VERSION 5.5 ;
NAMESCASESENSITIVE ON ;
BUSBITCHARS "[]" ;
DIVIDERCHAR "/" ;

PROPERTYDEFINITIONS
  LAYER routingPitch REAL ;
END PROPERTYDEFINITIONS

UNITS
  DATABASE MICRONS 1000 ;
END UNITS
MANUFACTURINGGRID 0.01 ;
LAYER POLY1
  TYPE MASTERSLICE ;
END POLY1

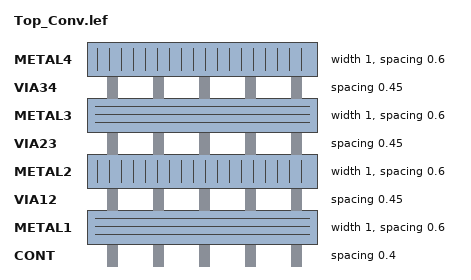
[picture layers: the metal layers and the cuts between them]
LAYER CONT
  TYPE CUT ;
  SPACING 0.4 ;
END CONT

LAYER METAL1
  TYPE ROUTING ;
  DIRECTION HORIZONTAL ;
  PITCH 0 ;
  WIDTH 1 ;
  SPACING 0.6 ;
  PROPERTY routingPitch 1.25 ;
END METAL1

LAYER VIA12
  TYPE CUT ;
  SPACING 0.45 ;
END VIA12

LAYER METAL2
  TYPE ROUTING ;
  DIRECTION VERTICAL ;
  PITCH 0 ;
  WIDTH 1 ;
  SPACING 0.6 ;
  PROPERTY routingPitch 1.4 ;
END METAL2

LAYER VIA23
  TYPE CUT ;
  SPACING 0.45 ;
END VIA23

LAYER METAL3
  TYPE ROUTING ;
  DIRECTION HORIZONTAL ;
  PITCH 0 ;
  WIDTH 1 ;
  SPACING 0.6 ;
  PROPERTY routingPitch 1.25 ;
END METAL3

LAYER VIA34
  TYPE CUT ;
  SPACING 0.45 ;
END VIA34

LAYER METAL4
  TYPE ROUTING ;
  DIRECTION VERTICAL ;
  PITCH 0 ;
  WIDTH 1 ;
  SPACING 0.6 ;
  PROPERTY routingPitch 1.4 ;
END METAL4

LAYER OVERLAP
  TYPE OVERLAP ;
END OVERLAP

VIARULE M4_M3 GENERATE
  LAYER METAL3 ;
    ENCLOSURE 0.2 0.2 ;
  LAYER METAL4 ;
    ENCLOSURE 0.15 0.15 ;
  LAYER VIA34 ;
    RECT -0.25 -0.25 0.25 0.25 ;
    SPACING 1 BY 1 ;
END M4_M3

VIARULE M3_M2 GENERATE
  LAYER METAL2 ;
    ENCLOSURE 0.2 0.2 ;
  LAYER METAL3 ;
    ENCLOSURE 0.15 0.15 ;
  LAYER VIA23 ;
    RECT -0.25 -0.25 0.25 0.25 ;
    SPACING 1 BY 1 ;
END M3_M2

VIARULE M2_M1 GENERATE
  LAYER METAL1 ;
    ENCLOSURE 0.2 0.2 ;
  LAYER METAL2 ;
    ENCLOSURE 0.15 0.15 ;
  LAYER VIA12 ;
    RECT -0.25 -0.25 0.25 0.25 ;
    SPACING 1 BY 1 ;
END M2_M1

VIARULE M1_POLY1 GENERATE
  LAYER POLY1 ;
    ENCLOSURE 0.2 0.2 ;
  LAYER METAL1 ;
    ENCLOSURE 0.15 0.15 ;
  LAYER CONT ;
    RECT -0.2 -0.2 0.2 0.2 ;
    SPACING 1 BY 1 ;
END M1_POLY1

VIA M1_POLY1
  LAYER CONT ;
    RECT -0.2 -0.2 0.2 0.2 ;
  LAYER POLY1 ;
    RECT -0.4 -0.4 0.4 0.4 ;
  LAYER METAL1 ;
    RECT -0.35 -0.35 0.35 0.35 ;
END M1_POLY1

VIA M2_M1
  LAYER VIA12 ;
    RECT -0.25 -0.25 0.25 0.25 ;
  LAYER METAL2 ;
    RECT -0.4 -0.4 0.4 0.4 ;
  LAYER METAL1 ;
    RECT -0.45 -0.45 0.45 0.45 ;
END M2_M1

VIA M3_M2
  LAYER VIA23 ;
    RECT -0.25 -0.25 0.25 0.25 ;
  LAYER METAL3 ;
    RECT -0.4 -0.4 0.4 0.4 ;
  LAYER METAL2 ;
    RECT -0.45 -0.45 0.45 0.45 ;
END M3_M2

VIA M4_M3
  LAYER VIA34 ;
    RECT -0.25 -0.25 0.25 0.25 ;
  LAYER METAL4 ;
    RECT -0.4 -0.4 0.4 0.4 ;
  LAYER METAL3 ;
    RECT -0.45 -0.45 0.45 0.45 ;
END M4_M3


MACRO ConvNN_AvgPool
  PIN n_Kvmm_AP_Dr_bit<9>
    DIRECTION INOUT ;
    USE SIGNAL ;
    PORT
      LAYER METAL3 ;
        RECT 671.3 1946.49 672.7 1948.73 ;
    END
  END n_Kvmm_AP_Dr_bit<9>
  PIN n_Kvmm_AP_Dr_bit<8>
    DIRECTION INOUT ;
    USE SIGNAL ;
    PORT
      LAYER METAL3 ;
        RECT 657.3 1946.49 658.7 1948.73 ;
    END
  END n_Kvmm_AP_Dr_bit<8>
  PIN n_SR_k_col_CLKB
    DIRECTION INOUT ;
    USE SIGNAL ;
    PORT
      LAYER METAL3 ;
        RECT 643.3 1946.49 644.7 1948.73 ;
    END
  END n_SR_k_col_CLKB
  PIN e_sub_img_out<37>
    DIRECTION INOUT ;
    USE SIGNAL ;
    PORT
      LAYER METAL3 ;
        RECT 1894.72 1375.24 1897.02 1376.64 ;
    END
  END e_sub_img_out<37>
  PIN e_sub_img_out<36>
    DIRECTION INOUT ;
    USE SIGNAL ;
    PORT
      LAYER METAL3 ;
        RECT 1894.72 1389.24 1897.02 1390.64 ;
    END
  END e_sub_img_out<36>
  PIN e_sub_img_out<35>
    DIRECTION INOUT ;
    USE SIGNAL ;
    PORT
      LAYER METAL3 ;
        RECT 1894.72 1403.24 1897.02 1404.64 ;
    END
  END e_sub_img_out<35>
  PIN e_sub_img_out<34>
    DIRECTION INOUT ;
    USE SIGNAL ;
    PORT
      LAYER METAL3 ;
        RECT 1894.72 1417.24 1897.02 1418.64 ;
    END
  END e_sub_img_out<34>
  PIN e_sub_img_out<33>
    DIRECTION INOUT ;
    USE SIGNAL ;
    PORT
      LAYER METAL3 ;
        RECT 1894.72 1431.24 1897.02 1432.64 ;
    END
  END e_sub_img_out<33>
  PIN e_sub_img_out<32>
    DIRECTION INOUT ;
    USE SIGNAL ;
    PORT
      LAYER METAL3 ;
        RECT 1894.72 1445.24 1897.02 1446.64 ;
    END
  END e_sub_img_out<32>
  PIN e_sub_img_out<31>
    DIRECTION INOUT ;
    USE SIGNAL ;
    PORT
      LAYER METAL3 ;
        RECT 1894.72 1459.24 1897.02 1460.64 ;
    END
  END e_sub_img_out<31>
  PIN e_sub_img_out<30>
    DIRECTION INOUT ;
    USE SIGNAL ;
    PORT
      LAYER METAL3 ;
        RECT 1894.72 1473.24 1897.02 1474.64 ;
    END
  END e_sub_img_out<30>
  PIN e_sub_img_out<29>
    DIRECTION INOUT ;
    USE SIGNAL ;
    PORT
      LAYER METAL3 ;
        RECT 1894.72 1487.24 1897.02 1488.64 ;
    END
  END e_sub_img_out<29>
  PIN e_sub_img_out<28>
    DIRECTION INOUT ;
    USE SIGNAL ;
    PORT
      LAYER METAL3 ;
        RECT 1894.72 1501.24 1897.02 1502.64 ;
    END
  END e_sub_img_out<28>
  PIN e_sub_img_out<27>
    DIRECTION INOUT ;
    USE SIGNAL ;
    PORT
      LAYER METAL3 ;
        RECT 1894.72 1515.24 1897.02 1516.64 ;
    END
  END e_sub_img_out<27>
  PIN e_sub_img_out<26>
    DIRECTION INOUT ;
    USE SIGNAL ;
    PORT
      LAYER METAL3 ;
        RECT 1894.72 1529.24 1897.02 1530.64 ;
    END
  END e_sub_img_out<26>
  PIN e_sub_img_out<25>
    DIRECTION INOUT ;
    USE SIGNAL ;
    PORT
      LAYER METAL3 ;
        RECT 1894.72 1543.24 1897.02 1544.64 ;
    END
  END e_sub_img_out<25>
  PIN e_sub_img_out<24>
    DIRECTION INOUT ;
    USE SIGNAL ;
    PORT
      LAYER METAL3 ;
        RECT 1894.72 1557.24 1897.02 1558.64 ;
    END
  END e_sub_img_out<24>
  PIN e_sub_img_out<23>
    DIRECTION INOUT ;
    USE SIGNAL ;
    PORT
      LAYER METAL3 ;
        RECT 1894.72 1571.24 1897.02 1572.64 ;
    END
  END e_sub_img_out<23>
  PIN e_sub_img_out<22>
    DIRECTION INOUT ;
    USE SIGNAL ;
    PORT
      LAYER METAL3 ;
        RECT 1894.72 1585.24 1897.02 1586.64 ;
    END
  END e_sub_img_out<22>
  PIN e_sub_img_out<21>
    DIRECTION INOUT ;
    USE SIGNAL ;
    PORT
      LAYER METAL3 ;
        RECT 1894.72 1599.24 1897.02 1600.64 ;
    END
  END e_sub_img_out<21>
  PIN e_sub_img_out<20>
    DIRECTION INOUT ;
    USE SIGNAL ;
    PORT
      LAYER METAL3 ;
        RECT 1894.72 1613.24 1897.02 1614.64 ;
    END
  END e_sub_img_out<20>
  PIN e_sub_img_out<19>
    DIRECTION INOUT ;
    USE SIGNAL ;
    PORT
      LAYER METAL3 ;
        RECT 1894.72 1627.24 1897.02 1628.64 ;
    END
  END e_sub_img_out<19>
  PIN e_sub_img_out<18>
    DIRECTION INOUT ;
    USE SIGNAL ;
    PORT
      LAYER METAL3 ;
        RECT 1894.72 1641.24 1897.02 1642.64 ;
    END
  END e_sub_img_out<18>
  PIN e_sub_img_out<17>
    DIRECTION INOUT ;
    USE SIGNAL ;
    PORT
      LAYER METAL3 ;
        RECT 1894.72 1655.24 1897.02 1656.64 ;
    END
  END e_sub_img_out<17>
  PIN e_sub_img_out<16>
    DIRECTION INOUT ;
    USE SIGNAL ;
    PORT
      LAYER METAL3 ;
        RECT 1894.72 1669.24 1897.02 1670.64 ;
    END
  END e_sub_img_out<16>
  PIN e_sub_img_out<15>
    DIRECTION INOUT ;
    USE SIGNAL ;
    PORT
      LAYER METAL3 ;
        RECT 1894.72 1683.24 1897.02 1684.64 ;
    END
  END e_sub_img_out<15>
  PIN e_sub_img_out<14>
    DIRECTION INOUT ;
    USE SIGNAL ;
    PORT
      LAYER METAL3 ;
        RECT 1894.72 1697.24 1897.02 1698.64 ;
    END
  END e_sub_img_out<14>
  PIN e_sub_img_out<13>
    DIRECTION INOUT ;
    USE SIGNAL ;
    PORT
      LAYER METAL3 ;
        RECT 1894.72 1711.24 1897.02 1712.64 ;
    END
  END e_sub_img_out<13>
  PIN e_sub_img_out<12>
    DIRECTION INOUT ;
    USE SIGNAL ;
    PORT
      LAYER METAL3 ;
        RECT 1894.72 1725.24 1897.02 1726.64 ;
    END
  END e_sub_img_out<12>
  PIN e_sub_img_out<11>
    DIRECTION INOUT ;
    USE SIGNAL ;
    PORT
      LAYER METAL3 ;
        RECT 1894.72 1739.24 1897.02 1740.64 ;
    END
  END e_sub_img_out<11>
  PIN e_sub_img_out<10>
    DIRECTION INOUT ;
    USE SIGNAL ;
    PORT
      LAYER METAL3 ;
        RECT 1894.72 1753.24 1897.02 1754.64 ;
    END
  END e_sub_img_out<10>
  PIN e_sub_img_out<9>
    DIRECTION INOUT ;
    USE SIGNAL ;
    PORT
      LAYER METAL3 ;
        RECT 1894.72 1767.24 1897.02 1768.64 ;
    END
  END e_sub_img_out<9>
  PIN e_sub_img_out<8>
    DIRECTION INOUT ;
    USE SIGNAL ;
    PORT
      LAYER METAL3 ;
        RECT 1894.72 1781.24 1897.02 1782.64 ;
    END
  END e_sub_img_out<8>
  PIN e_sub_img_out<7>
    DIRECTION INOUT ;
    USE SIGNAL ;
    PORT
      LAYER METAL3 ;
        RECT 1894.72 1795.24 1897.02 1796.64 ;
    END
  END e_sub_img_out<7>
  PIN e_sub_img_out<6>
    DIRECTION INOUT ;
    USE SIGNAL ;
    PORT
      LAYER METAL3 ;
        RECT 1894.72 1809.24 1897.02 1810.64 ;
    END
  END e_sub_img_out<6>
  PIN e_sub_img_out<5>
    DIRECTION INOUT ;
    USE SIGNAL ;
    PORT
      LAYER METAL3 ;
        RECT 1894.72 1823.24 1897.02 1824.64 ;
    END
  END e_sub_img_out<5>
  PIN e_sub_img_out<4>
    DIRECTION INOUT ;
    USE SIGNAL ;
    PORT
      LAYER METAL3 ;
        RECT 1894.72 1837.24 1897.02 1838.64 ;
    END
  END e_sub_img_out<4>
  PIN e_sub_img_out<3>
    DIRECTION INOUT ;
    USE SIGNAL ;
    PORT
      LAYER METAL3 ;
        RECT 1894.72 1851.24 1897.02 1852.64 ;
    END
  END e_sub_img_out<3>
  PIN e_sub_img_out<2>
    DIRECTION INOUT ;
    USE SIGNAL ;
    PORT
      LAYER METAL3 ;
        RECT 1894.72 1865.24 1897.02 1866.64 ;
    END
  END e_sub_img_out<2>
  PIN e_sub_img_out<1>
    DIRECTION INOUT ;
    USE SIGNAL ;
    PORT
      LAYER METAL3 ;
        RECT 1894.72 1879.24 1897.02 1880.64 ;
    END
  END e_sub_img_out<1>
  PIN e_sub_img_out<0>
    DIRECTION INOUT ;
    USE SIGNAL ;
    PORT
      LAYER METAL3 ;
        RECT 1894.72 1893.24 1897.02 1894.64 ;
    END
  END e_sub_img_out<0>
  PIN n_Global_rst_b
    DIRECTION INOUT ;
    USE SIGNAL ;
    PORT
      LAYER METAL3 ;
        RECT 629.3 1946.49 630.7 1948.73 ;
    END
  END n_Global_rst_b
  PIN n_AVDD_by_2
    DIRECTION INOUT ;
    USE SIGNAL ;
    PORT
      LAYER METAL3 ;
        RECT 615.3 1946.49 616.7 1948.73 ;
    END
  END n_AVDD_by_2
  PIN n_run_hv
    DIRECTION INOUT ;
    USE SIGNAL ;
    PORT
      LAYER METAL3 ;
        RECT 601.3 1946.49 602.7 1948.73 ;
    END
  END n_run_hv
  PIN n_prog_hv
    DIRECTION INOUT ;
    USE SIGNAL ;
    PORT
      LAYER METAL3 ;
        RECT 587.3 1946.49 588.7 1948.73 ;
    END
  END n_prog_hv
  PIN n_VGPROG
    DIRECTION INOUT ;
    USE SIGNAL ;
    PORT
      LAYER METAL3 ;
        RECT 573.3 1946.49 574.7 1948.73 ;
    END
  END n_VGPROG
  PIN n_VINJ
    DIRECTION INOUT ;
    USE SIGNAL ;
    PORT
      LAYER METAL3 ;
        RECT 559.3 1946.49 560.7 1948.73 ;
    END
  END n_VINJ
  PIN n_GND
    DIRECTION INOUT ;
    USE SIGNAL ;
    PORT
      LAYER METAL3 ;
        RECT 545.3 1946.49 546.7 1948.73 ;
    END
  END n_GND
  PIN n_AVDD
    DIRECTION INOUT ;
    USE SIGNAL ;
    PORT
      LAYER METAL3 ;
        RECT 531.3 1946.49 532.7 1948.73 ;
    END
  END n_AVDD
  PIN n_DVDD
    DIRECTION INOUT ;
    USE SIGNAL ;
    PORT
      LAYER METAL3 ;
        RECT 517.3 1946.49 518.7 1948.73 ;
    END
  END n_DVDD
  PIN n_VTUN
    DIRECTION INOUT ;
    USE SIGNAL ;
    PORT
      LAYER METAL3 ;
        RECT 503.3 1946.49 504.7 1948.73 ;
    END
  END n_VTUN
  PIN n_AP_Relu_Vb
    DIRECTION INOUT ;
    USE SIGNAL ;
    PORT
      LAYER METAL3 ;
        RECT 489.3 1946.49 490.7 1948.73 ;
    END
  END n_AP_Relu_Vb
  PIN n_SR_k_rw_CLK
    DIRECTION INOUT ;
    USE SIGNAL ;
    PORT
      LAYER METAL3 ;
        RECT 475.3 1946.49 476.7 1948.73 ;
    END
  END n_SR_k_rw_CLK
  PIN n_SR_k_rw_RST_B
    DIRECTION INOUT ;
    USE SIGNAL ;
    PORT
      LAYER METAL3 ;
        RECT 461.3 1946.49 462.7 1948.73 ;
    END
  END n_SR_k_rw_RST_B
  PIN n_SR_k_rw_CLKB
    DIRECTION INOUT ;
    USE SIGNAL ;
    PORT
      LAYER METAL3 ;
        RECT 447.3 1946.49 448.7 1948.73 ;
    END
  END n_SR_k_rw_CLKB
  PIN n_SR_k_rw_Din
    DIRECTION INOUT ;
    USE SIGNAL ;
    PORT
      LAYER METAL3 ;
        RECT 433.3 1946.49 434.7 1948.73 ;
    END
  END n_SR_k_rw_Din
  PIN n_SR_Intg_CLKB
    DIRECTION INOUT ;
    USE SIGNAL ;
    PORT
      LAYER METAL3 ;
        RECT 419.3 1946.49 420.7 1948.73 ;
    END
  END n_SR_Intg_CLKB
  PIN n_SR_Intg_CLK
    DIRECTION INOUT ;
    USE SIGNAL ;
    PORT
      LAYER METAL3 ;
        RECT 405.3 1946.49 406.7 1948.73 ;
    END
  END n_SR_Intg_CLK
  PIN n_SR_Intg_Din
    DIRECTION INOUT ;
    USE SIGNAL ;
    PORT
      LAYER METAL3 ;
        RECT 391.3 1946.49 392.7 1948.73 ;
    END
  END n_SR_Intg_Din
  PIN n_SR_Intg_RST_B
    DIRECTION INOUT ;
    USE SIGNAL ;
    PORT
      LAYER METAL3 ;
        RECT 377.3 1946.49 378.7 1948.73 ;
    END
  END n_SR_Intg_RST_B
  PIN n_Vin_inp_Ch<2>
    DIRECTION INOUT ;
    USE SIGNAL ;
    PORT
      LAYER METAL3 ;
        RECT 363.3 1946.49 364.7 1948.73 ;
    END
  END n_Vin_inp_Ch<2>
  PIN n_Vin_inp_Ch<1>
    DIRECTION INOUT ;
    USE SIGNAL ;
    PORT
      LAYER METAL3 ;
        RECT 349.3 1946.49 350.7 1948.73 ;
    END
  END n_Vin_inp_Ch<1>
  PIN n_Vin_inp_Ch<0>
    DIRECTION INOUT ;
    USE SIGNAL ;
    PORT
      LAYER METAL3 ;
        RECT 335.3 1946.49 336.7 1948.73 ;
    END
  END n_Vin_inp_Ch<0>
  PIN n_SR_k_col_CLK
    DIRECTION INOUT ;
    USE SIGNAL ;
    PORT
      LAYER METAL3 ;
        RECT 321.3 1946.49 322.7 1948.73 ;
    END
  END n_SR_k_col_CLK
  PIN n_SR_k_col_RST_B
    DIRECTION INOUT ;
    USE SIGNAL ;
    PORT
      LAYER METAL3 ;
        RECT 307.3 1946.49 308.7 1948.73 ;
    END
  END n_SR_k_col_RST_B
  PIN n_SR_k_col_Din
    DIRECTION INOUT ;
    USE SIGNAL ;
    PORT
      LAYER METAL3 ;
        RECT 293.3 1946.49 294.7 1948.73 ;
    END
  END n_SR_k_col_Din
  PIN n_Kvmm_AP_Run_Drln
    DIRECTION INOUT ;
    USE SIGNAL ;
    PORT
      LAYER METAL3 ;
        RECT 279.3 1946.49 280.7 1948.73 ;
    END
  END n_Kvmm_AP_Run_Drln
  PIN n_Kvmm_AP_Prog_Drln
    DIRECTION INOUT ;
    USE SIGNAL ;
    PORT
      LAYER METAL3 ;
        RECT 265.3 1946.49 266.7 1948.73 ;
    END
  END n_Kvmm_AP_Prog_Drln
  PIN n_Kvmm_AP_Dr_bit<7>
    DIRECTION INOUT ;
    USE SIGNAL ;
    PORT
      LAYER METAL3 ;
        RECT 251.3 1946.49 252.7 1948.73 ;
    END
  END n_Kvmm_AP_Dr_bit<7>
  PIN n_Kvmm_AP_Dr_bit<6>
    DIRECTION INOUT ;
    USE SIGNAL ;
    PORT
      LAYER METAL3 ;
        RECT 237.3 1946.49 238.7 1948.73 ;
    END
  END n_Kvmm_AP_Dr_bit<6>
  PIN n_Kvmm_AP_Dr_bit<5>
    DIRECTION INOUT ;
    USE SIGNAL ;
    PORT
      LAYER METAL3 ;
        RECT 223.3 1946.49 224.7 1948.73 ;
    END
  END n_Kvmm_AP_Dr_bit<5>
  PIN n_Kvmm_AP_Dr_bit<4>
    DIRECTION INOUT ;
    USE SIGNAL ;
    PORT
      LAYER METAL3 ;
        RECT 209.3 1946.49 210.7 1948.73 ;
    END
  END n_Kvmm_AP_Dr_bit<4>
  PIN n_Kvmm_AP_Dr_bit<3>
    DIRECTION INOUT ;
    USE SIGNAL ;
    PORT
      LAYER METAL3 ;
        RECT 195.3 1946.49 196.7 1948.73 ;
    END
  END n_Kvmm_AP_Dr_bit<3>
  PIN n_Kvmm_AP_Dr_bit<2>
    DIRECTION INOUT ;
    USE SIGNAL ;
    PORT
      LAYER METAL3 ;
        RECT 181.3 1946.49 182.7 1948.73 ;
    END
  END n_Kvmm_AP_Dr_bit<2>
  PIN n_Kvmm_AP_Dr_bit<1>
    DIRECTION INOUT ;
    USE SIGNAL ;
    PORT
      LAYER METAL3 ;
        RECT 167.3 1946.49 168.7 1948.73 ;
    END
  END n_Kvmm_AP_Dr_bit<1>
  PIN n_Kvmm_AP_Dr_bit<0>
    DIRECTION INOUT ;
    USE SIGNAL ;
    PORT
      LAYER METAL3 ;
        RECT 153.3 1946.49 154.7 1948.73 ;
    END
  END n_Kvmm_AP_Dr_bit<0>
  PIN n_Kvmm_AP_Dr_En
    DIRECTION INOUT ;
    USE SIGNAL ;
    PORT
      LAYER METAL3 ;
        RECT 139.3 1946.49 140.7 1948.73 ;
    END
  END n_Kvmm_AP_Dr_En
  PIN n_AP_G_bit<2>
    DIRECTION INOUT ;
    USE SIGNAL ;
    PORT
      LAYER METAL3 ;
        RECT 125.3 1946.49 126.7 1948.73 ;
    END
  END n_AP_G_bit<2>
  PIN n_AP_G_bit<1>
    DIRECTION INOUT ;
    USE SIGNAL ;
    PORT
      LAYER METAL3 ;
        RECT 111.3 1946.49 112.7 1948.73 ;
    END
  END n_AP_G_bit<1>
  PIN n_AP_G_bit<0>
    DIRECTION INOUT ;
    USE SIGNAL ;
    PORT
      LAYER METAL3 ;
        RECT 97.3 1946.49 98.7 1948.73 ;
    END
  END n_AP_G_bit<0>
  PIN n_AP_G_En
    DIRECTION INOUT ;
    USE SIGNAL ;
    PORT
      LAYER METAL3 ;
        RECT 83.3 1946.49 84.7 1948.73 ;
    END
  END n_AP_G_En
  PIN n_Kvmm_G_bit<3>
    DIRECTION INOUT ;
    USE SIGNAL ;
    PORT
      LAYER METAL3 ;
        RECT 69.3 1946.49 70.7 1948.73 ;
    END
  END n_Kvmm_G_bit<3>
  PIN n_Kvmm_G_bit<2>
    DIRECTION INOUT ;
    USE SIGNAL ;
    PORT
      LAYER METAL3 ;
        RECT 55.3 1946.49 56.7 1948.73 ;
    END
  END n_Kvmm_G_bit<2>
  PIN n_Kvmm_G_bit<1>
    DIRECTION INOUT ;
    USE SIGNAL ;
    PORT
      LAYER METAL3 ;
        RECT 41.3 1946.49 42.7 1948.73 ;
    END
  END n_Kvmm_G_bit<1>
  PIN n_Kvmm_G_bit<0>
    DIRECTION INOUT ;
    USE SIGNAL ;
    PORT
      LAYER METAL3 ;
        RECT 27.3 1946.49 28.7 1948.73 ;
    END
  END n_Kvmm_G_bit<0>
  PIN n_Kvmm_G_En
    DIRECTION INOUT ;
    USE SIGNAL ;
    PORT
      LAYER METAL3 ;
        RECT 13.3 1946.49 14.7 1948.73 ;
    END
  END n_Kvmm_G_En
  PIN n_Final_rw_dbg
    DIRECTION INOUT ;
    USE SIGNAL ;
    PORT
      LAYER METAL3 ;
        RECT 769.3 1946.49 770.7 1948.73 ;
    END
  END n_Final_rw_dbg
  PIN n_AP_col_ctrl_dbg<0>
    DIRECTION INOUT ;
    USE SIGNAL ;
    PORT
      LAYER METAL3 ;
        RECT 685.3 1946.49 686.7 1948.73 ;
    END
  END n_AP_col_ctrl_dbg<0>
  PIN n_AP_col_ctrl_dbg<1>
    DIRECTION INOUT ;
    USE SIGNAL ;
    PORT
      LAYER METAL3 ;
        RECT 699.3 1946.49 700.7 1948.73 ;
    END
  END n_AP_col_ctrl_dbg<1>
  PIN n_Relu_en_b_dbg<0>
    DIRECTION INOUT ;
    USE SIGNAL ;
    PORT
      LAYER METAL3 ;
        RECT 713.3 1946.49 714.7 1948.73 ;
    END
  END n_Relu_en_b_dbg<0>
  PIN n_Relu_en_b_dbg<1>
    DIRECTION INOUT ;
    USE SIGNAL ;
    PORT
      LAYER METAL3 ;
        RECT 727.3 1946.49 728.7 1948.73 ;
    END
  END n_Relu_en_b_dbg<1>
  PIN n_intg_nxt_rw_dbg
    DIRECTION INOUT ;
    USE SIGNAL ;
    PORT
      LAYER METAL3 ;
        RECT 783.3 1946.49 784.7 1948.73 ;
    END
  END n_intg_nxt_rw_dbg
  PIN n_int_rst_dbg<0>
    DIRECTION INOUT ;
    USE SIGNAL ;
    PORT
      LAYER METAL3 ;
        RECT 741.3 1946.49 742.7 1948.73 ;
    END
  END n_int_rst_dbg<0>
  PIN n_int_rst_dbg<1>
    DIRECTION INOUT ;
    USE SIGNAL ;
    PORT
      LAYER METAL3 ;
        RECT 755.3 1946.49 756.7 1948.73 ;
    END
  END n_int_rst_dbg<1>
  PIN n_SR_int_dbg_Q<2>
    DIRECTION INOUT ;
    USE SIGNAL ;
    PORT
      LAYER METAL3 ;
        RECT 825.3 1946.49 826.7 1948.73 ;
    END
  END n_SR_int_dbg_Q<2>
  PIN n_SR_int_dbg_Q<3>
    DIRECTION INOUT ;
    USE SIGNAL ;
    PORT
      LAYER METAL3 ;
        RECT 839.3 1946.49 840.7 1948.73 ;
    END
  END n_SR_int_dbg_Q<3>
  PIN n_SR_int_dbg_Q<1>
    DIRECTION INOUT ;
    USE SIGNAL ;
    PORT
      LAYER METAL3 ;
        RECT 811.3 1946.49 812.7 1948.73 ;
    END
  END n_SR_int_dbg_Q<1>
  PIN n_SR_int_dbg_Q<0>
    DIRECTION INOUT ;
    USE SIGNAL ;
    PORT
      LAYER METAL3 ;
        RECT 797.3 1946.49 798.7 1948.73 ;
    END
  END n_SR_int_dbg_Q<0>
  PIN n_Vint_dbg<0>
    DIRECTION INOUT ;
    USE SIGNAL ;
    PORT
      LAYER METAL3 ;
        RECT 853.3 1946.49 854.7 1948.73 ;
    END
  END n_Vint_dbg<0>
  PIN n_Vint_dbg<1>
    DIRECTION INOUT ;
    USE SIGNAL ;
    PORT
      LAYER METAL3 ;
        RECT 867.3 1946.49 868.7 1948.73 ;
    END
  END n_Vint_dbg<1>
END ConvNN_AvgPool

MACRO ConvNN
  PIN n_SR_k_col_CLKB
    DIRECTION INOUT ;
    USE SIGNAL ;
    PORT
      LAYER METAL3 ;
        RECT 601.3 1527.93 602.7 1530.17 ;
    END
  END n_SR_k_col_CLKB
  PIN n_Global_rst_b
    DIRECTION INOUT ;
    USE SIGNAL ;
    PORT
      LAYER METAL3 ;
        RECT 559.3 1527.93 560.7 1530.17 ;
    END
  END n_Global_rst_b
  PIN n_AVDD_by_2
    DIRECTION INOUT ;
    USE SIGNAL ;
    PORT
      LAYER METAL3 ;
        RECT 545.3 1527.93 546.7 1530.17 ;
    END
  END n_AVDD_by_2
  PIN n_int_rst_dbg<1>
    DIRECTION INOUT ;
    USE SIGNAL ;
    PORT
      LAYER METAL3 ;
        RECT 657.3 1527.93 658.7 1530.17 ;
    END
  END n_int_rst_dbg<1>
  PIN n_SR_int_0_Q2_dbg
    DIRECTION INOUT ;
    USE SIGNAL ;
    PORT
      LAYER METAL3 ;
        RECT 629.3 1527.93 630.7 1530.17 ;
    END
  END n_SR_int_0_Q2_dbg
  PIN n_SR_Intg_dbg_Q<0>
    DIRECTION INOUT ;
    USE SIGNAL ;
    PORT
      LAYER METAL3 ;
        RECT 713.3 1527.93 714.7 1530.17 ;
    END
  END n_SR_Intg_dbg_Q<0>
  PIN n_sample_nxt_rw_dbg
    DIRECTION INOUT ;
    USE SIGNAL ;
    PORT
      LAYER METAL3 ;
        RECT 671.3 1527.93 672.7 1530.17 ;
    END
  END n_sample_nxt_rw_dbg
  PIN n_Out_En_dbg<0>
    DIRECTION INOUT ;
    USE SIGNAL ;
    PORT
      LAYER METAL3 ;
        RECT 685.3 1527.93 686.7 1530.17 ;
    END
  END n_Out_En_dbg<0>
  PIN n_Vint_dbg<1>
    DIRECTION INOUT ;
    USE SIGNAL ;
    PORT
      LAYER METAL3 ;
        RECT 755.3 1527.93 756.7 1530.17 ;
    END
  END n_Vint_dbg<1>
  PIN n_SR_Intg_dbg_Q<1>
    DIRECTION INOUT ;
    USE SIGNAL ;
    PORT
      LAYER METAL3 ;
        RECT 727.3 1527.93 728.7 1530.17 ;
    END
  END n_SR_Intg_dbg_Q<1>
  PIN n_Vint_dbg<0>
    DIRECTION INOUT ;
    USE SIGNAL ;
    PORT
      LAYER METAL3 ;
        RECT 741.3 1527.93 742.7 1530.17 ;
    END
  END n_Vint_dbg<0>
  PIN n_Rdout_flag_dbg
    DIRECTION INOUT ;
    USE SIGNAL ;
    PORT
      LAYER METAL3 ;
        RECT 615.3 1527.93 616.7 1530.17 ;
    END
  END n_Rdout_flag_dbg
  PIN n_Out_En_dbg<1>
    DIRECTION INOUT ;
    USE SIGNAL ;
    PORT
      LAYER METAL3 ;
        RECT 699.3 1527.93 700.7 1530.17 ;
    END
  END n_Out_En_dbg<1>
  PIN n_int_rst_dbg<0>
    DIRECTION INOUT ;
    USE SIGNAL ;
    PORT
      LAYER METAL3 ;
        RECT 643.3 1527.93 644.7 1530.17 ;
    END
  END n_int_rst_dbg<0>
  PIN n_sample_buf_Vb
    DIRECTION INOUT ;
    USE SIGNAL ;
    PORT
      LAYER METAL3 ;
        RECT 573.3 1527.93 574.7 1530.17 ;
    END
  END n_sample_buf_Vb
  PIN n_Relu_Vb
    DIRECTION INOUT ;
    USE SIGNAL ;
    PORT
      LAYER METAL3 ;
        RECT 587.3 1527.93 588.7 1530.17 ;
    END
  END n_Relu_Vb
  PIN w_Vin_inp_Ch<8>
    DIRECTION INOUT ;
    USE SIGNAL ;
    PORT
      LAYER METAL3 ;
        RECT 0.0 1369.52 2.8 1370.92 ;
    END
  END w_Vin_inp_Ch<8>
  PIN w_Vin_inp_Ch<7>
    DIRECTION INOUT ;
    USE SIGNAL ;
    PORT
      LAYER METAL3 ;
        RECT 0.0 1383.52 2.8 1384.92 ;
    END
  END w_Vin_inp_Ch<7>
  PIN w_Vin_inp_Ch<6>
    DIRECTION INOUT ;
    USE SIGNAL ;
    PORT
      LAYER METAL3 ;
        RECT 0.0 1397.52 2.8 1398.92 ;
    END
  END w_Vin_inp_Ch<6>
  PIN w_Vin_inp_Ch<5>
    DIRECTION INOUT ;
    USE SIGNAL ;
    PORT
      LAYER METAL3 ;
        RECT 0.0 1411.52 2.8 1412.92 ;
    END
  END w_Vin_inp_Ch<5>
  PIN w_Vin_inp_Ch<4>
    DIRECTION INOUT ;
    USE SIGNAL ;
    PORT
      LAYER METAL3 ;
        RECT 0.0 1425.52 2.8 1426.92 ;
    END
  END w_Vin_inp_Ch<4>
  PIN w_Vin_inp_Ch<3>
    DIRECTION INOUT ;
    USE SIGNAL ;
    PORT
      LAYER METAL3 ;
        RECT 0.0 1439.52 2.8 1440.92 ;
    END
  END w_Vin_inp_Ch<3>
  PIN w_Vin_inp_Ch<2>
    DIRECTION INOUT ;
    USE SIGNAL ;
    PORT
      LAYER METAL3 ;
        RECT 0.0 1453.52 2.8 1454.92 ;
    END
  END w_Vin_inp_Ch<2>
  PIN w_Vin_inp_Ch<1>
    DIRECTION INOUT ;
    USE SIGNAL ;
    PORT
      LAYER METAL3 ;
        RECT 0.0 1467.52 2.8 1468.92 ;
    END
  END w_Vin_inp_Ch<1>
  PIN w_Vin_inp_Ch<0>
    DIRECTION INOUT ;
    USE SIGNAL ;
    PORT
      LAYER METAL3 ;
        RECT 0.0 1481.52 2.8 1482.92 ;
    END
  END w_Vin_inp_Ch<0>
  PIN w_Vin_inp_Ch<23>
    DIRECTION INOUT ;
    USE SIGNAL ;
    PORT
      LAYER METAL3 ;
        RECT 0.0 1159.52 2.8 1160.92 ;
    END
  END w_Vin_inp_Ch<23>
  PIN w_Vin_inp_Ch<22>
    DIRECTION INOUT ;
    USE SIGNAL ;
    PORT
      LAYER METAL3 ;
        RECT 0.0 1173.52 2.8 1174.92 ;
    END
  END w_Vin_inp_Ch<22>
  PIN n_run_hv
    DIRECTION INOUT ;
    USE SIGNAL ;
    PORT
      LAYER METAL3 ;
        RECT 531.3 1527.93 532.7 1530.17 ;
    END
  END n_run_hv
  PIN n_prog_hv
    DIRECTION INOUT ;
    USE SIGNAL ;
    PORT
      LAYER METAL3 ;
        RECT 517.3 1527.93 518.7 1530.17 ;
    END
  END n_prog_hv
  PIN n_VGPROG
    DIRECTION INOUT ;
    USE SIGNAL ;
    PORT
      LAYER METAL3 ;
        RECT 503.3 1527.93 504.7 1530.17 ;
    END
  END n_VGPROG
  PIN n_VINJ
    DIRECTION INOUT ;
    USE SIGNAL ;
    PORT
      LAYER METAL3 ;
        RECT 489.3 1527.93 490.7 1530.17 ;
    END
  END n_VINJ
  PIN n_GND
    DIRECTION INOUT ;
    USE SIGNAL ;
    PORT
      LAYER METAL3 ;
        RECT 475.3 1527.93 476.7 1530.17 ;
    END
  END n_GND
  PIN n_AVDD
    DIRECTION INOUT ;
    USE SIGNAL ;
    PORT
      LAYER METAL3 ;
        RECT 461.3 1527.93 462.7 1530.17 ;
    END
  END n_AVDD
  PIN n_DVDD
    DIRECTION INOUT ;
    USE SIGNAL ;
    PORT
      LAYER METAL3 ;
        RECT 447.3 1527.93 448.7 1530.17 ;
    END
  END n_DVDD
  PIN n_VTUN
    DIRECTION INOUT ;
    USE SIGNAL ;
    PORT
      LAYER METAL3 ;
        RECT 433.3 1527.93 434.7 1530.17 ;
    END
  END n_VTUN
  PIN n_SR_k_rw_CLK
    DIRECTION INOUT ;
    USE SIGNAL ;
    PORT
      LAYER METAL3 ;
        RECT 419.3 1527.93 420.7 1530.17 ;
    END
  END n_SR_k_rw_CLK
  PIN n_SR_k_rw_RST_B
    DIRECTION INOUT ;
    USE SIGNAL ;
    PORT
      LAYER METAL3 ;
        RECT 405.3 1527.93 406.7 1530.17 ;
    END
  END n_SR_k_rw_RST_B
  PIN n_SR_k_rw_CLKB
    DIRECTION INOUT ;
    USE SIGNAL ;
    PORT
      LAYER METAL3 ;
        RECT 391.3 1527.93 392.7 1530.17 ;
    END
  END n_SR_k_rw_CLKB
  PIN n_SR_k_rw_Din
    DIRECTION INOUT ;
    USE SIGNAL ;
    PORT
      LAYER METAL3 ;
        RECT 377.3 1527.93 378.7 1530.17 ;
    END
  END n_SR_k_rw_Din
  PIN n_SR_Intg_CLKB
    DIRECTION INOUT ;
    USE SIGNAL ;
    PORT
      LAYER METAL3 ;
        RECT 363.3 1527.93 364.7 1530.17 ;
    END
  END n_SR_Intg_CLKB
  PIN n_SR_Intg_CLK
    DIRECTION INOUT ;
    USE SIGNAL ;
    PORT
      LAYER METAL3 ;
        RECT 349.3 1527.93 350.7 1530.17 ;
    END
  END n_SR_Intg_CLK
  PIN n_SR_Intg_Din
    DIRECTION INOUT ;
    USE SIGNAL ;
    PORT
      LAYER METAL3 ;
        RECT 335.3 1527.93 336.7 1530.17 ;
    END
  END n_SR_Intg_Din
  PIN n_SR_Intg_RST_B
    DIRECTION INOUT ;
    USE SIGNAL ;
    PORT
      LAYER METAL3 ;
        RECT 321.3 1527.93 322.7 1530.17 ;
    END
  END n_SR_Intg_RST_B
  PIN n_SR_k_col_CLK
    DIRECTION INOUT ;
    USE SIGNAL ;
    PORT
      LAYER METAL3 ;
        RECT 307.3 1527.93 308.7 1530.17 ;
    END
  END n_SR_k_col_CLK
  PIN n_SR_k_col_RST_B
    DIRECTION INOUT ;
    USE SIGNAL ;
    PORT
      LAYER METAL3 ;
        RECT 293.3 1527.93 294.7 1530.17 ;
    END
  END n_SR_k_col_RST_B
  PIN n_SR_k_col_Din
    DIRECTION INOUT ;
    USE SIGNAL ;
    PORT
      LAYER METAL3 ;
        RECT 279.3 1527.93 280.7 1530.17 ;
    END
  END n_SR_k_col_Din
  PIN n_Kvmm_Run_Drln
    DIRECTION INOUT ;
    USE SIGNAL ;
    PORT
      LAYER METAL3 ;
        RECT 265.3 1527.93 266.7 1530.17 ;
    END
  END n_Kvmm_Run_Drln
  PIN n_Kvmm_Prog_Drln
    DIRECTION INOUT ;
    USE SIGNAL ;
    PORT
      LAYER METAL3 ;
        RECT 251.3 1527.93 252.7 1530.17 ;
    END
  END n_Kvmm_Prog_Drln
  PIN n_Kvmm_Dr_bit<7>
    DIRECTION INOUT ;
    USE SIGNAL ;
    PORT
      LAYER METAL3 ;
        RECT 237.3 1527.93 238.7 1530.17 ;
    END
  END n_Kvmm_Dr_bit<7>
  PIN n_Kvmm_Dr_bit<6>
    DIRECTION INOUT ;
    USE SIGNAL ;
    PORT
      LAYER METAL3 ;
        RECT 223.3 1527.93 224.7 1530.17 ;
    END
  END n_Kvmm_Dr_bit<6>
  PIN n_Kvmm_Dr_bit<5>
    DIRECTION INOUT ;
    USE SIGNAL ;
    PORT
      LAYER METAL3 ;
        RECT 209.3 1527.93 210.7 1530.17 ;
    END
  END n_Kvmm_Dr_bit<5>
  PIN n_Kvmm_Dr_bit<4>
    DIRECTION INOUT ;
    USE SIGNAL ;
    PORT
      LAYER METAL3 ;
        RECT 195.3 1527.93 196.7 1530.17 ;
    END
  END n_Kvmm_Dr_bit<4>
  PIN n_Kvmm_Dr_bit<3>
    DIRECTION INOUT ;
    USE SIGNAL ;
    PORT
      LAYER METAL3 ;
        RECT 181.3 1527.93 182.7 1530.17 ;
    END
  END n_Kvmm_Dr_bit<3>
  PIN n_Kvmm_Dr_bit<2>
    DIRECTION INOUT ;
    USE SIGNAL ;
    PORT
      LAYER METAL3 ;
        RECT 167.3 1527.93 168.7 1530.17 ;
    END
  END n_Kvmm_Dr_bit<2>
  PIN n_Kvmm_Dr_bit<1>
    DIRECTION INOUT ;
    USE SIGNAL ;
    PORT
      LAYER METAL3 ;
        RECT 153.3 1527.93 154.7 1530.17 ;
    END
  END n_Kvmm_Dr_bit<1>
  PIN n_Kvmm_Dr_bit<0>
    DIRECTION INOUT ;
    USE SIGNAL ;
    PORT
      LAYER METAL3 ;
        RECT 139.3 1527.93 140.7 1530.17 ;
    END
  END n_Kvmm_Dr_bit<0>
  PIN n_Kvmm_Dr_En
    DIRECTION INOUT ;
    USE SIGNAL ;
    PORT
      LAYER METAL3 ;
        RECT 125.3 1527.93 126.7 1530.17 ;
    END
  END n_Kvmm_Dr_En
  PIN n_Kvmm_G_bit<6>
    DIRECTION INOUT ;
    USE SIGNAL ;
    PORT
      LAYER METAL3 ;
        RECT 111.3 1527.93 112.7 1530.17 ;
    END
  END n_Kvmm_G_bit<6>
  PIN n_Kvmm_G_bit<5>
    DIRECTION INOUT ;
    USE SIGNAL ;
    PORT
      LAYER METAL3 ;
        RECT 97.3 1527.93 98.7 1530.17 ;
    END
  END n_Kvmm_G_bit<5>
  PIN n_Kvmm_G_bit<4>
    DIRECTION INOUT ;
    USE SIGNAL ;
    PORT
      LAYER METAL3 ;
        RECT 83.3 1527.93 84.7 1530.17 ;
    END
  END n_Kvmm_G_bit<4>
  PIN n_Kvmm_G_bit<3>
    DIRECTION INOUT ;
    USE SIGNAL ;
    PORT
      LAYER METAL3 ;
        RECT 69.3 1527.93 70.7 1530.17 ;
    END
  END n_Kvmm_G_bit<3>
  PIN n_Kvmm_G_bit<2>
    DIRECTION INOUT ;
    USE SIGNAL ;
    PORT
      LAYER METAL3 ;
        RECT 55.3 1527.93 56.7 1530.17 ;
    END
  END n_Kvmm_G_bit<2>
  PIN n_Kvmm_G_bit<1>
    DIRECTION INOUT ;
    USE SIGNAL ;
    PORT
      LAYER METAL3 ;
        RECT 41.3 1527.93 42.7 1530.17 ;
    END
  END n_Kvmm_G_bit<1>
  PIN n_Kvmm_G_bit<0>
    DIRECTION INOUT ;
    USE SIGNAL ;
    PORT
      LAYER METAL3 ;
        RECT 27.3 1527.93 28.7 1530.17 ;
    END
  END n_Kvmm_G_bit<0>
  PIN n_Kvmm_G_En
    DIRECTION INOUT ;
    USE SIGNAL ;
    PORT
      LAYER METAL3 ;
        RECT 13.3 1527.93 14.7 1530.17 ;
    END
  END n_Kvmm_G_En
  PIN w_Vin_inp_Ch<21>
    DIRECTION INOUT ;
    USE SIGNAL ;
    PORT
      LAYER METAL3 ;
        RECT 0.0 1187.52 2.8 1188.92 ;
    END
  END w_Vin_inp_Ch<21>
  PIN w_Vin_inp_Ch<20>
    DIRECTION INOUT ;
    USE SIGNAL ;
    PORT
      LAYER METAL3 ;
        RECT 0.0 1201.52 2.8 1202.92 ;
    END
  END w_Vin_inp_Ch<20>
  PIN w_Vin_inp_Ch<19>
    DIRECTION INOUT ;
    USE SIGNAL ;
    PORT
      LAYER METAL3 ;
        RECT 0.0 1215.52 2.8 1216.92 ;
    END
  END w_Vin_inp_Ch<19>
  PIN w_Vin_inp_Ch<18>
    DIRECTION INOUT ;
    USE SIGNAL ;
    PORT
      LAYER METAL3 ;
        RECT 0.0 1229.52 2.8 1230.92 ;
    END
  END w_Vin_inp_Ch<18>
  PIN w_Vin_inp_Ch<17>
    DIRECTION INOUT ;
    USE SIGNAL ;
    PORT
      LAYER METAL3 ;
        RECT 0.0 1243.52 2.8 1244.92 ;
    END
  END w_Vin_inp_Ch<17>
  PIN w_Vin_inp_Ch<16>
    DIRECTION INOUT ;
    USE SIGNAL ;
    PORT
      LAYER METAL3 ;
        RECT 0.0 1257.52 2.8 1258.92 ;
    END
  END w_Vin_inp_Ch<16>
  PIN w_Vin_inp_Ch<15>
    DIRECTION INOUT ;
    USE SIGNAL ;
    PORT
      LAYER METAL3 ;
        RECT 0.0 1271.52 2.8 1272.92 ;
    END
  END w_Vin_inp_Ch<15>
  PIN w_Vin_inp_Ch<14>
    DIRECTION INOUT ;
    USE SIGNAL ;
    PORT
      LAYER METAL3 ;
        RECT 0.0 1285.52 2.8 1286.92 ;
    END
  END w_Vin_inp_Ch<14>
  PIN w_Vin_inp_Ch<13>
    DIRECTION INOUT ;
    USE SIGNAL ;
    PORT
      LAYER METAL3 ;
        RECT 0.0 1299.52 2.8 1300.92 ;
    END
  END w_Vin_inp_Ch<13>
  PIN w_Vin_inp_Ch<12>
    DIRECTION INOUT ;
    USE SIGNAL ;
    PORT
      LAYER METAL3 ;
        RECT 0.0 1313.52 2.8 1314.92 ;
    END
  END w_Vin_inp_Ch<12>
  PIN w_Vin_inp_Ch<11>
    DIRECTION INOUT ;
    USE SIGNAL ;
    PORT
      LAYER METAL3 ;
        RECT 0.0 1327.52 2.8 1328.92 ;
    END
  END w_Vin_inp_Ch<11>
  PIN w_Vin_inp_Ch<10>
    DIRECTION INOUT ;
    USE SIGNAL ;
    PORT
      LAYER METAL3 ;
        RECT 0.0 1341.52 2.8 1342.92 ;
    END
  END w_Vin_inp_Ch<10>
  PIN w_Vin_inp_Ch<9>
    DIRECTION INOUT ;
    USE SIGNAL ;
    PORT
      LAYER METAL3 ;
        RECT 0.0 1355.52 2.8 1356.92 ;
    END
  END w_Vin_inp_Ch<9>
  PIN w_Vin_inp_Ch<30>
    DIRECTION INOUT ;
    USE SIGNAL ;
    PORT
      LAYER METAL3 ;
        RECT 0.0 1061.52 2.8 1062.92 ;
    END
  END w_Vin_inp_Ch<30>
  PIN w_Vin_inp_Ch<29>
    DIRECTION INOUT ;
    USE SIGNAL ;
    PORT
      LAYER METAL3 ;
        RECT 0.0 1075.52 2.8 1076.92 ;
    END
  END w_Vin_inp_Ch<29>
  PIN w_Vin_inp_Ch<28>
    DIRECTION INOUT ;
    USE SIGNAL ;
    PORT
      LAYER METAL3 ;
        RECT 0.0 1089.52 2.8 1090.92 ;
    END
  END w_Vin_inp_Ch<28>
  PIN w_Vin_inp_Ch<27>
    DIRECTION INOUT ;
    USE SIGNAL ;
    PORT
      LAYER METAL3 ;
        RECT 0.0 1103.52 2.8 1104.92 ;
    END
  END w_Vin_inp_Ch<27>
  PIN w_Vin_inp_Ch<26>
    DIRECTION INOUT ;
    USE SIGNAL ;
    PORT
      LAYER METAL3 ;
        RECT 0.0 1117.52 2.8 1118.92 ;
    END
  END w_Vin_inp_Ch<26>
  PIN w_Vin_inp_Ch<25>
    DIRECTION INOUT ;
    USE SIGNAL ;
    PORT
      LAYER METAL3 ;
        RECT 0.0 1131.52 2.8 1132.92 ;
    END
  END w_Vin_inp_Ch<25>
  PIN w_Vin_inp_Ch<24>
    DIRECTION INOUT ;
    USE SIGNAL ;
    PORT
      LAYER METAL3 ;
        RECT 0.0 1145.52 2.8 1146.92 ;
    END
  END w_Vin_inp_Ch<24>
  PIN w_sub_img_out<15>
    DIRECTION INOUT ;
    USE SIGNAL ;
    PORT
      LAYER METAL3 ;
        RECT 0.0 767.52 2.8 768.92 ;
    END
  END w_sub_img_out<15>
  PIN w_sub_img_out<14>
    DIRECTION INOUT ;
    USE SIGNAL ;
    PORT
      LAYER METAL3 ;
        RECT 0.0 781.52 2.8 782.92 ;
    END
  END w_sub_img_out<14>
  PIN w_sub_img_out<13>
    DIRECTION INOUT ;
    USE SIGNAL ;
    PORT
      LAYER METAL3 ;
        RECT 0.0 795.52 2.8 796.92 ;
    END
  END w_sub_img_out<13>
  PIN w_sub_img_out<12>
    DIRECTION INOUT ;
    USE SIGNAL ;
    PORT
      LAYER METAL3 ;
        RECT 0.0 809.52 2.8 810.92 ;
    END
  END w_sub_img_out<12>
  PIN w_sub_img_out<11>
    DIRECTION INOUT ;
    USE SIGNAL ;
    PORT
      LAYER METAL3 ;
        RECT 0.0 823.52 2.8 824.92 ;
    END
  END w_sub_img_out<11>
  PIN w_sub_img_out<10>
    DIRECTION INOUT ;
    USE SIGNAL ;
    PORT
      LAYER METAL3 ;
        RECT 0.0 837.52 2.8 838.92 ;
    END
  END w_sub_img_out<10>
  PIN w_sub_img_out<9>
    DIRECTION INOUT ;
    USE SIGNAL ;
    PORT
      LAYER METAL3 ;
        RECT 0.0 851.52 2.8 852.92 ;
    END
  END w_sub_img_out<9>
  PIN w_sub_img_out<8>
    DIRECTION INOUT ;
    USE SIGNAL ;
    PORT
      LAYER METAL3 ;
        RECT 0.0 865.52 2.8 866.92 ;
    END
  END w_sub_img_out<8>
  PIN w_sub_img_out<7>
    DIRECTION INOUT ;
    USE SIGNAL ;
    PORT
      LAYER METAL3 ;
        RECT 0.0 879.52 2.8 880.92 ;
    END
  END w_sub_img_out<7>
  PIN w_sub_img_out<6>
    DIRECTION INOUT ;
    USE SIGNAL ;
    PORT
      LAYER METAL3 ;
        RECT 0.0 893.52 2.8 894.92 ;
    END
  END w_sub_img_out<6>
  PIN w_sub_img_out<5>
    DIRECTION INOUT ;
    USE SIGNAL ;
    PORT
      LAYER METAL3 ;
        RECT 0.0 907.52 2.8 908.92 ;
    END
  END w_sub_img_out<5>
  PIN w_sub_img_out<4>
    DIRECTION INOUT ;
    USE SIGNAL ;
    PORT
      LAYER METAL3 ;
        RECT 0.0 921.52 2.8 922.92 ;
    END
  END w_sub_img_out<4>
  PIN w_sub_img_out<3>
    DIRECTION INOUT ;
    USE SIGNAL ;
    PORT
      LAYER METAL3 ;
        RECT 0.0 935.52 2.8 936.92 ;
    END
  END w_sub_img_out<3>
  PIN w_sub_img_out<2>
    DIRECTION INOUT ;
    USE SIGNAL ;
    PORT
      LAYER METAL3 ;
        RECT 0.0 949.52 2.8 950.92 ;
    END
  END w_sub_img_out<2>
  PIN w_sub_img_out<1>
    DIRECTION INOUT ;
    USE SIGNAL ;
    PORT
      LAYER METAL3 ;
        RECT 0.0 963.52 2.8 964.92 ;
    END
  END w_sub_img_out<1>
  PIN w_sub_img_out<0>
    DIRECTION INOUT ;
    USE SIGNAL ;
    PORT
      LAYER METAL3 ;
        RECT 0.0 977.52 2.8 978.92 ;
    END
  END w_sub_img_out<0>
  PIN w_Vin_inp_Ch<35>
    DIRECTION INOUT ;
    USE SIGNAL ;
    PORT
      LAYER METAL3 ;
        RECT 0.0 991.52 2.8 992.92 ;
    END
  END w_Vin_inp_Ch<35>
  PIN w_Vin_inp_Ch<34>
    DIRECTION INOUT ;
    USE SIGNAL ;
    PORT
      LAYER METAL3 ;
        RECT 0.0 1005.52 2.8 1006.92 ;
    END
  END w_Vin_inp_Ch<34>
  PIN w_Vin_inp_Ch<33>
    DIRECTION INOUT ;
    USE SIGNAL ;
    PORT
      LAYER METAL3 ;
        RECT 0.0 1019.52 2.8 1020.92 ;
    END
  END w_Vin_inp_Ch<33>
  PIN w_Vin_inp_Ch<32>
    DIRECTION INOUT ;
    USE SIGNAL ;
    PORT
      LAYER METAL3 ;
        RECT 0.0 1033.52 2.8 1034.92 ;
    END
  END w_Vin_inp_Ch<32>
  PIN w_Vin_inp_Ch<31>
    DIRECTION INOUT ;
    USE SIGNAL ;
    PORT
      LAYER METAL3 ;
        RECT 0.0 1047.52 2.8 1048.92 ;
    END
  END w_Vin_inp_Ch<31>
  PIN s_sub_img_out<37>
    DIRECTION INOUT ;
    USE SIGNAL ;
    PORT
      LAYER METAL3 ;
        RECT 531.3 0.0 532.7 2.82 ;
    END
  END s_sub_img_out<37>
  PIN s_sub_img_out<36>
    DIRECTION INOUT ;
    USE SIGNAL ;
    PORT
      LAYER METAL3 ;
        RECT 517.3 0.0 518.7 2.82 ;
    END
  END s_sub_img_out<36>
  PIN s_sub_img_out<35>
    DIRECTION INOUT ;
    USE SIGNAL ;
    PORT
      LAYER METAL3 ;
        RECT 503.3 0.0 504.7 2.82 ;
    END
  END s_sub_img_out<35>
  PIN s_sub_img_out<34>
    DIRECTION INOUT ;
    USE SIGNAL ;
    PORT
      LAYER METAL3 ;
        RECT 489.3 0.0 490.7 2.82 ;
    END
  END s_sub_img_out<34>
  PIN s_sub_img_out<33>
    DIRECTION INOUT ;
    USE SIGNAL ;
    PORT
      LAYER METAL3 ;
        RECT 475.3 0.0 476.7 2.82 ;
    END
  END s_sub_img_out<33>
  PIN s_sub_img_out<32>
    DIRECTION INOUT ;
    USE SIGNAL ;
    PORT
      LAYER METAL3 ;
        RECT 461.3 0.0 462.7 2.82 ;
    END
  END s_sub_img_out<32>
  PIN s_sub_img_out<31>
    DIRECTION INOUT ;
    USE SIGNAL ;
    PORT
      LAYER METAL3 ;
        RECT 447.3 0.0 448.7 2.82 ;
    END
  END s_sub_img_out<31>
  PIN s_sub_img_out<30>
    DIRECTION INOUT ;
    USE SIGNAL ;
    PORT
      LAYER METAL3 ;
        RECT 433.3 0.0 434.7 2.82 ;
    END
  END s_sub_img_out<30>
  PIN s_sub_img_out<29>
    DIRECTION INOUT ;
    USE SIGNAL ;
    PORT
      LAYER METAL3 ;
        RECT 419.3 0.0 420.7 2.82 ;
    END
  END s_sub_img_out<29>
  PIN s_sub_img_out<28>
    DIRECTION INOUT ;
    USE SIGNAL ;
    PORT
      LAYER METAL3 ;
        RECT 405.3 0.0 406.7 2.82 ;
    END
  END s_sub_img_out<28>
  PIN s_sub_img_out<27>
    DIRECTION INOUT ;
    USE SIGNAL ;
    PORT
      LAYER METAL3 ;
        RECT 391.3 0.0 392.7 2.82 ;
    END
  END s_sub_img_out<27>
  PIN s_sub_img_out<26>
    DIRECTION INOUT ;
    USE SIGNAL ;
    PORT
      LAYER METAL3 ;
        RECT 377.3 0.0 378.7 2.82 ;
    END
  END s_sub_img_out<26>
  PIN s_sub_img_out<25>
    DIRECTION INOUT ;
    USE SIGNAL ;
    PORT
      LAYER METAL3 ;
        RECT 363.3 0.0 364.7 2.82 ;
    END
  END s_sub_img_out<25>
  PIN s_sub_img_out<24>
    DIRECTION INOUT ;
    USE SIGNAL ;
    PORT
      LAYER METAL3 ;
        RECT 349.3 0.0 350.7 2.82 ;
    END
  END s_sub_img_out<24>
  PIN s_sub_img_out<23>
    DIRECTION INOUT ;
    USE SIGNAL ;
    PORT
      LAYER METAL3 ;
        RECT 335.3 0.0 336.7 2.82 ;
    END
  END s_sub_img_out<23>
  PIN s_sub_img_out<22>
    DIRECTION INOUT ;
    USE SIGNAL ;
    PORT
      LAYER METAL3 ;
        RECT 321.3 0.0 322.7 2.82 ;
    END
  END s_sub_img_out<22>
  PIN s_sub_img_out<21>
    DIRECTION INOUT ;
    USE SIGNAL ;
    PORT
      LAYER METAL3 ;
        RECT 307.3 0.0 308.7 2.82 ;
    END
  END s_sub_img_out<21>
  PIN s_sub_img_out<20>
    DIRECTION INOUT ;
    USE SIGNAL ;
    PORT
      LAYER METAL3 ;
        RECT 293.3 0.0 294.7 2.82 ;
    END
  END s_sub_img_out<20>
  PIN s_sub_img_out<19>
    DIRECTION INOUT ;
    USE SIGNAL ;
    PORT
      LAYER METAL3 ;
        RECT 279.3 0.0 280.7 2.82 ;
    END
  END s_sub_img_out<19>
  PIN s_sub_img_out<18>
    DIRECTION INOUT ;
    USE SIGNAL ;
    PORT
      LAYER METAL3 ;
        RECT 265.3 0.0 266.7 2.82 ;
    END
  END s_sub_img_out<18>
  PIN s_sub_img_out<17>
    DIRECTION INOUT ;
    USE SIGNAL ;
    PORT
      LAYER METAL3 ;
        RECT 251.3 0.0 252.7 2.82 ;
    END
  END s_sub_img_out<17>
  PIN s_sub_img_out<16>
    DIRECTION INOUT ;
    USE SIGNAL ;
    PORT
      LAYER METAL3 ;
        RECT 237.3 0.0 238.7 2.82 ;
    END
  END s_sub_img_out<16>
  PIN s_sub_img_out<15>
    DIRECTION INOUT ;
    USE SIGNAL ;
    PORT
      LAYER METAL3 ;
        RECT 223.3 0.0 224.7 2.82 ;
    END
  END s_sub_img_out<15>
  PIN s_sub_img_out<14>
    DIRECTION INOUT ;
    USE SIGNAL ;
    PORT
      LAYER METAL3 ;
        RECT 209.3 0.0 210.7 2.82 ;
    END
  END s_sub_img_out<14>
  PIN s_sub_img_out<13>
    DIRECTION INOUT ;
    USE SIGNAL ;
    PORT
      LAYER METAL3 ;
        RECT 195.3 0.0 196.7 2.82 ;
    END
  END s_sub_img_out<13>
  PIN s_sub_img_out<12>
    DIRECTION INOUT ;
    USE SIGNAL ;
    PORT
      LAYER METAL3 ;
        RECT 181.3 0.0 182.7 2.82 ;
    END
  END s_sub_img_out<12>
  PIN s_sub_img_out<11>
    DIRECTION INOUT ;
    USE SIGNAL ;
    PORT
      LAYER METAL3 ;
        RECT 167.3 0.0 168.7 2.82 ;
    END
  END s_sub_img_out<11>
  PIN s_sub_img_out<10>
    DIRECTION INOUT ;
    USE SIGNAL ;
    PORT
      LAYER METAL3 ;
        RECT 153.3 0.0 154.7 2.82 ;
    END
  END s_sub_img_out<10>
  PIN s_sub_img_out<9>
    DIRECTION INOUT ;
    USE SIGNAL ;
    PORT
      LAYER METAL3 ;
        RECT 139.3 0.0 140.7 2.82 ;
    END
  END s_sub_img_out<9>
  PIN s_sub_img_out<8>
    DIRECTION INOUT ;
    USE SIGNAL ;
    PORT
      LAYER METAL3 ;
        RECT 125.3 0.0 126.7 2.82 ;
    END
  END s_sub_img_out<8>
  PIN s_sub_img_out<7>
    DIRECTION INOUT ;
    USE SIGNAL ;
    PORT
      LAYER METAL3 ;
        RECT 111.3 0.0 112.7 2.82 ;
    END
  END s_sub_img_out<7>
  PIN s_sub_img_out<6>
    DIRECTION INOUT ;
    USE SIGNAL ;
    PORT
      LAYER METAL3 ;
        RECT 97.3 0.0 98.7 2.82 ;
    END
  END s_sub_img_out<6>
  PIN s_sub_img_out<5>
    DIRECTION INOUT ;
    USE SIGNAL ;
    PORT
      LAYER METAL3 ;
        RECT 83.3 0.0 84.7 2.82 ;
    END
  END s_sub_img_out<5>
  PIN s_sub_img_out<4>
    DIRECTION INOUT ;
    USE SIGNAL ;
    PORT
      LAYER METAL3 ;
        RECT 69.3 0.0 70.7 2.82 ;
    END
  END s_sub_img_out<4>
  PIN s_sub_img_out<3>
    DIRECTION INOUT ;
    USE SIGNAL ;
    PORT
      LAYER METAL3 ;
        RECT 55.3 0.0 56.7 2.82 ;
    END
  END s_sub_img_out<3>
  PIN s_sub_img_out<2>
    DIRECTION INOUT ;
    USE SIGNAL ;
    PORT
      LAYER METAL3 ;
        RECT 41.3 0.0 42.7 2.82 ;
    END
  END s_sub_img_out<2>
  PIN s_sub_img_out<1>
    DIRECTION INOUT ;
    USE SIGNAL ;
    PORT
      LAYER METAL3 ;
        RECT 27.3 0.0 28.7 2.82 ;
    END
  END s_sub_img_out<1>
  PIN s_sub_img_out<0>
    DIRECTION INOUT ;
    USE SIGNAL ;
    PORT
      LAYER METAL3 ;
        RECT 13.3 0.0 14.7 2.82 ;
    END
  END s_sub_img_out<0>
  PIN w_sub_img_out<19>
    DIRECTION INOUT ;
    USE SIGNAL ;
    PORT
      LAYER METAL3 ;
        RECT 0.0 711.52 2.8 712.92 ;
    END
  END w_sub_img_out<19>
  PIN w_sub_img_out<18>
    DIRECTION INOUT ;
    USE SIGNAL ;
    PORT
      LAYER METAL3 ;
        RECT 0.0 725.52 2.8 726.92 ;
    END
  END w_sub_img_out<18>
  PIN w_sub_img_out<17>
    DIRECTION INOUT ;
    USE SIGNAL ;
    PORT
      LAYER METAL3 ;
        RECT 0.0 739.52 2.8 740.92 ;
    END
  END w_sub_img_out<17>
  PIN w_sub_img_out<16>
    DIRECTION INOUT ;
    USE SIGNAL ;
    PORT
      LAYER METAL3 ;
        RECT 0.0 753.52 2.8 754.92 ;
    END
  END w_sub_img_out<16>
  PIN w_sub_img_out<29>
    DIRECTION INOUT ;
    USE SIGNAL ;
    PORT
      LAYER METAL3 ;
        RECT 0.0 571.52 2.8 572.92 ;
    END
  END w_sub_img_out<29>
  PIN w_sub_img_out<28>
    DIRECTION INOUT ;
    USE SIGNAL ;
    PORT
      LAYER METAL3 ;
        RECT 0.0 585.52 2.8 586.92 ;
    END
  END w_sub_img_out<28>
  PIN w_sub_img_out<27>
    DIRECTION INOUT ;
    USE SIGNAL ;
    PORT
      LAYER METAL3 ;
        RECT 0.0 599.52 2.8 600.92 ;
    END
  END w_sub_img_out<27>
  PIN w_sub_img_out<26>
    DIRECTION INOUT ;
    USE SIGNAL ;
    PORT
      LAYER METAL3 ;
        RECT 0.0 613.52 2.8 614.92 ;
    END
  END w_sub_img_out<26>
  PIN w_sub_img_out<25>
    DIRECTION INOUT ;
    USE SIGNAL ;
    PORT
      LAYER METAL3 ;
        RECT 0.0 627.52 2.8 628.92 ;
    END
  END w_sub_img_out<25>
  PIN w_sub_img_out<24>
    DIRECTION INOUT ;
    USE SIGNAL ;
    PORT
      LAYER METAL3 ;
        RECT 0.0 641.52 2.8 642.92 ;
    END
  END w_sub_img_out<24>
  PIN w_sub_img_out<23>
    DIRECTION INOUT ;
    USE SIGNAL ;
    PORT
      LAYER METAL3 ;
        RECT 0.0 655.52 2.8 656.92 ;
    END
  END w_sub_img_out<23>
  PIN w_sub_img_out<22>
    DIRECTION INOUT ;
    USE SIGNAL ;
    PORT
      LAYER METAL3 ;
        RECT 0.0 669.52 2.8 670.92 ;
    END
  END w_sub_img_out<22>
  PIN w_sub_img_out<21>
    DIRECTION INOUT ;
    USE SIGNAL ;
    PORT
      LAYER METAL3 ;
        RECT 0.0 683.52 2.8 684.92 ;
    END
  END w_sub_img_out<21>
  PIN w_sub_img_out<20>
    DIRECTION INOUT ;
    USE SIGNAL ;
    PORT
      LAYER METAL3 ;
        RECT 0.0 697.52 2.8 698.92 ;
    END
  END w_sub_img_out<20>
  PIN s_sub_img_out<76>
    DIRECTION INOUT ;
    USE SIGNAL ;
    PORT
      LAYER METAL3 ;
        RECT 1077.3 0.0 1078.7 2.82 ;
    END
  END s_sub_img_out<76>
  PIN s_sub_img_out<75>
    DIRECTION INOUT ;
    USE SIGNAL ;
    PORT
      LAYER METAL3 ;
        RECT 1063.3 0.0 1064.7 2.82 ;
    END
  END s_sub_img_out<75>
  PIN s_sub_img_out<74>
    DIRECTION INOUT ;
    USE SIGNAL ;
    PORT
      LAYER METAL3 ;
        RECT 1049.3 0.0 1050.7 2.82 ;
    END
  END s_sub_img_out<74>
  PIN s_sub_img_out<73>
    DIRECTION INOUT ;
    USE SIGNAL ;
    PORT
      LAYER METAL3 ;
        RECT 1035.3 0.0 1036.7 2.82 ;
    END
  END s_sub_img_out<73>
  PIN s_sub_img_out<72>
    DIRECTION INOUT ;
    USE SIGNAL ;
    PORT
      LAYER METAL3 ;
        RECT 1021.3 0.0 1022.7 2.82 ;
    END
  END s_sub_img_out<72>
  PIN s_sub_img_out<71>
    DIRECTION INOUT ;
    USE SIGNAL ;
    PORT
      LAYER METAL3 ;
        RECT 1007.3 0.0 1008.7 2.82 ;
    END
  END s_sub_img_out<71>
  PIN s_sub_img_out<70>
    DIRECTION INOUT ;
    USE SIGNAL ;
    PORT
      LAYER METAL3 ;
        RECT 993.3 0.0 994.7 2.82 ;
    END
  END s_sub_img_out<70>
  PIN s_sub_img_out<69>
    DIRECTION INOUT ;
    USE SIGNAL ;
    PORT
      LAYER METAL3 ;
        RECT 979.3 0.0 980.7 2.82 ;
    END
  END s_sub_img_out<69>
  PIN s_sub_img_out<68>
    DIRECTION INOUT ;
    USE SIGNAL ;
    PORT
      LAYER METAL3 ;
        RECT 965.3 0.0 966.7 2.82 ;
    END
  END s_sub_img_out<68>
  PIN s_sub_img_out<67>
    DIRECTION INOUT ;
    USE SIGNAL ;
    PORT
      LAYER METAL3 ;
        RECT 951.3 0.0 952.7 2.82 ;
    END
  END s_sub_img_out<67>
  PIN s_sub_img_out<66>
    DIRECTION INOUT ;
    USE SIGNAL ;
    PORT
      LAYER METAL3 ;
        RECT 937.3 0.0 938.7 2.82 ;
    END
  END s_sub_img_out<66>
  PIN s_sub_img_out<65>
    DIRECTION INOUT ;
    USE SIGNAL ;
    PORT
      LAYER METAL3 ;
        RECT 923.3 0.0 924.7 2.82 ;
    END
  END s_sub_img_out<65>
  PIN s_sub_img_out<64>
    DIRECTION INOUT ;
    USE SIGNAL ;
    PORT
      LAYER METAL3 ;
        RECT 909.3 0.0 910.7 2.82 ;
    END
  END s_sub_img_out<64>
  PIN s_sub_img_out<63>
    DIRECTION INOUT ;
    USE SIGNAL ;
    PORT
      LAYER METAL3 ;
        RECT 895.3 0.0 896.7 2.82 ;
    END
  END s_sub_img_out<63>
  PIN s_sub_img_out<62>
    DIRECTION INOUT ;
    USE SIGNAL ;
    PORT
      LAYER METAL3 ;
        RECT 881.3 0.0 882.7 2.82 ;
    END
  END s_sub_img_out<62>
  PIN s_sub_img_out<61>
    DIRECTION INOUT ;
    USE SIGNAL ;
    PORT
      LAYER METAL3 ;
        RECT 867.3 0.0 868.7 2.82 ;
    END
  END s_sub_img_out<61>
  PIN s_sub_img_out<60>
    DIRECTION INOUT ;
    USE SIGNAL ;
    PORT
      LAYER METAL3 ;
        RECT 853.3 0.0 854.7 2.82 ;
    END
  END s_sub_img_out<60>
  PIN s_sub_img_out<59>
    DIRECTION INOUT ;
    USE SIGNAL ;
    PORT
      LAYER METAL3 ;
        RECT 839.3 0.0 840.7 2.82 ;
    END
  END s_sub_img_out<59>
  PIN s_sub_img_out<58>
    DIRECTION INOUT ;
    USE SIGNAL ;
    PORT
      LAYER METAL3 ;
        RECT 825.3 0.0 826.7 2.82 ;
    END
  END s_sub_img_out<58>
  PIN s_sub_img_out<57>
    DIRECTION INOUT ;
    USE SIGNAL ;
    PORT
      LAYER METAL3 ;
        RECT 811.3 0.0 812.7 2.82 ;
    END
  END s_sub_img_out<57>
  PIN s_sub_img_out<56>
    DIRECTION INOUT ;
    USE SIGNAL ;
    PORT
      LAYER METAL3 ;
        RECT 797.3 0.0 798.7 2.82 ;
    END
  END s_sub_img_out<56>
  PIN s_sub_img_out<55>
    DIRECTION INOUT ;
    USE SIGNAL ;
    PORT
      LAYER METAL3 ;
        RECT 783.3 0.0 784.7 2.82 ;
    END
  END s_sub_img_out<55>
  PIN s_sub_img_out<54>
    DIRECTION INOUT ;
    USE SIGNAL ;
    PORT
      LAYER METAL3 ;
        RECT 769.3 0.0 770.7 2.82 ;
    END
  END s_sub_img_out<54>
  PIN s_sub_img_out<53>
    DIRECTION INOUT ;
    USE SIGNAL ;
    PORT
      LAYER METAL3 ;
        RECT 755.3 0.0 756.7 2.82 ;
    END
  END s_sub_img_out<53>
  PIN s_sub_img_out<52>
    DIRECTION INOUT ;
    USE SIGNAL ;
    PORT
      LAYER METAL3 ;
        RECT 741.3 0.0 742.7 2.82 ;
    END
  END s_sub_img_out<52>
  PIN s_sub_img_out<51>
    DIRECTION INOUT ;
    USE SIGNAL ;
    PORT
      LAYER METAL3 ;
        RECT 727.3 0.0 728.7 2.82 ;
    END
  END s_sub_img_out<51>
  PIN s_sub_img_out<50>
    DIRECTION INOUT ;
    USE SIGNAL ;
    PORT
      LAYER METAL3 ;
        RECT 713.3 0.0 714.7 2.82 ;
    END
  END s_sub_img_out<50>
  PIN s_sub_img_out<49>
    DIRECTION INOUT ;
    USE SIGNAL ;
    PORT
      LAYER METAL3 ;
        RECT 699.3 0.0 700.7 2.82 ;
    END
  END s_sub_img_out<49>
  PIN s_sub_img_out<48>
    DIRECTION INOUT ;
    USE SIGNAL ;
    PORT
      LAYER METAL3 ;
        RECT 685.3 0.0 686.7 2.82 ;
    END
  END s_sub_img_out<48>
  PIN s_sub_img_out<47>
    DIRECTION INOUT ;
    USE SIGNAL ;
    PORT
      LAYER METAL3 ;
        RECT 671.3 0.0 672.7 2.82 ;
    END
  END s_sub_img_out<47>
  PIN s_sub_img_out<46>
    DIRECTION INOUT ;
    USE SIGNAL ;
    PORT
      LAYER METAL3 ;
        RECT 657.3 0.0 658.7 2.82 ;
    END
  END s_sub_img_out<46>
  PIN s_sub_img_out<45>
    DIRECTION INOUT ;
    USE SIGNAL ;
    PORT
      LAYER METAL3 ;
        RECT 643.3 0.0 644.7 2.82 ;
    END
  END s_sub_img_out<45>
  PIN s_sub_img_out<44>
    DIRECTION INOUT ;
    USE SIGNAL ;
    PORT
      LAYER METAL3 ;
        RECT 629.3 0.0 630.7 2.82 ;
    END
  END s_sub_img_out<44>
  PIN s_sub_img_out<43>
    DIRECTION INOUT ;
    USE SIGNAL ;
    PORT
      LAYER METAL3 ;
        RECT 615.3 0.0 616.7 2.82 ;
    END
  END s_sub_img_out<43>
  PIN s_sub_img_out<42>
    DIRECTION INOUT ;
    USE SIGNAL ;
    PORT
      LAYER METAL3 ;
        RECT 601.3 0.0 602.7 2.82 ;
    END
  END s_sub_img_out<42>
  PIN s_sub_img_out<41>
    DIRECTION INOUT ;
    USE SIGNAL ;
    PORT
      LAYER METAL3 ;
        RECT 587.3 0.0 588.7 2.82 ;
    END
  END s_sub_img_out<41>
  PIN s_sub_img_out<40>
    DIRECTION INOUT ;
    USE SIGNAL ;
    PORT
      LAYER METAL3 ;
        RECT 573.3 0.0 574.7 2.82 ;
    END
  END s_sub_img_out<40>
  PIN s_sub_img_out<39>
    DIRECTION INOUT ;
    USE SIGNAL ;
    PORT
      LAYER METAL3 ;
        RECT 559.3 0.0 560.7 2.82 ;
    END
  END s_sub_img_out<39>
  PIN s_sub_img_out<38>
    DIRECTION INOUT ;
    USE SIGNAL ;
    PORT
      LAYER METAL3 ;
        RECT 545.3 0.0 546.7 2.82 ;
    END
  END s_sub_img_out<38>
  PIN s_sub_img_out<100>
    DIRECTION INOUT ;
    USE SIGNAL ;
    PORT
      LAYER METAL3 ;
        RECT 1413.3 0.0 1414.7 2.82 ;
    END
  END s_sub_img_out<100>
  PIN s_sub_img_out<99>
    DIRECTION INOUT ;
    USE SIGNAL ;
    PORT
      LAYER METAL3 ;
        RECT 1399.3 0.0 1400.7 2.82 ;
    END
  END s_sub_img_out<99>
  PIN s_sub_img_out<98>
    DIRECTION INOUT ;
    USE SIGNAL ;
    PORT
      LAYER METAL3 ;
        RECT 1385.3 0.0 1386.7 2.82 ;
    END
  END s_sub_img_out<98>
  PIN s_sub_img_out<97>
    DIRECTION INOUT ;
    USE SIGNAL ;
    PORT
      LAYER METAL3 ;
        RECT 1371.3 0.0 1372.7 2.82 ;
    END
  END s_sub_img_out<97>
  PIN s_sub_img_out<96>
    DIRECTION INOUT ;
    USE SIGNAL ;
    PORT
      LAYER METAL3 ;
        RECT 1357.3 0.0 1358.7 2.82 ;
    END
  END s_sub_img_out<96>
  PIN s_sub_img_out<95>
    DIRECTION INOUT ;
    USE SIGNAL ;
    PORT
      LAYER METAL3 ;
        RECT 1343.3 0.0 1344.7 2.82 ;
    END
  END s_sub_img_out<95>
  PIN s_sub_img_out<94>
    DIRECTION INOUT ;
    USE SIGNAL ;
    PORT
      LAYER METAL3 ;
        RECT 1329.3 0.0 1330.7 2.82 ;
    END
  END s_sub_img_out<94>
  PIN s_sub_img_out<93>
    DIRECTION INOUT ;
    USE SIGNAL ;
    PORT
      LAYER METAL3 ;
        RECT 1315.3 0.0 1316.7 2.82 ;
    END
  END s_sub_img_out<93>
  PIN s_sub_img_out<92>
    DIRECTION INOUT ;
    USE SIGNAL ;
    PORT
      LAYER METAL3 ;
        RECT 1301.3 0.0 1302.7 2.82 ;
    END
  END s_sub_img_out<92>
  PIN s_sub_img_out<91>
    DIRECTION INOUT ;
    USE SIGNAL ;
    PORT
      LAYER METAL3 ;
        RECT 1287.3 0.0 1288.7 2.82 ;
    END
  END s_sub_img_out<91>
  PIN s_sub_img_out<90>
    DIRECTION INOUT ;
    USE SIGNAL ;
    PORT
      LAYER METAL3 ;
        RECT 1273.3 0.0 1274.7 2.82 ;
    END
  END s_sub_img_out<90>
  PIN s_sub_img_out<89>
    DIRECTION INOUT ;
    USE SIGNAL ;
    PORT
      LAYER METAL3 ;
        RECT 1259.3 0.0 1260.7 2.82 ;
    END
  END s_sub_img_out<89>
  PIN s_sub_img_out<88>
    DIRECTION INOUT ;
    USE SIGNAL ;
    PORT
      LAYER METAL3 ;
        RECT 1245.3 0.0 1246.7 2.82 ;
    END
  END s_sub_img_out<88>
  PIN s_sub_img_out<87>
    DIRECTION INOUT ;
    USE SIGNAL ;
    PORT
      LAYER METAL3 ;
        RECT 1231.3 0.0 1232.7 2.82 ;
    END
  END s_sub_img_out<87>
  PIN s_sub_img_out<86>
    DIRECTION INOUT ;
    USE SIGNAL ;
    PORT
      LAYER METAL3 ;
        RECT 1217.3 0.0 1218.7 2.82 ;
    END
  END s_sub_img_out<86>
  PIN s_sub_img_out<85>
    DIRECTION INOUT ;
    USE SIGNAL ;
    PORT
      LAYER METAL3 ;
        RECT 1203.3 0.0 1204.7 2.82 ;
    END
  END s_sub_img_out<85>
  PIN s_sub_img_out<84>
    DIRECTION INOUT ;
    USE SIGNAL ;
    PORT
      LAYER METAL3 ;
        RECT 1189.3 0.0 1190.7 2.82 ;
    END
  END s_sub_img_out<84>
  PIN s_sub_img_out<83>
    DIRECTION INOUT ;
    USE SIGNAL ;
    PORT
      LAYER METAL3 ;
        RECT 1175.3 0.0 1176.7 2.82 ;
    END
  END s_sub_img_out<83>
  PIN s_sub_img_out<82>
    DIRECTION INOUT ;
    USE SIGNAL ;
    PORT
      LAYER METAL3 ;
        RECT 1161.3 0.0 1162.7 2.82 ;
    END
  END s_sub_img_out<82>
  PIN s_sub_img_out<81>
    DIRECTION INOUT ;
    USE SIGNAL ;
    PORT
      LAYER METAL3 ;
        RECT 1147.3 0.0 1148.7 2.82 ;
    END
  END s_sub_img_out<81>
  PIN s_sub_img_out<80>
    DIRECTION INOUT ;
    USE SIGNAL ;
    PORT
      LAYER METAL3 ;
        RECT 1133.3 0.0 1134.7 2.82 ;
    END
  END s_sub_img_out<80>
  PIN s_sub_img_out<79>
    DIRECTION INOUT ;
    USE SIGNAL ;
    PORT
      LAYER METAL3 ;
        RECT 1119.3 0.0 1120.7 2.82 ;
    END
  END s_sub_img_out<79>
  PIN s_sub_img_out<78>
    DIRECTION INOUT ;
    USE SIGNAL ;
    PORT
      LAYER METAL3 ;
        RECT 1105.3 0.0 1106.7 2.82 ;
    END
  END s_sub_img_out<78>
  PIN s_sub_img_out<77>
    DIRECTION INOUT ;
    USE SIGNAL ;
    PORT
      LAYER METAL3 ;
        RECT 1091.3 0.0 1092.7 2.82 ;
    END
  END s_sub_img_out<77>
  PIN s_sub_img_out<153>
    DIRECTION INOUT ;
    USE SIGNAL ;
    PORT
      LAYER METAL3 ;
        RECT 2155.3 0.0 2156.7 2.82 ;
    END
  END s_sub_img_out<153>
  PIN s_sub_img_out<152>
    DIRECTION INOUT ;
    USE SIGNAL ;
    PORT
      LAYER METAL3 ;
        RECT 2141.3 0.0 2142.7 2.82 ;
    END
  END s_sub_img_out<152>
  PIN s_sub_img_out<151>
    DIRECTION INOUT ;
    USE SIGNAL ;
    PORT
      LAYER METAL3 ;
        RECT 2127.3 0.0 2128.7 2.82 ;
    END
  END s_sub_img_out<151>
  PIN s_sub_img_out<150>
    DIRECTION INOUT ;
    USE SIGNAL ;
    PORT
      LAYER METAL3 ;
        RECT 2113.3 0.0 2114.7 2.82 ;
    END
  END s_sub_img_out<150>
  PIN s_sub_img_out<149>
    DIRECTION INOUT ;
    USE SIGNAL ;
    PORT
      LAYER METAL3 ;
        RECT 2099.3 0.0 2100.7 2.82 ;
    END
  END s_sub_img_out<149>
  PIN s_sub_img_out<148>
    DIRECTION INOUT ;
    USE SIGNAL ;
    PORT
      LAYER METAL3 ;
        RECT 2085.3 0.0 2086.7 2.82 ;
    END
  END s_sub_img_out<148>
  PIN s_sub_img_out<147>
    DIRECTION INOUT ;
    USE SIGNAL ;
    PORT
      LAYER METAL3 ;
        RECT 2071.3 0.0 2072.7 2.82 ;
    END
  END s_sub_img_out<147>
  PIN s_sub_img_out<146>
    DIRECTION INOUT ;
    USE SIGNAL ;
    PORT
      LAYER METAL3 ;
        RECT 2057.3 0.0 2058.7 2.82 ;
    END
  END s_sub_img_out<146>
  PIN s_sub_img_out<145>
    DIRECTION INOUT ;
    USE SIGNAL ;
    PORT
      LAYER METAL3 ;
        RECT 2043.3 0.0 2044.7 2.82 ;
    END
  END s_sub_img_out<145>
  PIN s_sub_img_out<144>
    DIRECTION INOUT ;
    USE SIGNAL ;
    PORT
      LAYER METAL3 ;
        RECT 2029.3 0.0 2030.7 2.82 ;
    END
  END s_sub_img_out<144>
  PIN s_sub_img_out<143>
    DIRECTION INOUT ;
    USE SIGNAL ;
    PORT
      LAYER METAL3 ;
        RECT 2015.3 0.0 2016.7 2.82 ;
    END
  END s_sub_img_out<143>
  PIN s_sub_img_out<142>
    DIRECTION INOUT ;
    USE SIGNAL ;
    PORT
      LAYER METAL3 ;
        RECT 2001.3 0.0 2002.7 2.82 ;
    END
  END s_sub_img_out<142>
  PIN s_sub_img_out<141>
    DIRECTION INOUT ;
    USE SIGNAL ;
    PORT
      LAYER METAL3 ;
        RECT 1987.3 0.0 1988.7 2.82 ;
    END
  END s_sub_img_out<141>
  PIN s_sub_img_out<140>
    DIRECTION INOUT ;
    USE SIGNAL ;
    PORT
      LAYER METAL3 ;
        RECT 1973.3 0.0 1974.7 2.82 ;
    END
  END s_sub_img_out<140>
  PIN s_sub_img_out<139>
    DIRECTION INOUT ;
    USE SIGNAL ;
    PORT
      LAYER METAL3 ;
        RECT 1959.3 0.0 1960.7 2.82 ;
    END
  END s_sub_img_out<139>
  PIN s_sub_img_out<138>
    DIRECTION INOUT ;
    USE SIGNAL ;
    PORT
      LAYER METAL3 ;
        RECT 1945.3 0.0 1946.7 2.82 ;
    END
  END s_sub_img_out<138>
  PIN s_sub_img_out<137>
    DIRECTION INOUT ;
    USE SIGNAL ;
    PORT
      LAYER METAL3 ;
        RECT 1931.3 0.0 1932.7 2.82 ;
    END
  END s_sub_img_out<137>
  PIN s_sub_img_out<136>
    DIRECTION INOUT ;
    USE SIGNAL ;
    PORT
      LAYER METAL3 ;
        RECT 1917.3 0.0 1918.7 2.82 ;
    END
  END s_sub_img_out<136>
  PIN s_sub_img_out<135>
    DIRECTION INOUT ;
    USE SIGNAL ;
    PORT
      LAYER METAL3 ;
        RECT 1903.3 0.0 1904.7 2.82 ;
    END
  END s_sub_img_out<135>
  PIN s_sub_img_out<134>
    DIRECTION INOUT ;
    USE SIGNAL ;
    PORT
      LAYER METAL3 ;
        RECT 1889.3 0.0 1890.7 2.82 ;
    END
  END s_sub_img_out<134>
  PIN s_sub_img_out<133>
    DIRECTION INOUT ;
    USE SIGNAL ;
    PORT
      LAYER METAL3 ;
        RECT 1875.3 0.0 1876.7 2.82 ;
    END
  END s_sub_img_out<133>
  PIN s_sub_img_out<132>
    DIRECTION INOUT ;
    USE SIGNAL ;
    PORT
      LAYER METAL3 ;
        RECT 1861.3 0.0 1862.7 2.82 ;
    END
  END s_sub_img_out<132>
  PIN s_sub_img_out<131>
    DIRECTION INOUT ;
    USE SIGNAL ;
    PORT
      LAYER METAL3 ;
        RECT 1847.3 0.0 1848.7 2.82 ;
    END
  END s_sub_img_out<131>
  PIN s_sub_img_out<130>
    DIRECTION INOUT ;
    USE SIGNAL ;
    PORT
      LAYER METAL3 ;
        RECT 1833.3 0.0 1834.7 2.82 ;
    END
  END s_sub_img_out<130>
  PIN s_sub_img_out<129>
    DIRECTION INOUT ;
    USE SIGNAL ;
    PORT
      LAYER METAL3 ;
        RECT 1819.3 0.0 1820.7 2.82 ;
    END
  END s_sub_img_out<129>
  PIN s_sub_img_out<128>
    DIRECTION INOUT ;
    USE SIGNAL ;
    PORT
      LAYER METAL3 ;
        RECT 1805.3 0.0 1806.7 2.82 ;
    END
  END s_sub_img_out<128>
  PIN s_sub_img_out<127>
    DIRECTION INOUT ;
    USE SIGNAL ;
    PORT
      LAYER METAL3 ;
        RECT 1791.3 0.0 1792.7 2.82 ;
    END
  END s_sub_img_out<127>
  PIN s_sub_img_out<126>
    DIRECTION INOUT ;
    USE SIGNAL ;
    PORT
      LAYER METAL3 ;
        RECT 1777.3 0.0 1778.7 2.82 ;
    END
  END s_sub_img_out<126>
  PIN s_sub_img_out<125>
    DIRECTION INOUT ;
    USE SIGNAL ;
    PORT
      LAYER METAL3 ;
        RECT 1763.3 0.0 1764.7 2.82 ;
    END
  END s_sub_img_out<125>
  PIN s_sub_img_out<124>
    DIRECTION INOUT ;
    USE SIGNAL ;
    PORT
      LAYER METAL3 ;
        RECT 1749.3 0.0 1750.7 2.82 ;
    END
  END s_sub_img_out<124>
  PIN s_sub_img_out<123>
    DIRECTION INOUT ;
    USE SIGNAL ;
    PORT
      LAYER METAL3 ;
        RECT 1735.3 0.0 1736.7 2.82 ;
    END
  END s_sub_img_out<123>
  PIN s_sub_img_out<122>
    DIRECTION INOUT ;
    USE SIGNAL ;
    PORT
      LAYER METAL3 ;
        RECT 1721.3 0.0 1722.7 2.82 ;
    END
  END s_sub_img_out<122>
  PIN s_sub_img_out<121>
    DIRECTION INOUT ;
    USE SIGNAL ;
    PORT
      LAYER METAL3 ;
        RECT 1707.3 0.0 1708.7 2.82 ;
    END
  END s_sub_img_out<121>
  PIN s_sub_img_out<120>
    DIRECTION INOUT ;
    USE SIGNAL ;
    PORT
      LAYER METAL3 ;
        RECT 1693.3 0.0 1694.7 2.82 ;
    END
  END s_sub_img_out<120>
  PIN s_sub_img_out<119>
    DIRECTION INOUT ;
    USE SIGNAL ;
    PORT
      LAYER METAL3 ;
        RECT 1679.3 0.0 1680.7 2.82 ;
    END
  END s_sub_img_out<119>
  PIN s_sub_img_out<118>
    DIRECTION INOUT ;
    USE SIGNAL ;
    PORT
      LAYER METAL3 ;
        RECT 1665.3 0.0 1666.7 2.82 ;
    END
  END s_sub_img_out<118>
  PIN s_sub_img_out<117>
    DIRECTION INOUT ;
    USE SIGNAL ;
    PORT
      LAYER METAL3 ;
        RECT 1651.3 0.0 1652.7 2.82 ;
    END
  END s_sub_img_out<117>
  PIN s_sub_img_out<116>
    DIRECTION INOUT ;
    USE SIGNAL ;
    PORT
      LAYER METAL3 ;
        RECT 1637.3 0.0 1638.7 2.82 ;
    END
  END s_sub_img_out<116>
  PIN s_sub_img_out<115>
    DIRECTION INOUT ;
    USE SIGNAL ;
    PORT
      LAYER METAL3 ;
        RECT 1623.3 0.0 1624.7 2.82 ;
    END
  END s_sub_img_out<115>
  PIN s_sub_img_out<114>
    DIRECTION INOUT ;
    USE SIGNAL ;
    PORT
      LAYER METAL3 ;
        RECT 1609.3 0.0 1610.7 2.82 ;
    END
  END s_sub_img_out<114>
  PIN s_sub_img_out<113>
    DIRECTION INOUT ;
    USE SIGNAL ;
    PORT
      LAYER METAL3 ;
        RECT 1595.3 0.0 1596.7 2.82 ;
    END
  END s_sub_img_out<113>
  PIN s_sub_img_out<112>
    DIRECTION INOUT ;
    USE SIGNAL ;
    PORT
      LAYER METAL3 ;
        RECT 1581.3 0.0 1582.7 2.82 ;
    END
  END s_sub_img_out<112>
  PIN s_sub_img_out<111>
    DIRECTION INOUT ;
    USE SIGNAL ;
    PORT
      LAYER METAL3 ;
        RECT 1567.3 0.0 1568.7 2.82 ;
    END
  END s_sub_img_out<111>
  PIN s_sub_img_out<110>
    DIRECTION INOUT ;
    USE SIGNAL ;
    PORT
      LAYER METAL3 ;
        RECT 1553.3 0.0 1554.7 2.82 ;
    END
  END s_sub_img_out<110>
  PIN s_sub_img_out<109>
    DIRECTION INOUT ;
    USE SIGNAL ;
    PORT
      LAYER METAL3 ;
        RECT 1539.3 0.0 1540.7 2.82 ;
    END
  END s_sub_img_out<109>
  PIN s_sub_img_out<108>
    DIRECTION INOUT ;
    USE SIGNAL ;
    PORT
      LAYER METAL3 ;
        RECT 1525.3 0.0 1526.7 2.82 ;
    END
  END s_sub_img_out<108>
  PIN s_sub_img_out<107>
    DIRECTION INOUT ;
    USE SIGNAL ;
    PORT
      LAYER METAL3 ;
        RECT 1511.3 0.0 1512.7 2.82 ;
    END
  END s_sub_img_out<107>
  PIN s_sub_img_out<106>
    DIRECTION INOUT ;
    USE SIGNAL ;
    PORT
      LAYER METAL3 ;
        RECT 1497.3 0.0 1498.7 2.82 ;
    END
  END s_sub_img_out<106>
  PIN s_sub_img_out<105>
    DIRECTION INOUT ;
    USE SIGNAL ;
    PORT
      LAYER METAL3 ;
        RECT 1483.3 0.0 1484.7 2.82 ;
    END
  END s_sub_img_out<105>
  PIN s_sub_img_out<104>
    DIRECTION INOUT ;
    USE SIGNAL ;
    PORT
      LAYER METAL3 ;
        RECT 1469.3 0.0 1470.7 2.82 ;
    END
  END s_sub_img_out<104>
  PIN s_sub_img_out<103>
    DIRECTION INOUT ;
    USE SIGNAL ;
    PORT
      LAYER METAL3 ;
        RECT 1455.3 0.0 1456.7 2.82 ;
    END
  END s_sub_img_out<103>
  PIN s_sub_img_out<102>
    DIRECTION INOUT ;
    USE SIGNAL ;
    PORT
      LAYER METAL3 ;
        RECT 1441.3 0.0 1442.7 2.82 ;
    END
  END s_sub_img_out<102>
  PIN s_sub_img_out<101>
    DIRECTION INOUT ;
    USE SIGNAL ;
    PORT
      LAYER METAL3 ;
        RECT 1427.3 0.0 1428.7 2.82 ;
    END
  END s_sub_img_out<101>
END ConvNN

MACRO FullyCon_NN
  PIN n_FNN_shr_Dr_bit<7>
    DIRECTION INOUT ;
    USE SIGNAL ;
    PORT
      LAYER METAL3 ;
        RECT 5189.36 1609.9 5190.76 1612.24 ;
    END
  END n_FNN_shr_Dr_bit<7>
  PIN n_FNN_input<63>
    DIRECTION INOUT ;
    USE SIGNAL ;
    PORT
      LAYER METAL3 ;
        RECT 4201.9 1609.9 4203.3 1612.24 ;
    END
  END n_FNN_input<63>
  PIN n_FNN_input<62>
    DIRECTION INOUT ;
    USE SIGNAL ;
    PORT
      LAYER METAL3 ;
        RECT 4215.9 1609.9 4217.3 1612.24 ;
    END
  END n_FNN_input<62>
  PIN n_FNN_input<61>
    DIRECTION INOUT ;
    USE SIGNAL ;
    PORT
      LAYER METAL3 ;
        RECT 4229.9 1609.9 4231.3 1612.24 ;
    END
  END n_FNN_input<61>
  PIN n_FNN_input<60>
    DIRECTION INOUT ;
    USE SIGNAL ;
    PORT
      LAYER METAL3 ;
        RECT 4243.9 1609.9 4245.3 1612.24 ;
    END
  END n_FNN_input<60>
  PIN n_FNN_input<59>
    DIRECTION INOUT ;
    USE SIGNAL ;
    PORT
      LAYER METAL3 ;
        RECT 4257.9 1609.9 4259.3 1612.24 ;
    END
  END n_FNN_input<59>
  PIN n_FNN_input<58>
    DIRECTION INOUT ;
    USE SIGNAL ;
    PORT
      LAYER METAL3 ;
        RECT 4271.9 1609.9 4273.3 1612.24 ;
    END
  END n_FNN_input<58>
  PIN n_FNN_input<57>
    DIRECTION INOUT ;
    USE SIGNAL ;
    PORT
      LAYER METAL3 ;
        RECT 4285.9 1609.9 4287.3 1612.24 ;
    END
  END n_FNN_input<57>
  PIN n_FNN_input<56>
    DIRECTION INOUT ;
    USE SIGNAL ;
    PORT
      LAYER METAL3 ;
        RECT 4299.9 1609.9 4301.3 1612.24 ;
    END
  END n_FNN_input<56>
  PIN n_FNN_input<55>
    DIRECTION INOUT ;
    USE SIGNAL ;
    PORT
      LAYER METAL3 ;
        RECT 4313.9 1609.9 4315.3 1612.24 ;
    END
  END n_FNN_input<55>
  PIN n_FNN_input<54>
    DIRECTION INOUT ;
    USE SIGNAL ;
    PORT
      LAYER METAL3 ;
        RECT 4327.9 1609.9 4329.3 1612.24 ;
    END
  END n_FNN_input<54>
  PIN n_FNN_input<53>
    DIRECTION INOUT ;
    USE SIGNAL ;
    PORT
      LAYER METAL3 ;
        RECT 4341.9 1609.9 4343.3 1612.24 ;
    END
  END n_FNN_input<53>
  PIN n_FNN_input<52>
    DIRECTION INOUT ;
    USE SIGNAL ;
    PORT
      LAYER METAL3 ;
        RECT 4355.9 1609.9 4357.3 1612.24 ;
    END
  END n_FNN_input<52>
  PIN n_FNN_input<51>
    DIRECTION INOUT ;
    USE SIGNAL ;
    PORT
      LAYER METAL3 ;
        RECT 4369.9 1609.9 4371.3 1612.24 ;
    END
  END n_FNN_input<51>
  PIN n_FNN_input<50>
    DIRECTION INOUT ;
    USE SIGNAL ;
    PORT
      LAYER METAL3 ;
        RECT 4383.9 1609.9 4385.3 1612.24 ;
    END
  END n_FNN_input<50>
  PIN n_FNN_input<49>
    DIRECTION INOUT ;
    USE SIGNAL ;
    PORT
      LAYER METAL3 ;
        RECT 4397.9 1609.9 4399.3 1612.24 ;
    END
  END n_FNN_input<49>
  PIN n_FNN_input<48>
    DIRECTION INOUT ;
    USE SIGNAL ;
    PORT
      LAYER METAL3 ;
        RECT 4411.9 1609.9 4413.3 1612.24 ;
    END
  END n_FNN_input<48>
  PIN n_FNN_input<47>
    DIRECTION INOUT ;
    USE SIGNAL ;
    PORT
      LAYER METAL3 ;
        RECT 4425.9 1609.9 4427.3 1612.24 ;
    END
  END n_FNN_input<47>
  PIN n_FNN_input<46>
    DIRECTION INOUT ;
    USE SIGNAL ;
    PORT
      LAYER METAL3 ;
        RECT 4439.9 1609.9 4441.3 1612.24 ;
    END
  END n_FNN_input<46>
  PIN n_FNN_input<45>
    DIRECTION INOUT ;
    USE SIGNAL ;
    PORT
      LAYER METAL3 ;
        RECT 4453.9 1609.9 4455.3 1612.24 ;
    END
  END n_FNN_input<45>
  PIN n_FNN_input<44>
    DIRECTION INOUT ;
    USE SIGNAL ;
    PORT
      LAYER METAL3 ;
        RECT 4467.9 1609.9 4469.3 1612.24 ;
    END
  END n_FNN_input<44>
  PIN n_FNN_input<43>
    DIRECTION INOUT ;
    USE SIGNAL ;
    PORT
      LAYER METAL3 ;
        RECT 4481.9 1609.9 4483.3 1612.24 ;
    END
  END n_FNN_input<43>
  PIN n_FNN_input<42>
    DIRECTION INOUT ;
    USE SIGNAL ;
    PORT
      LAYER METAL3 ;
        RECT 4495.9 1609.9 4497.3 1612.24 ;
    END
  END n_FNN_input<42>
  PIN n_FNN_input<41>
    DIRECTION INOUT ;
    USE SIGNAL ;
    PORT
      LAYER METAL3 ;
        RECT 4509.9 1609.9 4511.3 1612.24 ;
    END
  END n_FNN_input<41>
  PIN n_FNN_input<40>
    DIRECTION INOUT ;
    USE SIGNAL ;
    PORT
      LAYER METAL3 ;
        RECT 4523.9 1609.9 4525.3 1612.24 ;
    END
  END n_FNN_input<40>
  PIN n_FNN_input<39>
    DIRECTION INOUT ;
    USE SIGNAL ;
    PORT
      LAYER METAL3 ;
        RECT 4537.9 1609.9 4539.3 1612.24 ;
    END
  END n_FNN_input<39>
  PIN n_FNN_input<38>
    DIRECTION INOUT ;
    USE SIGNAL ;
    PORT
      LAYER METAL3 ;
        RECT 4551.9 1609.9 4553.3 1612.24 ;
    END
  END n_FNN_input<38>
  PIN n_FNN_input<37>
    DIRECTION INOUT ;
    USE SIGNAL ;
    PORT
      LAYER METAL3 ;
        RECT 4565.9 1609.9 4567.3 1612.24 ;
    END
  END n_FNN_input<37>
  PIN n_FNN_input<36>
    DIRECTION INOUT ;
    USE SIGNAL ;
    PORT
      LAYER METAL3 ;
        RECT 4579.9 1609.9 4581.3 1612.24 ;
    END
  END n_FNN_input<36>
  PIN n_FNN_input<35>
    DIRECTION INOUT ;
    USE SIGNAL ;
    PORT
      LAYER METAL3 ;
        RECT 4593.9 1609.9 4595.3 1612.24 ;
    END
  END n_FNN_input<35>
  PIN n_FNN_input<34>
    DIRECTION INOUT ;
    USE SIGNAL ;
    PORT
      LAYER METAL3 ;
        RECT 4607.9 1609.9 4609.3 1612.24 ;
    END
  END n_FNN_input<34>
  PIN n_FNN_input<33>
    DIRECTION INOUT ;
    USE SIGNAL ;
    PORT
      LAYER METAL3 ;
        RECT 4621.9 1609.9 4623.3 1612.24 ;
    END
  END n_FNN_input<33>
  PIN n_FNN_input<32>
    DIRECTION INOUT ;
    USE SIGNAL ;
    PORT
      LAYER METAL3 ;
        RECT 4635.9 1609.9 4637.3 1612.24 ;
    END
  END n_FNN_input<32>
  PIN n_FNN_input<31>
    DIRECTION INOUT ;
    USE SIGNAL ;
    PORT
      LAYER METAL3 ;
        RECT 4649.9 1609.9 4651.3 1612.24 ;
    END
  END n_FNN_input<31>
  PIN n_FNN_input<30>
    DIRECTION INOUT ;
    USE SIGNAL ;
    PORT
      LAYER METAL3 ;
        RECT 4663.9 1609.9 4665.3 1612.24 ;
    END
  END n_FNN_input<30>
  PIN n_FNN_input<29>
    DIRECTION INOUT ;
    USE SIGNAL ;
    PORT
      LAYER METAL3 ;
        RECT 4677.9 1609.9 4679.3 1612.24 ;
    END
  END n_FNN_input<29>
  PIN n_FNN_input<28>
    DIRECTION INOUT ;
    USE SIGNAL ;
    PORT
      LAYER METAL3 ;
        RECT 4691.9 1609.9 4693.3 1612.24 ;
    END
  END n_FNN_input<28>
  PIN n_FNN_input<27>
    DIRECTION INOUT ;
    USE SIGNAL ;
    PORT
      LAYER METAL3 ;
        RECT 4705.9 1609.9 4707.3 1612.24 ;
    END
  END n_FNN_input<27>
  PIN n_FNN_input<26>
    DIRECTION INOUT ;
    USE SIGNAL ;
    PORT
      LAYER METAL3 ;
        RECT 4719.9 1609.9 4721.3 1612.24 ;
    END
  END n_FNN_input<26>
  PIN n_FNN_input<25>
    DIRECTION INOUT ;
    USE SIGNAL ;
    PORT
      LAYER METAL3 ;
        RECT 4733.9 1609.9 4735.3 1612.24 ;
    END
  END n_FNN_input<25>
  PIN n_FNN_input<24>
    DIRECTION INOUT ;
    USE SIGNAL ;
    PORT
      LAYER METAL3 ;
        RECT 4747.9 1609.9 4749.3 1612.24 ;
    END
  END n_FNN_input<24>
  PIN n_FNN_input<23>
    DIRECTION INOUT ;
    USE SIGNAL ;
    PORT
      LAYER METAL3 ;
        RECT 4761.9 1609.9 4763.3 1612.24 ;
    END
  END n_FNN_input<23>
  PIN n_FNN_input<22>
    DIRECTION INOUT ;
    USE SIGNAL ;
    PORT
      LAYER METAL3 ;
        RECT 4775.9 1609.9 4777.3 1612.24 ;
    END
  END n_FNN_input<22>
  PIN n_FNN_input<21>
    DIRECTION INOUT ;
    USE SIGNAL ;
    PORT
      LAYER METAL3 ;
        RECT 4789.9 1609.9 4791.3 1612.24 ;
    END
  END n_FNN_input<21>
  PIN n_FNN_input<20>
    DIRECTION INOUT ;
    USE SIGNAL ;
    PORT
      LAYER METAL3 ;
        RECT 4803.9 1609.9 4805.3 1612.24 ;
    END
  END n_FNN_input<20>
  PIN n_FNN_input<19>
    DIRECTION INOUT ;
    USE SIGNAL ;
    PORT
      LAYER METAL3 ;
        RECT 4817.9 1609.9 4819.3 1612.24 ;
    END
  END n_FNN_input<19>
  PIN n_FNN_input<18>
    DIRECTION INOUT ;
    USE SIGNAL ;
    PORT
      LAYER METAL3 ;
        RECT 4831.9 1609.9 4833.3 1612.24 ;
    END
  END n_FNN_input<18>
  PIN n_FNN_input<17>
    DIRECTION INOUT ;
    USE SIGNAL ;
    PORT
      LAYER METAL3 ;
        RECT 4845.9 1609.9 4847.3 1612.24 ;
    END
  END n_FNN_input<17>
  PIN n_FNN_input<16>
    DIRECTION INOUT ;
    USE SIGNAL ;
    PORT
      LAYER METAL3 ;
        RECT 4859.9 1609.9 4861.3 1612.24 ;
    END
  END n_FNN_input<16>
  PIN n_FNN_input<15>
    DIRECTION INOUT ;
    USE SIGNAL ;
    PORT
      LAYER METAL3 ;
        RECT 4873.9 1609.9 4875.3 1612.24 ;
    END
  END n_FNN_input<15>
  PIN n_FNN_input<14>
    DIRECTION INOUT ;
    USE SIGNAL ;
    PORT
      LAYER METAL3 ;
        RECT 4887.9 1609.9 4889.3 1612.24 ;
    END
  END n_FNN_input<14>
  PIN n_FNN_input<13>
    DIRECTION INOUT ;
    USE SIGNAL ;
    PORT
      LAYER METAL3 ;
        RECT 4901.9 1609.9 4903.3 1612.24 ;
    END
  END n_FNN_input<13>
  PIN n_FNN_input<12>
    DIRECTION INOUT ;
    USE SIGNAL ;
    PORT
      LAYER METAL3 ;
        RECT 4915.9 1609.9 4917.3 1612.24 ;
    END
  END n_FNN_input<12>
  PIN n_FNN_input<11>
    DIRECTION INOUT ;
    USE SIGNAL ;
    PORT
      LAYER METAL3 ;
        RECT 4929.9 1609.9 4931.3 1612.24 ;
    END
  END n_FNN_input<11>
  PIN n_FNN_input<10>
    DIRECTION INOUT ;
    USE SIGNAL ;
    PORT
      LAYER METAL3 ;
        RECT 4943.9 1609.9 4945.3 1612.24 ;
    END
  END n_FNN_input<10>
  PIN n_FNN_input<9>
    DIRECTION INOUT ;
    USE SIGNAL ;
    PORT
      LAYER METAL3 ;
        RECT 4957.9 1609.9 4959.3 1612.24 ;
    END
  END n_FNN_input<9>
  PIN n_FNN_input<8>
    DIRECTION INOUT ;
    USE SIGNAL ;
    PORT
      LAYER METAL3 ;
        RECT 4971.9 1609.9 4973.3 1612.24 ;
    END
  END n_FNN_input<8>
  PIN n_FNN_input<7>
    DIRECTION INOUT ;
    USE SIGNAL ;
    PORT
      LAYER METAL3 ;
        RECT 4985.9 1609.9 4987.3 1612.24 ;
    END
  END n_FNN_input<7>
  PIN n_FNN_input<6>
    DIRECTION INOUT ;
    USE SIGNAL ;
    PORT
      LAYER METAL3 ;
        RECT 4999.9 1609.9 5001.3 1612.24 ;
    END
  END n_FNN_input<6>
  PIN n_FNN_input<5>
    DIRECTION INOUT ;
    USE SIGNAL ;
    PORT
      LAYER METAL3 ;
        RECT 5013.9 1609.9 5015.3 1612.24 ;
    END
  END n_FNN_input<5>
  PIN n_FNN_input<4>
    DIRECTION INOUT ;
    USE SIGNAL ;
    PORT
      LAYER METAL3 ;
        RECT 5027.9 1609.9 5029.3 1612.24 ;
    END
  END n_FNN_input<4>
  PIN n_FNN_input<3>
    DIRECTION INOUT ;
    USE SIGNAL ;
    PORT
      LAYER METAL3 ;
        RECT 5041.9 1609.9 5043.3 1612.24 ;
    END
  END n_FNN_input<3>
  PIN n_FNN_input<2>
    DIRECTION INOUT ;
    USE SIGNAL ;
    PORT
      LAYER METAL3 ;
        RECT 5055.9 1609.9 5057.3 1612.24 ;
    END
  END n_FNN_input<2>
  PIN n_FNN_input<1>
    DIRECTION INOUT ;
    USE SIGNAL ;
    PORT
      LAYER METAL3 ;
        RECT 5069.9 1609.9 5071.3 1612.24 ;
    END
  END n_FNN_input<1>
  PIN n_FNN_input<0>
    DIRECTION INOUT ;
    USE SIGNAL ;
    PORT
      LAYER METAL3 ;
        RECT 5083.9 1609.9 5085.3 1612.24 ;
    END
  END n_FNN_input<0>
  PIN n_FNN_ly0_Dr_En
    DIRECTION INOUT ;
    USE SIGNAL ;
    PORT
      LAYER METAL3 ;
        RECT 5097.9 1609.9 5099.3 1612.24 ;
    END
  END n_FNN_ly0_Dr_En
  PIN n_FNN_ly0_G_En
    DIRECTION INOUT ;
    USE SIGNAL ;
    PORT
      LAYER METAL3 ;
        RECT 5111.9 1609.9 5113.3 1612.24 ;
    END
  END n_FNN_ly0_G_En
  PIN n_ActF_Vg_bias
    DIRECTION INOUT ;
    USE SIGNAL ;
    PORT
      LAYER METAL3 ;
        RECT 5125.9 1609.9 5127.3 1612.24 ;
    END
  END n_ActF_Vg_bias
  PIN n_ActF_selb
    DIRECTION INOUT ;
    USE SIGNAL ;
    PORT
      LAYER METAL3 ;
        RECT 5139.9 1609.9 5141.3 1612.24 ;
    END
  END n_ActF_selb
  PIN n_ActF_sel
    DIRECTION INOUT ;
    USE SIGNAL ;
    PORT
      LAYER METAL3 ;
        RECT 5153.9 1609.9 5155.3 1612.24 ;
    END
  END n_ActF_sel
  PIN n_Run_Drainline
    DIRECTION INOUT ;
    USE SIGNAL ;
    PORT
      LAYER METAL3 ;
        RECT 5167.9 1609.9 5169.3 1612.24 ;
    END
  END n_Run_Drainline
  PIN n_Prog_Drainline
    DIRECTION INOUT ;
    USE SIGNAL ;
    PORT
      LAYER METAL3 ;
        RECT 5181.9 1609.9 5183.3 1612.24 ;
    END
  END n_Prog_Drainline
  PIN n_FNN_shr_Dr_bit<6>
    DIRECTION INOUT ;
    USE SIGNAL ;
    PORT
      LAYER METAL3 ;
        RECT 5195.9 1609.9 5197.3 1612.24 ;
    END
  END n_FNN_shr_Dr_bit<6>
  PIN n_FNN_shr_Dr_bit<5>
    DIRECTION INOUT ;
    USE SIGNAL ;
    PORT
      LAYER METAL3 ;
        RECT 5209.9 1609.9 5211.3 1612.24 ;
    END
  END n_FNN_shr_Dr_bit<5>
  PIN n_FNN_shr_Dr_bit<4>
    DIRECTION INOUT ;
    USE SIGNAL ;
    PORT
      LAYER METAL3 ;
        RECT 5223.9 1609.9 5225.3 1612.24 ;
    END
  END n_FNN_shr_Dr_bit<4>
  PIN n_FNN_shr_Dr_bit<3>
    DIRECTION INOUT ;
    USE SIGNAL ;
    PORT
      LAYER METAL3 ;
        RECT 5237.9 1609.9 5239.3 1612.24 ;
    END
  END n_FNN_shr_Dr_bit<3>
  PIN n_FNN_shr_Dr_bit<2>
    DIRECTION INOUT ;
    USE SIGNAL ;
    PORT
      LAYER METAL3 ;
        RECT 5251.9 1609.9 5253.3 1612.24 ;
    END
  END n_FNN_shr_Dr_bit<2>
  PIN n_FNN_shr_Dr_bit<1>
    DIRECTION INOUT ;
    USE SIGNAL ;
    PORT
      LAYER METAL3 ;
        RECT 5265.9 1609.9 5267.3 1612.24 ;
    END
  END n_FNN_shr_Dr_bit<1>
  PIN n_FNN_shr_Dr_bit<0>
    DIRECTION INOUT ;
    USE SIGNAL ;
    PORT
      LAYER METAL3 ;
        RECT 5279.9 1609.9 5281.3 1612.24 ;
    END
  END n_FNN_shr_Dr_bit<0>
  PIN n_FNN_shr_G_bit<7>
    DIRECTION INOUT ;
    USE SIGNAL ;
    PORT
      LAYER METAL3 ;
        RECT 5293.9 1609.9 5295.3 1612.24 ;
    END
  END n_FNN_shr_G_bit<7>
  PIN n_FNN_shr_G_bit<6>
    DIRECTION INOUT ;
    USE SIGNAL ;
    PORT
      LAYER METAL3 ;
        RECT 5307.9 1609.9 5309.3 1612.24 ;
    END
  END n_FNN_shr_G_bit<6>
  PIN n_FNN_shr_G_bit<5>
    DIRECTION INOUT ;
    USE SIGNAL ;
    PORT
      LAYER METAL3 ;
        RECT 5321.9 1609.9 5323.3 1612.24 ;
    END
  END n_FNN_shr_G_bit<5>
  PIN n_FNN_shr_G_bit<4>
    DIRECTION INOUT ;
    USE SIGNAL ;
    PORT
      LAYER METAL3 ;
        RECT 5335.9 1609.9 5337.3 1612.24 ;
    END
  END n_FNN_shr_G_bit<4>
  PIN n_FNN_shr_G_bit<3>
    DIRECTION INOUT ;
    USE SIGNAL ;
    PORT
      LAYER METAL3 ;
        RECT 5349.9 1609.9 5351.3 1612.24 ;
    END
  END n_FNN_shr_G_bit<3>
  PIN n_FNN_shr_G_bit<2>
    DIRECTION INOUT ;
    USE SIGNAL ;
    PORT
      LAYER METAL3 ;
        RECT 5363.9 1609.9 5365.3 1612.24 ;
    END
  END n_FNN_shr_G_bit<2>
  PIN n_FNN_shr_G_bit<1>
    DIRECTION INOUT ;
    USE SIGNAL ;
    PORT
      LAYER METAL3 ;
        RECT 5377.9 1609.9 5379.3 1612.24 ;
    END
  END n_FNN_shr_G_bit<1>
  PIN n_FNN_shr_G_bit<0>
    DIRECTION INOUT ;
    USE SIGNAL ;
    PORT
      LAYER METAL3 ;
        RECT 5391.9 1609.9 5393.3 1612.24 ;
    END
  END n_FNN_shr_G_bit<0>
  PIN n_run_hv
    DIRECTION INOUT ;
    USE SIGNAL ;
    PORT
      LAYER METAL3 ;
        RECT 5405.9 1609.9 5407.3 1612.24 ;
    END
  END n_run_hv
  PIN n_prog_hv
    DIRECTION INOUT ;
    USE SIGNAL ;
    PORT
      LAYER METAL3 ;
        RECT 5419.9 1609.9 5421.3 1612.24 ;
    END
  END n_prog_hv
  PIN n_VGRUN
    DIRECTION INOUT ;
    USE SIGNAL ;
    PORT
      LAYER METAL3 ;
        RECT 5433.9 1609.9 5435.3 1612.24 ;
    END
  END n_VGRUN
  PIN n_VGPROG
    DIRECTION INOUT ;
    USE SIGNAL ;
    PORT
      LAYER METAL3 ;
        RECT 5447.9 1609.9 5449.3 1612.24 ;
    END
  END n_VGPROG
  PIN n_VINJ
    DIRECTION INOUT ;
    USE SIGNAL ;
    PORT
      LAYER METAL3 ;
        RECT 5461.9 1609.9 5463.3 1612.24 ;
    END
  END n_VINJ
  PIN n_GND
    DIRECTION INOUT ;
    USE SIGNAL ;
    PORT
      LAYER METAL3 ;
        RECT 5475.9 1609.9 5477.3 1612.24 ;
    END
  END n_GND
  PIN n_AVDD
    DIRECTION INOUT ;
    USE SIGNAL ;
    PORT
      LAYER METAL3 ;
        RECT 5489.9 1609.9 5491.3 1612.24 ;
    END
  END n_AVDD
  PIN n_DVDD
    DIRECTION INOUT ;
    USE SIGNAL ;
    PORT
      LAYER METAL3 ;
        RECT 5503.9 1609.9 5505.3 1612.24 ;
    END
  END n_DVDD
  PIN n_VTUN
    DIRECTION INOUT ;
    USE SIGNAL ;
    PORT
      LAYER METAL3 ;
        RECT 5517.9 1609.9 5519.3 1612.24 ;
    END
  END n_VTUN
  PIN n_FNN_input<158>
    DIRECTION INOUT ;
    USE SIGNAL ;
    PORT
      LAYER METAL3 ;
        RECT 2871.9 1609.9 2873.3 1612.24 ;
    END
  END n_FNN_input<158>
  PIN n_FNN_input<157>
    DIRECTION INOUT ;
    USE SIGNAL ;
    PORT
      LAYER METAL3 ;
        RECT 2885.9 1609.9 2887.3 1612.24 ;
    END
  END n_FNN_input<157>
  PIN n_FNN_input<156>
    DIRECTION INOUT ;
    USE SIGNAL ;
    PORT
      LAYER METAL3 ;
        RECT 2899.9 1609.9 2901.3 1612.24 ;
    END
  END n_FNN_input<156>
  PIN n_FNN_input<155>
    DIRECTION INOUT ;
    USE SIGNAL ;
    PORT
      LAYER METAL3 ;
        RECT 2913.9 1609.9 2915.3 1612.24 ;
    END
  END n_FNN_input<155>
  PIN n_FNN_input<154>
    DIRECTION INOUT ;
    USE SIGNAL ;
    PORT
      LAYER METAL3 ;
        RECT 2927.9 1609.9 2929.3 1612.24 ;
    END
  END n_FNN_input<154>
  PIN n_FNN_input<153>
    DIRECTION INOUT ;
    USE SIGNAL ;
    PORT
      LAYER METAL3 ;
        RECT 2941.9 1609.9 2943.3 1612.24 ;
    END
  END n_FNN_input<153>
  PIN n_FNN_input<152>
    DIRECTION INOUT ;
    USE SIGNAL ;
    PORT
      LAYER METAL3 ;
        RECT 2955.9 1609.9 2957.3 1612.24 ;
    END
  END n_FNN_input<152>
  PIN n_FNN_input<151>
    DIRECTION INOUT ;
    USE SIGNAL ;
    PORT
      LAYER METAL3 ;
        RECT 2969.9 1609.9 2971.3 1612.24 ;
    END
  END n_FNN_input<151>
  PIN n_FNN_input<150>
    DIRECTION INOUT ;
    USE SIGNAL ;
    PORT
      LAYER METAL3 ;
        RECT 2983.9 1609.9 2985.3 1612.24 ;
    END
  END n_FNN_input<150>
  PIN n_FNN_input<149>
    DIRECTION INOUT ;
    USE SIGNAL ;
    PORT
      LAYER METAL3 ;
        RECT 2997.9 1609.9 2999.3 1612.24 ;
    END
  END n_FNN_input<149>
  PIN n_FNN_input<148>
    DIRECTION INOUT ;
    USE SIGNAL ;
    PORT
      LAYER METAL3 ;
        RECT 3011.9 1609.9 3013.3 1612.24 ;
    END
  END n_FNN_input<148>
  PIN n_FNN_input<147>
    DIRECTION INOUT ;
    USE SIGNAL ;
    PORT
      LAYER METAL3 ;
        RECT 3025.9 1609.9 3027.3 1612.24 ;
    END
  END n_FNN_input<147>
  PIN n_FNN_input<146>
    DIRECTION INOUT ;
    USE SIGNAL ;
    PORT
      LAYER METAL3 ;
        RECT 3039.9 1609.9 3041.3 1612.24 ;
    END
  END n_FNN_input<146>
  PIN n_FNN_input<145>
    DIRECTION INOUT ;
    USE SIGNAL ;
    PORT
      LAYER METAL3 ;
        RECT 3053.9 1609.9 3055.3 1612.24 ;
    END
  END n_FNN_input<145>
  PIN n_FNN_input<144>
    DIRECTION INOUT ;
    USE SIGNAL ;
    PORT
      LAYER METAL3 ;
        RECT 3067.9 1609.9 3069.3 1612.24 ;
    END
  END n_FNN_input<144>
  PIN n_FNN_input<143>
    DIRECTION INOUT ;
    USE SIGNAL ;
    PORT
      LAYER METAL3 ;
        RECT 3081.9 1609.9 3083.3 1612.24 ;
    END
  END n_FNN_input<143>
  PIN n_FNN_input<142>
    DIRECTION INOUT ;
    USE SIGNAL ;
    PORT
      LAYER METAL3 ;
        RECT 3095.9 1609.9 3097.3 1612.24 ;
    END
  END n_FNN_input<142>
  PIN n_FNN_input<141>
    DIRECTION INOUT ;
    USE SIGNAL ;
    PORT
      LAYER METAL3 ;
        RECT 3109.9 1609.9 3111.3 1612.24 ;
    END
  END n_FNN_input<141>
  PIN n_FNN_input<140>
    DIRECTION INOUT ;
    USE SIGNAL ;
    PORT
      LAYER METAL3 ;
        RECT 3123.9 1609.9 3125.3 1612.24 ;
    END
  END n_FNN_input<140>
  PIN n_FNN_input<139>
    DIRECTION INOUT ;
    USE SIGNAL ;
    PORT
      LAYER METAL3 ;
        RECT 3137.9 1609.9 3139.3 1612.24 ;
    END
  END n_FNN_input<139>
  PIN n_FNN_input<138>
    DIRECTION INOUT ;
    USE SIGNAL ;
    PORT
      LAYER METAL3 ;
        RECT 3151.9 1609.9 3153.3 1612.24 ;
    END
  END n_FNN_input<138>
  PIN n_FNN_input<137>
    DIRECTION INOUT ;
    USE SIGNAL ;
    PORT
      LAYER METAL3 ;
        RECT 3165.9 1609.9 3167.3 1612.24 ;
    END
  END n_FNN_input<137>
  PIN n_FNN_input<136>
    DIRECTION INOUT ;
    USE SIGNAL ;
    PORT
      LAYER METAL3 ;
        RECT 3179.9 1609.9 3181.3 1612.24 ;
    END
  END n_FNN_input<136>
  PIN n_FNN_input<135>
    DIRECTION INOUT ;
    USE SIGNAL ;
    PORT
      LAYER METAL3 ;
        RECT 3193.9 1609.9 3195.3 1612.24 ;
    END
  END n_FNN_input<135>
  PIN n_FNN_input<134>
    DIRECTION INOUT ;
    USE SIGNAL ;
    PORT
      LAYER METAL3 ;
        RECT 3207.9 1609.9 3209.3 1612.24 ;
    END
  END n_FNN_input<134>
  PIN n_FNN_input<133>
    DIRECTION INOUT ;
    USE SIGNAL ;
    PORT
      LAYER METAL3 ;
        RECT 3221.9 1609.9 3223.3 1612.24 ;
    END
  END n_FNN_input<133>
  PIN n_FNN_input<132>
    DIRECTION INOUT ;
    USE SIGNAL ;
    PORT
      LAYER METAL3 ;
        RECT 3235.9 1609.9 3237.3 1612.24 ;
    END
  END n_FNN_input<132>
  PIN n_FNN_input<131>
    DIRECTION INOUT ;
    USE SIGNAL ;
    PORT
      LAYER METAL3 ;
        RECT 3249.9 1609.9 3251.3 1612.24 ;
    END
  END n_FNN_input<131>
  PIN n_FNN_input<130>
    DIRECTION INOUT ;
    USE SIGNAL ;
    PORT
      LAYER METAL3 ;
        RECT 3263.9 1609.9 3265.3 1612.24 ;
    END
  END n_FNN_input<130>
  PIN n_FNN_input<129>
    DIRECTION INOUT ;
    USE SIGNAL ;
    PORT
      LAYER METAL3 ;
        RECT 3277.9 1609.9 3279.3 1612.24 ;
    END
  END n_FNN_input<129>
  PIN n_FNN_input<128>
    DIRECTION INOUT ;
    USE SIGNAL ;
    PORT
      LAYER METAL3 ;
        RECT 3291.9 1609.9 3293.3 1612.24 ;
    END
  END n_FNN_input<128>
  PIN n_FNN_input<127>
    DIRECTION INOUT ;
    USE SIGNAL ;
    PORT
      LAYER METAL3 ;
        RECT 3305.9 1609.9 3307.3 1612.24 ;
    END
  END n_FNN_input<127>
  PIN n_FNN_input<126>
    DIRECTION INOUT ;
    USE SIGNAL ;
    PORT
      LAYER METAL3 ;
        RECT 3319.9 1609.9 3321.3 1612.24 ;
    END
  END n_FNN_input<126>
  PIN n_FNN_input<125>
    DIRECTION INOUT ;
    USE SIGNAL ;
    PORT
      LAYER METAL3 ;
        RECT 3333.9 1609.9 3335.3 1612.24 ;
    END
  END n_FNN_input<125>
  PIN n_FNN_input<124>
    DIRECTION INOUT ;
    USE SIGNAL ;
    PORT
      LAYER METAL3 ;
        RECT 3347.9 1609.9 3349.3 1612.24 ;
    END
  END n_FNN_input<124>
  PIN n_FNN_input<123>
    DIRECTION INOUT ;
    USE SIGNAL ;
    PORT
      LAYER METAL3 ;
        RECT 3361.9 1609.9 3363.3 1612.24 ;
    END
  END n_FNN_input<123>
  PIN n_FNN_input<122>
    DIRECTION INOUT ;
    USE SIGNAL ;
    PORT
      LAYER METAL3 ;
        RECT 3375.9 1609.9 3377.3 1612.24 ;
    END
  END n_FNN_input<122>
  PIN n_FNN_input<121>
    DIRECTION INOUT ;
    USE SIGNAL ;
    PORT
      LAYER METAL3 ;
        RECT 3389.9 1609.9 3391.3 1612.24 ;
    END
  END n_FNN_input<121>
  PIN n_FNN_input<120>
    DIRECTION INOUT ;
    USE SIGNAL ;
    PORT
      LAYER METAL3 ;
        RECT 3403.9 1609.9 3405.3 1612.24 ;
    END
  END n_FNN_input<120>
  PIN n_FNN_input<119>
    DIRECTION INOUT ;
    USE SIGNAL ;
    PORT
      LAYER METAL3 ;
        RECT 3417.9 1609.9 3419.3 1612.24 ;
    END
  END n_FNN_input<119>
  PIN n_FNN_input<118>
    DIRECTION INOUT ;
    USE SIGNAL ;
    PORT
      LAYER METAL3 ;
        RECT 3431.9 1609.9 3433.3 1612.24 ;
    END
  END n_FNN_input<118>
  PIN n_FNN_input<117>
    DIRECTION INOUT ;
    USE SIGNAL ;
    PORT
      LAYER METAL3 ;
        RECT 3445.9 1609.9 3447.3 1612.24 ;
    END
  END n_FNN_input<117>
  PIN n_FNN_input<116>
    DIRECTION INOUT ;
    USE SIGNAL ;
    PORT
      LAYER METAL3 ;
        RECT 3459.9 1609.9 3461.3 1612.24 ;
    END
  END n_FNN_input<116>
  PIN n_FNN_input<115>
    DIRECTION INOUT ;
    USE SIGNAL ;
    PORT
      LAYER METAL3 ;
        RECT 3473.9 1609.9 3475.3 1612.24 ;
    END
  END n_FNN_input<115>
  PIN n_FNN_input<114>
    DIRECTION INOUT ;
    USE SIGNAL ;
    PORT
      LAYER METAL3 ;
        RECT 3487.9 1609.9 3489.3 1612.24 ;
    END
  END n_FNN_input<114>
  PIN n_FNN_input<113>
    DIRECTION INOUT ;
    USE SIGNAL ;
    PORT
      LAYER METAL3 ;
        RECT 3501.9 1609.9 3503.3 1612.24 ;
    END
  END n_FNN_input<113>
  PIN n_FNN_input<112>
    DIRECTION INOUT ;
    USE SIGNAL ;
    PORT
      LAYER METAL3 ;
        RECT 3515.9 1609.9 3517.3 1612.24 ;
    END
  END n_FNN_input<112>
  PIN n_FNN_input<111>
    DIRECTION INOUT ;
    USE SIGNAL ;
    PORT
      LAYER METAL3 ;
        RECT 3529.9 1609.9 3531.3 1612.24 ;
    END
  END n_FNN_input<111>
  PIN n_FNN_input<110>
    DIRECTION INOUT ;
    USE SIGNAL ;
    PORT
      LAYER METAL3 ;
        RECT 3543.9 1609.9 3545.3 1612.24 ;
    END
  END n_FNN_input<110>
  PIN n_FNN_input<109>
    DIRECTION INOUT ;
    USE SIGNAL ;
    PORT
      LAYER METAL3 ;
        RECT 3557.9 1609.9 3559.3 1612.24 ;
    END
  END n_FNN_input<109>
  PIN n_FNN_input<108>
    DIRECTION INOUT ;
    USE SIGNAL ;
    PORT
      LAYER METAL3 ;
        RECT 3571.9 1609.9 3573.3 1612.24 ;
    END
  END n_FNN_input<108>
  PIN n_FNN_input<107>
    DIRECTION INOUT ;
    USE SIGNAL ;
    PORT
      LAYER METAL3 ;
        RECT 3585.9 1609.9 3587.3 1612.24 ;
    END
  END n_FNN_input<107>
  PIN n_FNN_input<106>
    DIRECTION INOUT ;
    USE SIGNAL ;
    PORT
      LAYER METAL3 ;
        RECT 3599.9 1609.9 3601.3 1612.24 ;
    END
  END n_FNN_input<106>
  PIN n_FNN_input<105>
    DIRECTION INOUT ;
    USE SIGNAL ;
    PORT
      LAYER METAL3 ;
        RECT 3613.9 1609.9 3615.3 1612.24 ;
    END
  END n_FNN_input<105>
  PIN n_FNN_input<104>
    DIRECTION INOUT ;
    USE SIGNAL ;
    PORT
      LAYER METAL3 ;
        RECT 3627.9 1609.9 3629.3 1612.24 ;
    END
  END n_FNN_input<104>
  PIN n_FNN_input<103>
    DIRECTION INOUT ;
    USE SIGNAL ;
    PORT
      LAYER METAL3 ;
        RECT 3641.9 1609.9 3643.3 1612.24 ;
    END
  END n_FNN_input<103>
  PIN n_FNN_input<102>
    DIRECTION INOUT ;
    USE SIGNAL ;
    PORT
      LAYER METAL3 ;
        RECT 3655.9 1609.9 3657.3 1612.24 ;
    END
  END n_FNN_input<102>
  PIN n_FNN_input<101>
    DIRECTION INOUT ;
    USE SIGNAL ;
    PORT
      LAYER METAL3 ;
        RECT 3669.9 1609.9 3671.3 1612.24 ;
    END
  END n_FNN_input<101>
  PIN n_FNN_input<100>
    DIRECTION INOUT ;
    USE SIGNAL ;
    PORT
      LAYER METAL3 ;
        RECT 3683.9 1609.9 3685.3 1612.24 ;
    END
  END n_FNN_input<100>
  PIN n_FNN_input<99>
    DIRECTION INOUT ;
    USE SIGNAL ;
    PORT
      LAYER METAL3 ;
        RECT 3697.9 1609.9 3699.3 1612.24 ;
    END
  END n_FNN_input<99>
  PIN n_FNN_input<98>
    DIRECTION INOUT ;
    USE SIGNAL ;
    PORT
      LAYER METAL3 ;
        RECT 3711.9 1609.9 3713.3 1612.24 ;
    END
  END n_FNN_input<98>
  PIN n_FNN_input<97>
    DIRECTION INOUT ;
    USE SIGNAL ;
    PORT
      LAYER METAL3 ;
        RECT 3725.9 1609.9 3727.3 1612.24 ;
    END
  END n_FNN_input<97>
  PIN n_FNN_input<96>
    DIRECTION INOUT ;
    USE SIGNAL ;
    PORT
      LAYER METAL3 ;
        RECT 3739.9 1609.9 3741.3 1612.24 ;
    END
  END n_FNN_input<96>
  PIN n_FNN_input<95>
    DIRECTION INOUT ;
    USE SIGNAL ;
    PORT
      LAYER METAL3 ;
        RECT 3753.9 1609.9 3755.3 1612.24 ;
    END
  END n_FNN_input<95>
  PIN n_FNN_input<94>
    DIRECTION INOUT ;
    USE SIGNAL ;
    PORT
      LAYER METAL3 ;
        RECT 3767.9 1609.9 3769.3 1612.24 ;
    END
  END n_FNN_input<94>
  PIN n_FNN_input<93>
    DIRECTION INOUT ;
    USE SIGNAL ;
    PORT
      LAYER METAL3 ;
        RECT 3781.9 1609.9 3783.3 1612.24 ;
    END
  END n_FNN_input<93>
  PIN n_FNN_input<92>
    DIRECTION INOUT ;
    USE SIGNAL ;
    PORT
      LAYER METAL3 ;
        RECT 3795.9 1609.9 3797.3 1612.24 ;
    END
  END n_FNN_input<92>
  PIN n_FNN_input<91>
    DIRECTION INOUT ;
    USE SIGNAL ;
    PORT
      LAYER METAL3 ;
        RECT 3809.9 1609.9 3811.3 1612.24 ;
    END
  END n_FNN_input<91>
  PIN n_FNN_input<90>
    DIRECTION INOUT ;
    USE SIGNAL ;
    PORT
      LAYER METAL3 ;
        RECT 3823.9 1609.9 3825.3 1612.24 ;
    END
  END n_FNN_input<90>
  PIN n_FNN_input<89>
    DIRECTION INOUT ;
    USE SIGNAL ;
    PORT
      LAYER METAL3 ;
        RECT 3837.9 1609.9 3839.3 1612.24 ;
    END
  END n_FNN_input<89>
  PIN n_FNN_input<88>
    DIRECTION INOUT ;
    USE SIGNAL ;
    PORT
      LAYER METAL3 ;
        RECT 3851.9 1609.9 3853.3 1612.24 ;
    END
  END n_FNN_input<88>
  PIN n_FNN_input<87>
    DIRECTION INOUT ;
    USE SIGNAL ;
    PORT
      LAYER METAL3 ;
        RECT 3865.9 1609.9 3867.3 1612.24 ;
    END
  END n_FNN_input<87>
  PIN n_FNN_input<86>
    DIRECTION INOUT ;
    USE SIGNAL ;
    PORT
      LAYER METAL3 ;
        RECT 3879.9 1609.9 3881.3 1612.24 ;
    END
  END n_FNN_input<86>
  PIN n_FNN_input<85>
    DIRECTION INOUT ;
    USE SIGNAL ;
    PORT
      LAYER METAL3 ;
        RECT 3893.9 1609.9 3895.3 1612.24 ;
    END
  END n_FNN_input<85>
  PIN n_FNN_input<84>
    DIRECTION INOUT ;
    USE SIGNAL ;
    PORT
      LAYER METAL3 ;
        RECT 3907.9 1609.9 3909.3 1612.24 ;
    END
  END n_FNN_input<84>
  PIN n_FNN_input<83>
    DIRECTION INOUT ;
    USE SIGNAL ;
    PORT
      LAYER METAL3 ;
        RECT 3921.9 1609.9 3923.3 1612.24 ;
    END
  END n_FNN_input<83>
  PIN n_FNN_input<82>
    DIRECTION INOUT ;
    USE SIGNAL ;
    PORT
      LAYER METAL3 ;
        RECT 3935.9 1609.9 3937.3 1612.24 ;
    END
  END n_FNN_input<82>
  PIN n_FNN_input<81>
    DIRECTION INOUT ;
    USE SIGNAL ;
    PORT
      LAYER METAL3 ;
        RECT 3949.9 1609.9 3951.3 1612.24 ;
    END
  END n_FNN_input<81>
  PIN n_FNN_input<80>
    DIRECTION INOUT ;
    USE SIGNAL ;
    PORT
      LAYER METAL3 ;
        RECT 3963.9 1609.9 3965.3 1612.24 ;
    END
  END n_FNN_input<80>
  PIN n_FNN_input<79>
    DIRECTION INOUT ;
    USE SIGNAL ;
    PORT
      LAYER METAL3 ;
        RECT 3977.9 1609.9 3979.3 1612.24 ;
    END
  END n_FNN_input<79>
  PIN n_FNN_input<78>
    DIRECTION INOUT ;
    USE SIGNAL ;
    PORT
      LAYER METAL3 ;
        RECT 3991.9 1609.9 3993.3 1612.24 ;
    END
  END n_FNN_input<78>
  PIN n_FNN_input<77>
    DIRECTION INOUT ;
    USE SIGNAL ;
    PORT
      LAYER METAL3 ;
        RECT 4005.9 1609.9 4007.3 1612.24 ;
    END
  END n_FNN_input<77>
  PIN n_FNN_input<76>
    DIRECTION INOUT ;
    USE SIGNAL ;
    PORT
      LAYER METAL3 ;
        RECT 4019.9 1609.9 4021.3 1612.24 ;
    END
  END n_FNN_input<76>
  PIN n_FNN_input<75>
    DIRECTION INOUT ;
    USE SIGNAL ;
    PORT
      LAYER METAL3 ;
        RECT 4033.9 1609.9 4035.3 1612.24 ;
    END
  END n_FNN_input<75>
  PIN n_FNN_input<74>
    DIRECTION INOUT ;
    USE SIGNAL ;
    PORT
      LAYER METAL3 ;
        RECT 4047.9 1609.9 4049.3 1612.24 ;
    END
  END n_FNN_input<74>
  PIN n_FNN_input<73>
    DIRECTION INOUT ;
    USE SIGNAL ;
    PORT
      LAYER METAL3 ;
        RECT 4061.9 1609.9 4063.3 1612.24 ;
    END
  END n_FNN_input<73>
  PIN n_FNN_input<72>
    DIRECTION INOUT ;
    USE SIGNAL ;
    PORT
      LAYER METAL3 ;
        RECT 4075.9 1609.9 4077.3 1612.24 ;
    END
  END n_FNN_input<72>
  PIN n_FNN_input<71>
    DIRECTION INOUT ;
    USE SIGNAL ;
    PORT
      LAYER METAL3 ;
        RECT 4089.9 1609.9 4091.3 1612.24 ;
    END
  END n_FNN_input<71>
  PIN n_FNN_input<70>
    DIRECTION INOUT ;
    USE SIGNAL ;
    PORT
      LAYER METAL3 ;
        RECT 4103.9 1609.9 4105.3 1612.24 ;
    END
  END n_FNN_input<70>
  PIN n_FNN_input<69>
    DIRECTION INOUT ;
    USE SIGNAL ;
    PORT
      LAYER METAL3 ;
        RECT 4117.9 1609.9 4119.3 1612.24 ;
    END
  END n_FNN_input<69>
  PIN n_FNN_input<68>
    DIRECTION INOUT ;
    USE SIGNAL ;
    PORT
      LAYER METAL3 ;
        RECT 4131.9 1609.9 4133.3 1612.24 ;
    END
  END n_FNN_input<68>
  PIN n_FNN_input<67>
    DIRECTION INOUT ;
    USE SIGNAL ;
    PORT
      LAYER METAL3 ;
        RECT 4145.9 1609.9 4147.3 1612.24 ;
    END
  END n_FNN_input<67>
  PIN n_FNN_input<66>
    DIRECTION INOUT ;
    USE SIGNAL ;
    PORT
      LAYER METAL3 ;
        RECT 4159.9 1609.9 4161.3 1612.24 ;
    END
  END n_FNN_input<66>
  PIN n_FNN_input<65>
    DIRECTION INOUT ;
    USE SIGNAL ;
    PORT
      LAYER METAL3 ;
        RECT 4173.9 1609.9 4175.3 1612.24 ;
    END
  END n_FNN_input<65>
  PIN n_FNN_input<64>
    DIRECTION INOUT ;
    USE SIGNAL ;
    PORT
      LAYER METAL3 ;
        RECT 4187.9 1609.9 4189.3 1612.24 ;
    END
  END n_FNN_input<64>
  PIN n_FNN_input<168>
    DIRECTION INOUT ;
    USE SIGNAL ;
    PORT
      LAYER METAL3 ;
        RECT 2731.9 1609.9 2733.3 1612.24 ;
    END
  END n_FNN_input<168>
  PIN n_FNN_input<167>
    DIRECTION INOUT ;
    USE SIGNAL ;
    PORT
      LAYER METAL3 ;
        RECT 2745.9 1609.9 2747.3 1612.24 ;
    END
  END n_FNN_input<167>
  PIN n_FNN_input<166>
    DIRECTION INOUT ;
    USE SIGNAL ;
    PORT
      LAYER METAL3 ;
        RECT 2759.9 1609.9 2761.3 1612.24 ;
    END
  END n_FNN_input<166>
  PIN n_FNN_input<165>
    DIRECTION INOUT ;
    USE SIGNAL ;
    PORT
      LAYER METAL3 ;
        RECT 2773.9 1609.9 2775.3 1612.24 ;
    END
  END n_FNN_input<165>
  PIN n_FNN_input<164>
    DIRECTION INOUT ;
    USE SIGNAL ;
    PORT
      LAYER METAL3 ;
        RECT 2787.9 1609.9 2789.3 1612.24 ;
    END
  END n_FNN_input<164>
  PIN n_FNN_input<163>
    DIRECTION INOUT ;
    USE SIGNAL ;
    PORT
      LAYER METAL3 ;
        RECT 2801.9 1609.9 2803.3 1612.24 ;
    END
  END n_FNN_input<163>
  PIN n_FNN_input<162>
    DIRECTION INOUT ;
    USE SIGNAL ;
    PORT
      LAYER METAL3 ;
        RECT 2815.9 1609.9 2817.3 1612.24 ;
    END
  END n_FNN_input<162>
  PIN n_FNN_input<161>
    DIRECTION INOUT ;
    USE SIGNAL ;
    PORT
      LAYER METAL3 ;
        RECT 2829.9 1609.9 2831.3 1612.24 ;
    END
  END n_FNN_input<161>
  PIN n_FNN_input<160>
    DIRECTION INOUT ;
    USE SIGNAL ;
    PORT
      LAYER METAL3 ;
        RECT 2843.9 1609.9 2845.3 1612.24 ;
    END
  END n_FNN_input<160>
  PIN n_FNN_input<159>
    DIRECTION INOUT ;
    USE SIGNAL ;
    PORT
      LAYER METAL3 ;
        RECT 2857.9 1609.9 2859.3 1612.24 ;
    END
  END n_FNN_input<159>
  PIN n_WTA_final_Vbias
    DIRECTION INOUT ;
    USE SIGNAL ;
    PORT
      LAYER METAL3 ;
        RECT 2283.9 1609.9 2285.3 1612.24 ;
    END
  END n_WTA_final_Vbias
  PIN n_WTA_final_Vmid
    DIRECTION INOUT ;
    USE SIGNAL ;
    PORT
      LAYER METAL3 ;
        RECT 2297.9 1609.9 2299.3 1612.24 ;
    END
  END n_WTA_final_Vmid
  PIN n_WTA_final_scan_Qout
    DIRECTION INOUT ;
    USE SIGNAL ;
    PORT
      LAYER METAL3 ;
        RECT 2311.9 1609.9 2313.3 1612.24 ;
    END
  END n_WTA_final_scan_Qout
  PIN n_WTA_final_scan_RSTB
    DIRECTION INOUT ;
    USE SIGNAL ;
    PORT
      LAYER METAL3 ;
        RECT 2325.9 1609.9 2327.3 1612.24 ;
    END
  END n_WTA_final_scan_RSTB
  PIN n_WTA_final_scan_CLK
    DIRECTION INOUT ;
    USE SIGNAL ;
    PORT
      LAYER METAL3 ;
        RECT 2339.9 1609.9 2341.3 1612.24 ;
    END
  END n_WTA_final_scan_CLK
  PIN n_WTA_final_scan_Din
    DIRECTION INOUT ;
    USE SIGNAL ;
    PORT
      LAYER METAL3 ;
        RECT 2353.9 1609.9 2355.3 1612.24 ;
    END
  END n_WTA_final_scan_Din
  PIN n_WTA_final_scan_out
    DIRECTION INOUT ;
    USE SIGNAL ;
    PORT
      LAYER METAL3 ;
        RECT 2367.9 1609.9 2369.3 1612.24 ;
    END
  END n_WTA_final_scan_out
  PIN n_FNN_final_Dr_En
    DIRECTION INOUT ;
    USE SIGNAL ;
    PORT
      LAYER METAL3 ;
        RECT 2381.9 1609.9 2383.3 1612.24 ;
    END
  END n_FNN_final_Dr_En
  PIN n_FNN_final_G_En
    DIRECTION INOUT ;
    USE SIGNAL ;
    PORT
      LAYER METAL3 ;
        RECT 2395.9 1609.9 2397.3 1612.24 ;
    END
  END n_FNN_final_G_En
  PIN n_Act_ly1_scan_Qout
    DIRECTION INOUT ;
    USE SIGNAL ;
    PORT
      LAYER METAL3 ;
        RECT 2409.9 1609.9 2411.3 1612.24 ;
    END
  END n_Act_ly1_scan_Qout
  PIN n_Act_ly1_scan_RSTB
    DIRECTION INOUT ;
    USE SIGNAL ;
    PORT
      LAYER METAL3 ;
        RECT 2423.9 1609.9 2425.3 1612.24 ;
    END
  END n_Act_ly1_scan_RSTB
  PIN n_Act_ly1_scan_CLK
    DIRECTION INOUT ;
    USE SIGNAL ;
    PORT
      LAYER METAL3 ;
        RECT 2437.9 1609.9 2439.3 1612.24 ;
    END
  END n_Act_ly1_scan_CLK
  PIN n_Act_ly1_scan_Din
    DIRECTION INOUT ;
    USE SIGNAL ;
    PORT
      LAYER METAL3 ;
        RECT 2451.9 1609.9 2453.3 1612.24 ;
    END
  END n_Act_ly1_scan_Din
  PIN n_Act_ly1_scan_out
    DIRECTION INOUT ;
    USE SIGNAL ;
    PORT
      LAYER METAL3 ;
        RECT 2465.9 1609.9 2467.3 1612.24 ;
    END
  END n_Act_ly1_scan_out
  PIN n_FNN_ly1_ActF_G_En
    DIRECTION INOUT ;
    USE SIGNAL ;
    PORT
      LAYER METAL3 ;
        RECT 2479.9 1609.9 2481.3 1612.24 ;
    END
  END n_FNN_ly1_ActF_G_En
  PIN n_FNN_ly1_Dr_En
    DIRECTION INOUT ;
    USE SIGNAL ;
    PORT
      LAYER METAL3 ;
        RECT 2493.9 1609.9 2495.3 1612.24 ;
    END
  END n_FNN_ly1_Dr_En
  PIN n_FNN_ly1_G_En
    DIRECTION INOUT ;
    USE SIGNAL ;
    PORT
      LAYER METAL3 ;
        RECT 2507.9 1609.9 2509.3 1612.24 ;
    END
  END n_FNN_ly1_G_En
  PIN n_Act_ly0_scan_Qout
    DIRECTION INOUT ;
    USE SIGNAL ;
    PORT
      LAYER METAL3 ;
        RECT 2521.9 1609.9 2523.3 1612.24 ;
    END
  END n_Act_ly0_scan_Qout
  PIN n_Act_ly0_scan_RSTB
    DIRECTION INOUT ;
    USE SIGNAL ;
    PORT
      LAYER METAL3 ;
        RECT 2535.9 1609.9 2537.3 1612.24 ;
    END
  END n_Act_ly0_scan_RSTB
  PIN n_Act_ly0_scan_CLK
    DIRECTION INOUT ;
    USE SIGNAL ;
    PORT
      LAYER METAL3 ;
        RECT 2549.9 1609.9 2551.3 1612.24 ;
    END
  END n_Act_ly0_scan_CLK
  PIN n_Act_ly0_scan_Din
    DIRECTION INOUT ;
    USE SIGNAL ;
    PORT
      LAYER METAL3 ;
        RECT 2563.9 1609.9 2565.3 1612.24 ;
    END
  END n_Act_ly0_scan_Din
  PIN n_Act_ly0_scan_out
    DIRECTION INOUT ;
    USE SIGNAL ;
    PORT
      LAYER METAL3 ;
        RECT 2577.9 1609.9 2579.3 1612.24 ;
    END
  END n_Act_ly0_scan_out
  PIN n_FNN_ly0_ActF_G_En
    DIRECTION INOUT ;
    USE SIGNAL ;
    PORT
      LAYER METAL3 ;
        RECT 2591.9 1609.9 2593.3 1612.24 ;
    END
  END n_FNN_ly0_ActF_G_En
  PIN n_FNN_input<175>
    DIRECTION INOUT ;
    USE SIGNAL ;
    PORT
      LAYER METAL3 ;
        RECT 2633.9 1609.9 2635.3 1612.24 ;
    END
  END n_FNN_input<175>
  PIN n_FNN_input<174>
    DIRECTION INOUT ;
    USE SIGNAL ;
    PORT
      LAYER METAL3 ;
        RECT 2647.9 1609.9 2649.3 1612.24 ;
    END
  END n_FNN_input<174>
  PIN n_FNN_input<173>
    DIRECTION INOUT ;
    USE SIGNAL ;
    PORT
      LAYER METAL3 ;
        RECT 2661.9 1609.9 2663.3 1612.24 ;
    END
  END n_FNN_input<173>
  PIN n_FNN_input<172>
    DIRECTION INOUT ;
    USE SIGNAL ;
    PORT
      LAYER METAL3 ;
        RECT 2675.9 1609.9 2677.3 1612.24 ;
    END
  END n_FNN_input<172>
  PIN n_FNN_input<171>
    DIRECTION INOUT ;
    USE SIGNAL ;
    PORT
      LAYER METAL3 ;
        RECT 2689.9 1609.9 2691.3 1612.24 ;
    END
  END n_FNN_input<171>
  PIN n_FNN_input<170>
    DIRECTION INOUT ;
    USE SIGNAL ;
    PORT
      LAYER METAL3 ;
        RECT 2703.9 1609.9 2705.3 1612.24 ;
    END
  END n_FNN_input<170>
  PIN n_FNN_input<169>
    DIRECTION INOUT ;
    USE SIGNAL ;
    PORT
      LAYER METAL3 ;
        RECT 2717.9 1609.9 2719.3 1612.24 ;
    END
  END n_FNN_input<169>
  PIN n_FNN_Vsel_dbg
    DIRECTION INOUT ;
    USE SIGNAL ;
    PORT
      LAYER METAL3 ;
        RECT 2255.9 1609.9 2257.3 1612.24 ;
    END
  END n_FNN_Vsel_dbg
  PIN n_FNN_ly0_out_95
    DIRECTION INOUT ;
    USE SIGNAL ;
    PORT
      LAYER METAL3 ;
        RECT 2269.9 1609.9 2271.3 1612.24 ;
    END
  END n_FNN_ly0_out_95
  PIN s_VMM_WTA_out_11
    DIRECTION INOUT ;
    USE SIGNAL ;
    PORT
      LAYER METAL3 ;
        RECT 984.76 0.0 986.16 2.8 ;
    END
  END s_VMM_WTA_out_11
  PIN s_FNN_ly1_out_63
    DIRECTION INOUT ;
    USE SIGNAL ;
    PORT
      LAYER METAL3 ;
        RECT 202.56 0.0 203.96 2.8 ;
    END
  END s_FNN_ly1_out_63
  PIN s_VMM_WTA_out_10
    DIRECTION INOUT ;
    USE SIGNAL ;
    PORT
      LAYER METAL3 ;
        RECT 998.76 0.0 1000.16 2.8 ;
    END
  END s_VMM_WTA_out_10
  PIN s_FNN_diocon_dbg
    DIRECTION INOUT ;
    USE SIGNAL ;
    PORT
      LAYER METAL3 ;
        RECT 2707.71 0.0 2709.11 2.8 ;
    END
  END s_FNN_diocon_dbg
END FullyCon_NN

MACRO TSMC350nm_LVLShift_x16
  PIN OUT<2>
    DIRECTION INOUT ;
    USE SIGNAL ;
    PORT
      LAYER METAL2 ;
        RECT 30.67 0.0 32.07 0.85 ;
    END
  END OUT<2>
  PIN OUT<15>
    DIRECTION INOUT ;
    USE SIGNAL ;
    PORT
      LAYER METAL2 ;
        RECT 171.23 0.0 172.63 0.85 ;
    END
  END OUT<15>
  PIN OUT<13>
    DIRECTION INOUT ;
    USE SIGNAL ;
    PORT
      LAYER METAL2 ;
        RECT 148.97 0.0 150.37 0.85 ;
    END
  END OUT<13>
  PIN OUT<14>
    DIRECTION INOUT ;
    USE SIGNAL ;
    PORT
      LAYER METAL2 ;
        RECT 164.23 0.0 165.63 0.85 ;
    END
  END OUT<14>
  PIN OUT<11>
    DIRECTION INOUT ;
    USE SIGNAL ;
    PORT
      LAYER METAL2 ;
        RECT 126.71 0.0 128.11 0.85 ;
    END
  END OUT<11>
  PIN OUT<12>
    DIRECTION INOUT ;
    USE SIGNAL ;
    PORT
      LAYER METAL2 ;
        RECT 141.97 0.0 143.37 0.85 ;
    END
  END OUT<12>
  PIN OUT<9>
    DIRECTION INOUT ;
    USE SIGNAL ;
    PORT
      LAYER METAL2 ;
        RECT 104.45 0.0 105.85 0.85 ;
    END
  END OUT<9>
  PIN OUT<10>
    DIRECTION INOUT ;
    USE SIGNAL ;
    PORT
      LAYER METAL2 ;
        RECT 119.71 0.0 121.11 0.85 ;
    END
  END OUT<10>
  PIN OUT<7>
    DIRECTION INOUT ;
    USE SIGNAL ;
    PORT
      LAYER METAL2 ;
        RECT 82.19 0.0 83.59 0.85 ;
    END
  END OUT<7>
  PIN OUT<8>
    DIRECTION INOUT ;
    USE SIGNAL ;
    PORT
      LAYER METAL2 ;
        RECT 97.45 0.0 98.85 0.85 ;
    END
  END OUT<8>
  PIN OUT<5>
    DIRECTION INOUT ;
    USE SIGNAL ;
    PORT
      LAYER METAL2 ;
        RECT 59.93 0.0 61.33 0.85 ;
    END
  END OUT<5>
  PIN OUT<6>
    DIRECTION INOUT ;
    USE SIGNAL ;
    PORT
      LAYER METAL2 ;
        RECT 75.19 0.0 76.59 0.85 ;
    END
  END OUT<6>
  PIN OUT<3>
    DIRECTION INOUT ;
    USE SIGNAL ;
    PORT
      LAYER METAL2 ;
        RECT 37.67 0.0 39.07 0.85 ;
    END
  END OUT<3>
  PIN OUT<4>
    DIRECTION INOUT ;
    USE SIGNAL ;
    PORT
      LAYER METAL2 ;
        RECT 52.93 0.0 54.33 0.85 ;
    END
  END OUT<4>
  PIN Vin<12>
    DIRECTION INOUT ;
    USE SIGNAL ;
    PORT
      LAYER METAL2 ;
        RECT 141.4 31.5 142.82 32.25 ;
    END
  END Vin<12>
  PIN Vin<1>
    DIRECTION INOUT ;
    USE SIGNAL ;
    PORT
      LAYER METAL2 ;
        RECT 15.96 31.5 17.5 32.25 ;
    END
  END Vin<1>
  PIN Vin<3>
    DIRECTION INOUT ;
    USE SIGNAL ;
    PORT
      LAYER METAL2 ;
        RECT 38.22 31.5 39.9 32.25 ;
    END
  END Vin<3>
  PIN Vin<7>
    DIRECTION INOUT ;
    USE SIGNAL ;
    PORT
      LAYER METAL2 ;
        RECT 82.74 31.5 84.7 32.25 ;
    END
  END Vin<7>
  PIN Vin<15>
    DIRECTION INOUT ;
    USE SIGNAL ;
    PORT
      LAYER METAL2 ;
        RECT 171.78 31.5 173.6 32.25 ;
    END
  END Vin<15>
  PIN OUT<0>
    DIRECTION INOUT ;
    USE SIGNAL ;
    PORT
      LAYER METAL2 ;
        RECT 8.41 0.0 9.81 0.85 ;
    END
  END OUT<0>
  PIN VINJ
    DIRECTION INOUT ;
    USE SIGNAL ;
    PORT
      LAYER METAL2 ;
        RECT 0.0 18.01 1.4 19.6 ;
    END
  END VINJ
  PIN Vin<0>
    DIRECTION INOUT ;
    USE SIGNAL ;
    PORT
      LAYER METAL2 ;
        RECT 7.7 31.5 9.26 32.25 ;
    END
  END Vin<0>
  PIN OUT<1>
    DIRECTION INOUT ;
    USE SIGNAL ;
    PORT
      LAYER METAL2 ;
        RECT 15.41 0.0 16.81 0.85 ;
    END
  END OUT<1>
  PIN DVDD
    DIRECTION INOUT ;
    USE SIGNAL ;
    PORT
      LAYER METAL2 ;
        RECT 0.0 28.0 1.4 29.59 ;
    END
  END DVDD
  PIN Vin<2>
    DIRECTION INOUT ;
    USE SIGNAL ;
    PORT
      LAYER METAL2 ;
        RECT 30.1 31.5 31.52 32.25 ;
    END
  END Vin<2>
  PIN Vin<13>
    DIRECTION INOUT ;
    USE SIGNAL ;
    PORT
      LAYER METAL2 ;
        RECT 149.52 31.5 151.2 32.25 ;
    END
  END Vin<13>
  PIN Vin<11>
    DIRECTION INOUT ;
    USE SIGNAL ;
    PORT
      LAYER METAL2 ;
        RECT 127.26 31.5 128.8 32.25 ;
    END
  END Vin<11>
  PIN Vin<9>
    DIRECTION INOUT ;
    USE SIGNAL ;
    PORT
      LAYER METAL2 ;
        RECT 105.0 31.5 106.4 32.25 ;
    END
  END Vin<9>
  PIN Vin<5>
    DIRECTION INOUT ;
    USE SIGNAL ;
    PORT
      LAYER METAL2 ;
        RECT 60.48 31.5 62.3 32.25 ;
    END
  END Vin<5>
  PIN Vin<8>
    DIRECTION INOUT ;
    USE SIGNAL ;
    PORT
      LAYER METAL2 ;
        RECT 96.6 31.5 98.3 32.25 ;
    END
  END Vin<8>
  PIN Vin<10>
    DIRECTION INOUT ;
    USE SIGNAL ;
    PORT
      LAYER METAL2 ;
        RECT 119.0 31.5 120.56 32.25 ;
    END
  END Vin<10>
  PIN Vin<6>
    DIRECTION INOUT ;
    USE SIGNAL ;
    PORT
      LAYER METAL2 ;
        RECT 74.2 31.5 76.04 32.25 ;
    END
  END Vin<6>
  PIN Vin<4>
    DIRECTION INOUT ;
    USE SIGNAL ;
    PORT
      LAYER METAL2 ;
        RECT 52.5 31.5 53.9 32.25 ;
    END
  END Vin<4>
  PIN Vin<14>
    DIRECTION INOUT ;
    USE SIGNAL ;
    PORT
      LAYER METAL2 ;
        RECT 163.1 31.5 165.08 32.25 ;
    END
  END Vin<14>
  PIN GND
    DIRECTION INOUT ;
    USE SIGNAL ;
    PORT
      LAYER METAL1 ;
        RECT 0.0 23.81 1.4 25.2 ;
    END
  END GND
END TSMC350nm_LVLShift_x16

MACRO TSMC350nm_DigBuffer_x2
  PIN GND
    DIRECTION INOUT ;
    USE SIGNAL ;
    PORT
      LAYER METAL2 ;
        RECT 9.1 0.0 10.5 1.2 ;
    END
  END GND
  PIN VINJ
    DIRECTION INOUT ;
    USE SIGNAL ;
    PORT
      LAYER METAL2 ;
        RECT 36.4 0.0 37.8 1.03 ;
    END
  END VINJ
  PIN Out<1>
    DIRECTION INOUT ;
    USE SIGNAL ;
    PORT
      LAYER METAL2 ;
        RECT 28.7 0.0 30.1 1.2 ;
    END
  END Out<1>
  PIN Out<0>
    DIRECTION INOUT ;
    USE SIGNAL ;
    PORT
      LAYER METAL2 ;
        RECT 17.5 0.0 18.9 1.2 ;
    END
  END Out<0>
  PIN In<1>
    DIRECTION INOUT ;
    USE SIGNAL ;
    PORT
      LAYER METAL1 ;
        RECT 36.4 10.96 37.8 11.74 ;
    END
  END In<1>
  PIN In<0>
    DIRECTION INOUT ;
    USE SIGNAL ;
    PORT
      LAYER METAL1 ;
        RECT 9.8 10.96 11.2 11.74 ;
    END
  END In<0>
END TSMC350nm_DigBuffer_x2

MACRO TSMC350nm_4TGate_ST_BMatrix
  PIN In<0>
    DIRECTION INOUT ;
    USE SIGNAL ;
    PORT
      LAYER METAL1 ;
        RECT 0.0 17.5 0.27 18.0 ;
    END
  END In<0>
  PIN In<1>
    DIRECTION INOUT ;
    USE SIGNAL ;
    PORT
      LAYER METAL1 ;
        RECT 0.0 14.7 0.38 15.2 ;
    END
  END In<1>
  PIN In<2>
    DIRECTION INOUT ;
    USE SIGNAL ;
    PORT
      LAYER METAL1 ;
        RECT 0.0 7.0 0.36 7.5 ;
    END
  END In<2>
  PIN In<3>
    DIRECTION INOUT ;
    USE SIGNAL ;
    PORT
      LAYER METAL1 ;
        RECT 0.0 3.5 0.3 4.0 ;
    END
  END In<3>
  PIN A<0>
    DIRECTION INOUT ;
    USE SIGNAL ;
    PORT
      LAYER METAL1 ;
        RECT 10.6 17.6 12.0 18.9 ;
    END
  END A<0>
  PIN A<1>
    DIRECTION INOUT ;
    USE SIGNAL ;
    PORT
      LAYER METAL1 ;
        RECT 10.6 14.9 12.0 16.2 ;
    END
  END A<1>
  PIN A<2>
    DIRECTION INOUT ;
    USE SIGNAL ;
    PORT
      LAYER METAL1 ;
        RECT 10.6 6.8 12.0 8.1 ;
    END
  END A<2>
  PIN A<3>
    DIRECTION INOUT ;
    USE SIGNAL ;
    PORT
      LAYER METAL1 ;
        RECT 10.6 4.1 12.0 5.4 ;
    END
  END A<3>
  PIN P<0>
    DIRECTION INOUT ;
    USE SIGNAL ;
    PORT
      LAYER METAL1 ;
        RECT 10.6 20.3 12.0 21.6 ;
    END
  END P<0>
  PIN P<1>
    DIRECTION INOUT ;
    USE SIGNAL ;
    PORT
      LAYER METAL1 ;
        RECT 10.6 12.2 12.0 13.5 ;
    END
  END P<1>
  PIN P<2>
    DIRECTION INOUT ;
    USE SIGNAL ;
    PORT
      LAYER METAL1 ;
        RECT 10.6 9.5 12.0 10.8 ;
    END
  END P<2>
  PIN P<3>
    DIRECTION INOUT ;
    USE SIGNAL ;
    PORT
      LAYER METAL1 ;
        RECT 10.6 1.4 12.0 2.7 ;
    END
  END P<3>
  PIN GND_b
    DIRECTION INOUT ;
    USE SIGNAL ;
    PORT
      LAYER METAL2 ;
        RECT 6.35 0.0 7.25 0.88 ;
    END
  END GND_b
  PIN Prog_b
    DIRECTION INOUT ;
    USE SIGNAL ;
    PORT
      LAYER METAL2 ;
        RECT 4.1 0.0 4.7 0.78 ;
    END
  END Prog_b
  PIN VDD_b
    DIRECTION INOUT ;
    USE SIGNAL ;
    PORT
      LAYER METAL2 ;
        RECT 1.81 0.0 2.71 0.71 ;
    END
  END VDD_b
  PIN Prog
    DIRECTION INOUT ;
    USE SIGNAL ;
    PORT
      LAYER METAL2 ;
        RECT 4.1 21.3 4.7 22.0 ;
    END
  END Prog
  PIN VDD
    DIRECTION INOUT ;
    USE SIGNAL ;
    PORT
      LAYER METAL2 ;
        RECT 1.81 21.3 2.71 22.0 ;
    END
  END VDD
  PIN GND
    DIRECTION INOUT ;
    USE SIGNAL ;
    PORT
      LAYER METAL2 ;
        RECT 6.35 21.3 7.25 22.0 ;
    END
  END GND
END TSMC350nm_4TGate_ST_BMatrix

MACRO TSMC350nm_VinjDecode2to4_vtile_spacing
END TSMC350nm_VinjDecode2to4_vtile_spacing

MACRO TSMC350nm_VinjDecode2to4_vtile_D_bridge
END TSMC350nm_VinjDecode2to4_vtile_D_bridge

MACRO TSMC350nm_VinjDecode2to4_vtile
  PIN Vinj
    DIRECTION INOUT ;
    USE SIGNAL ;
    PORT
      LAYER METAL1 ;
        RECT 7.78 11.04 9.06 11.45 ;
    END
  END Vinj
  PIN OUT<0>
    DIRECTION INOUT ;
    USE SIGNAL ;
    PORT
      LAYER METAL1 ;
        RECT 19.66 18.91 20.11 19.59 ;
    END
  END OUT<0>
  PIN OUT<1>
    DIRECTION INOUT ;
    USE SIGNAL ;
    PORT
      LAYER METAL1 ;
        RECT 19.66 13.41 20.12 14.1 ;
    END
  END OUT<1>
  PIN OUT<2>
    DIRECTION INOUT ;
    USE SIGNAL ;
    PORT
      LAYER METAL1 ;
        RECT 19.66 7.92 20.11 8.59 ;
    END
  END OUT<2>
  PIN OUT<3>
    DIRECTION INOUT ;
    USE SIGNAL ;
    PORT
      LAYER METAL1 ;
        RECT 19.66 2.41 20.11 3.09 ;
    END
  END OUT<3>
  PIN ENABLE
    DIRECTION INOUT ;
    USE SIGNAL ;
    PORT
      LAYER METAL1 ;
        RECT 0.01 3.48 0.71 4.21 ;
    END
  END ENABLE
  PIN GND
    DIRECTION INOUT ;
    USE SIGNAL ;
    PORT
      LAYER METAL1 ;
        RECT 19.52 5.0 20.12 5.99 ;
    END
  END GND
  PIN VINJ
    DIRECTION INOUT ;
    USE SIGNAL ;
    PORT
      LAYER METAL1 ;
        RECT 19.15 21.56 20.05 21.96 ;
    END
  END VINJ
  PIN IN<1>
    DIRECTION INOUT ;
    USE SIGNAL ;
    PORT
      LAYER METAL2 ;
        RECT 6.56 20.89 7.5 22.0 ;
    END
  END IN<1>
  PIN IN<0>
    DIRECTION INOUT ;
    USE SIGNAL ;
    PORT
      LAYER METAL2 ;
        RECT 3.9 20.96 4.5 22.0 ;
    END
  END IN<0>
END TSMC350nm_VinjDecode2to4_vtile

MACRO TSMC350nm_VinjDecode2to4_vtile_C_bridge
END TSMC350nm_VinjDecode2to4_vtile_C_bridge

MACRO TSMC350nm_VinjDecode2to4_vtile_B_bridge
END TSMC350nm_VinjDecode2to4_vtile_B_bridge

MACRO TSMC350nm_VinjDecode2to4_vtile_A_bridge
END TSMC350nm_VinjDecode2to4_vtile_A_bridge

MACRO TSMC350nm_drainSelect_progrundrains
  PIN prog_drain<3>
    DIRECTION INOUT ;
    USE SIGNAL ;
    PORT
      LAYER METAL1 ;
        RECT 30.93 0.93 31.86 1.43 ;
    END
  END prog_drain<3>
  PIN prog_drain<2>
    DIRECTION INOUT ;
    USE SIGNAL ;
    PORT
      LAYER METAL1 ;
        RECT 30.97 9.62 31.86 10.12 ;
    END
  END prog_drain<2>
  PIN prog_drain<1>
    DIRECTION INOUT ;
    USE SIGNAL ;
    PORT
      LAYER METAL1 ;
        RECT 31.0 13.97 31.86 14.47 ;
    END
  END prog_drain<1>
  PIN run_drain<3>
    DIRECTION INOUT ;
    USE SIGNAL ;
    PORT
      LAYER METAL1 ;
        RECT 31.01 2.45 31.86 2.95 ;
    END
  END run_drain<3>
  PIN run_drain<2>
    DIRECTION INOUT ;
    USE SIGNAL ;
    PORT
      LAYER METAL1 ;
        RECT 30.94 5.31 31.86 5.81 ;
    END
  END run_drain<2>
  PIN prog_drain<0>
    DIRECTION INOUT ;
    USE SIGNAL ;
    PORT
      LAYER METAL1 ;
        RECT 31.12 20.75 31.86 21.25 ;
    END
  END prog_drain<0>
  PIN GND
    DIRECTION INOUT ;
    USE SIGNAL ;
    PORT
      LAYER METAL2 ;
        RECT 4.19 21.33 4.99 22.0 ;
    END
  END GND
  PIN VINJ
    DIRECTION INOUT ;
    USE SIGNAL ;
    PORT
      LAYER METAL1 ;
        RECT 1.4 21.5 2.8 22.0 ;
    END
  END VINJ
  PIN run_drain<0>
    DIRECTION INOUT ;
    USE SIGNAL ;
    PORT
      LAYER METAL1 ;
        RECT 31.01 19.56 31.86 20.06 ;
    END
  END run_drain<0>
  PIN run_drain<1>
    DIRECTION INOUT ;
    USE SIGNAL ;
    PORT
      LAYER METAL1 ;
        RECT 31.04 16.75 31.86 17.24 ;
    END
  END run_drain<1>
  PIN SELECT<3>
    DIRECTION INOUT ;
    USE SIGNAL ;
    PORT
      LAYER METAL1 ;
        RECT 0.0 2.54 0.67 2.97 ;
    END
  END SELECT<3>
  PIN SELET<2>
    DIRECTION INOUT ;
    USE SIGNAL ;
    PORT
      LAYER METAL1 ;
        RECT 0.0 8.03 0.67 8.46 ;
    END
  END SELET<2>
  PIN SELECT<1>
    DIRECTION INOUT ;
    USE SIGNAL ;
    PORT
      LAYER METAL1 ;
        RECT 0.0 13.54 0.67 13.97 ;
    END
  END SELECT<1>
  PIN SELECT<0>
    DIRECTION INOUT ;
    USE SIGNAL ;
    PORT
      LAYER METAL1 ;
        RECT 0.0 18.9 0.67 19.6 ;
    END
  END SELECT<0>
  PIN VINJ_b
    DIRECTION INOUT ;
    USE SIGNAL ;
    PORT
      LAYER METAL2 ;
        RECT 21.94 0.0 23.29 0.58 ;
    END
  END VINJ_b
  PIN GND_b
    DIRECTION INOUT ;
    USE SIGNAL ;
    PORT
      LAYER METAL2 ;
        RECT 17.16 0.0 18.16 0.58 ;
    END
  END GND_b
  PIN run_drainrail
    DIRECTION INOUT ;
    USE SIGNAL ;
    PORT
      LAYER METAL2 ;
        RECT 27.01 21.19 27.71 22.0 ;
    END
  END run_drainrail
  PIN prog_drainrail
    DIRECTION INOUT ;
    USE SIGNAL ;
    PORT
      LAYER METAL2 ;
        RECT 7.36 21.34 8.16 22.0 ;
    END
  END prog_drainrail
END TSMC350nm_drainSelect_progrundrains

MACRO TSMC350nm_4TGate_ST_draincutoff
  PIN In<0>
    DIRECTION INOUT ;
    USE SIGNAL ;
    PORT
      LAYER METAL1 ;
        RECT 9.96 17.5 10.6 18.45 ;
    END
  END In<0>
  PIN In<1>
    DIRECTION INOUT ;
    USE SIGNAL ;
    PORT
      LAYER METAL1 ;
        RECT 9.91 14.7 10.6 15.93 ;
    END
  END In<1>
  PIN In<2>
    DIRECTION INOUT ;
    USE SIGNAL ;
    PORT
      LAYER METAL1 ;
        RECT 10.01 6.9 10.6 7.8 ;
    END
  END In<2>
  PIN In<3>
    DIRECTION INOUT ;
    USE SIGNAL ;
    PORT
      LAYER METAL1 ;
        RECT 10.02 3.5 10.6 4.3 ;
    END
  END In<3>
  PIN A<0>
    DIRECTION INOUT ;
    USE SIGNAL ;
    PORT
      LAYER METAL1 ;
        RECT 0.0 19.56 1.4 20.06 ;
    END
  END A<0>
  PIN A<1>
    DIRECTION INOUT ;
    USE SIGNAL ;
    PORT
      LAYER METAL1 ;
        RECT 0.0 16.75 1.4 17.25 ;
    END
  END A<1>
  PIN A<2>
    DIRECTION INOUT ;
    USE SIGNAL ;
    PORT
      LAYER METAL1 ;
        RECT 0.0 5.3 1.4 5.8 ;
    END
  END A<2>
  PIN A<3>
    DIRECTION INOUT ;
    USE SIGNAL ;
    PORT
      LAYER METAL1 ;
        RECT 0.0 2.45 1.4 2.95 ;
    END
  END A<3>
  PIN P<0>
    DIRECTION INOUT ;
    USE SIGNAL ;
    PORT
      LAYER METAL1 ;
        RECT 0.0 20.75 1.4 21.25 ;
    END
  END P<0>
  PIN P<1>
    DIRECTION INOUT ;
    USE SIGNAL ;
    PORT
      LAYER METAL1 ;
        RECT 0.0 13.97 1.4 14.47 ;
    END
  END P<1>
  PIN P<2>
    DIRECTION INOUT ;
    USE SIGNAL ;
    PORT
      LAYER METAL1 ;
        RECT 0.0 9.62 1.4 10.12 ;
    END
  END P<2>
  PIN P<3>
    DIRECTION INOUT ;
    USE SIGNAL ;
    PORT
      LAYER METAL1 ;
        RECT 0.0 0.93 1.4 1.43 ;
    END
  END P<3>
  PIN PR<0>
    DIRECTION INOUT ;
    USE SIGNAL ;
    PORT
      LAYER METAL1 ;
        RECT 10.0 20.3 10.6 21.25 ;
    END
  END PR<0>
  PIN PR<1>
    DIRECTION INOUT ;
    USE SIGNAL ;
    PORT
      LAYER METAL1 ;
        RECT 10.13 11.9 10.6 12.8 ;
    END
  END PR<1>
  PIN PR<2>
    DIRECTION INOUT ;
    USE SIGNAL ;
    PORT
      LAYER METAL1 ;
        RECT 10.0 9.4 10.6 10.3 ;
    END
  END PR<2>
  PIN PR<3>
    DIRECTION INOUT ;
    USE SIGNAL ;
    PORT
      LAYER METAL1 ;
        RECT 10.0 0.7 10.6 1.6 ;
    END
  END PR<3>
  PIN VDD_b
    DIRECTION INOUT ;
    USE SIGNAL ;
    PORT
      LAYER METAL2 ;
        RECT 7.89 0.0 8.79 0.54 ;
    END
  END VDD_b
  PIN RUN
    DIRECTION INOUT ;
    USE SIGNAL ;
    PORT
      LAYER METAL2 ;
        RECT 5.9 21.13 6.5 22.0 ;
    END
  END RUN
  PIN VDD
    DIRECTION INOUT ;
    USE SIGNAL ;
    PORT
      LAYER METAL2 ;
        RECT 7.89 21.3 8.79 22.0 ;
    END
  END VDD
  PIN GND
    DIRECTION INOUT ;
    USE SIGNAL ;
    PORT
      LAYER METAL2 ;
        RECT 3.35 21.3 4.25 22.0 ;
    END
  END GND
  PIN GND_b
    DIRECTION INOUT ;
    USE SIGNAL ;
    PORT
      LAYER METAL2 ;
        RECT 3.35 0.0 4.25 0.73 ;
    END
  END GND_b
  PIN RUN_b
    DIRECTION INOUT ;
    USE SIGNAL ;
    PORT
      LAYER METAL2 ;
        RECT 5.9 0.0 6.5 0.71 ;
    END
  END RUN_b
END TSMC350nm_4TGate_ST_draincutoff

MACRO TSMC350nm_IndirectSwitches
  PIN GND_B<1>
    DIRECTION INOUT ;
    USE SIGNAL ;
    PORT
      LAYER METAL2 ;
        RECT 15.41 0.0 16.01 0.85 ;
    END
  END GND_B<1>
  PIN GND_B<0>
    DIRECTION INOUT ;
    USE SIGNAL ;
    PORT
      LAYER METAL2 ;
        RECT 11.2 0.0 11.8 0.85 ;
    END
  END GND_B<0>
  PIN GND
    DIRECTION INOUT ;
    USE SIGNAL ;
    PORT
      LAYER METAL2 ;
        RECT 11.2 3.21 11.8 3.6 ;
    END
  END GND
  PIN GND_T
    DIRECTION INOUT ;
    USE SIGNAL ;
    PORT
      LAYER METAL2 ;
        RECT 15.4 21.0 16.2 22.0 ;
    END
  END GND_T
  PIN VINJ_T
    DIRECTION INOUT ;
    USE SIGNAL ;
    PORT
      LAYER METAL2 ;
        RECT 6.3 21.04 7.32 22.0 ;
    END
  END VINJ_T
  PIN VDD<1>
    DIRECTION INOUT ;
    USE SIGNAL ;
    PORT
      LAYER METAL2 ;
        RECT 24.5 0.0 25.1 0.75 ;
    END
  END VDD<1>
  PIN VTUN
    DIRECTION INOUT ;
    USE SIGNAL ;
    PORT
      LAYER METAL2 ;
        RECT 13.3 0.0 13.9 0.82 ;
    END
  END VTUN
  PIN VINJ
    DIRECTION INOUT ;
    USE SIGNAL ;
    PORT
      LAYER METAL2 ;
        RECT 4.2 0.0 4.8 1.0 ;
    END
  END VINJ
  PIN VDD<0>
    DIRECTION INOUT ;
    USE SIGNAL ;
    PORT
      LAYER METAL2 ;
        RECT 2.1 0.0 2.7 1.09 ;
    END
  END VDD<0>
  PIN Vg<0>
    DIRECTION INOUT ;
    USE SIGNAL ;
    PORT
      LAYER METAL2 ;
        RECT 8.4 0.005 9.0 0.825 ;
    END
  END Vg<0>
  PIN CTRL_B<0>
    DIRECTION INOUT ;
    USE SIGNAL ;
    PORT
      LAYER METAL2 ;
        RECT 6.3 0.01 6.9 0.76 ;
    END
  END CTRL_B<0>
  PIN CTRL_B<1>
    DIRECTION INOUT ;
    USE SIGNAL ;
    PORT
      LAYER METAL2 ;
        RECT 20.3 0.01 20.9 0.75 ;
    END
  END CTRL_B<1>
  PIN Vg<1>
    DIRECTION INOUT ;
    USE SIGNAL ;
    PORT
      LAYER METAL2 ;
        RECT 18.2 0.0 18.8 0.76 ;
    END
  END Vg<1>
  PIN decode<0>
    DIRECTION INOUT ;
    USE SIGNAL ;
    PORT
      LAYER METAL2 ;
        RECT 3.46 21.16 4.8 22.0 ;
    END
  END decode<0>
  PIN RUN_IN<1>
    DIRECTION INOUT ;
    USE SIGNAL ;
    PORT
      LAYER METAL2 ;
        RECT 17.5 21.01 18.1 22.0 ;
    END
  END RUN_IN<1>
  PIN RUN_IN<0>
    DIRECTION INOUT ;
    USE SIGNAL ;
    PORT
      LAYER METAL2 ;
        RECT 10.5 20.9 11.1 22.0 ;
    END
  END RUN_IN<0>
  PIN VPWR<1>
    DIRECTION INOUT ;
    USE SIGNAL ;
    PORT
      LAYER METAL2 ;
        RECT 21.7 21.08 22.3 22.0 ;
    END
  END VPWR<1>
  PIN decode<1>
    DIRECTION INOUT ;
    USE SIGNAL ;
    PORT
      LAYER METAL2 ;
        RECT 23.8 21.09 25.0 22.0 ;
    END
  END decode<1>
  PIN VPWR<0>
    DIRECTION INOUT ;
    USE SIGNAL ;
    PORT
      LAYER METAL2 ;
        RECT 1.71 21.21 2.43 22.0 ;
    END
  END VPWR<0>
  PIN VTUN_T
    DIRECTION INOUT ;
    USE SIGNAL ;
    PORT
      LAYER METAL2 ;
        RECT 12.6 21.12 13.7 22.0 ;
    END
  END VTUN_T
  PIN vtun_r
    DIRECTION INOUT ;
    USE SIGNAL ;
    PORT
      LAYER METAL1 ;
        RECT 26.17 0.9 27.46 2.17 ;
    END
  END vtun_r
  PIN vgsel_r
    DIRECTION INOUT ;
    USE SIGNAL ;
    PORT
      LAYER METAL1 ;
        RECT 26.52 3.15 27.46 4.45 ;
    END
  END vgsel_r
  PIN prog_r
    DIRECTION INOUT ;
    USE SIGNAL ;
    PORT
      LAYER METAL1 ;
        RECT 26.59 9.15 27.46 10.55 ;
    END
  END prog_r
  PIN run_r
    DIRECTION INOUT ;
    USE SIGNAL ;
    PORT
      LAYER METAL1 ;
        RECT 26.28 6.05 27.46 7.29 ;
    END
  END run_r
  PIN RUN
    DIRECTION INOUT ;
    USE SIGNAL ;
    PORT
      LAYER METAL1 ;
        RECT 0.0 6.05 0.91 7.29 ;
    END
  END RUN
  PIN PROG
    DIRECTION INOUT ;
    USE SIGNAL ;
    PORT
      LAYER METAL1 ;
        RECT 0.0 9.15 0.87 10.55 ;
    END
  END PROG
  PIN Vgsel
    DIRECTION INOUT ;
    USE SIGNAL ;
    PORT
      LAYER METAL1 ;
        RECT 0.0 3.72 0.91 4.45 ;
    END
  END Vgsel
  PIN vtun_l
    DIRECTION INOUT ;
    USE SIGNAL ;
    PORT
      LAYER METAL1 ;
        RECT 0.0 0.9 1.31 1.88 ;
    END
  END vtun_l
END TSMC350nm_IndirectSwitches

MACRO TSMC350nm_AnalogBuffer
  PIN Vd_P
    DIRECTION INOUT ;
    USE SIGNAL ;
    PORT
      LAYER METAL1 ;
        RECT 0.0 9.34 1.4 10.74 ;
    END
  END Vd_P
  PIN Vin
    DIRECTION INOUT ;
    USE SIGNAL ;
    PORT
      LAYER METAL1 ;
        RECT 0.0 1.34 1.4 2.74 ;
    END
  END Vin
  PIN VDD_b
    DIRECTION INOUT ;
    USE SIGNAL ;
    PORT
      LAYER METAL2 ;
        RECT 78.18 0.0 79.58 1.4 ;
    END
  END VDD_b
  PIN GND_b
    DIRECTION INOUT ;
    USE SIGNAL ;
    PORT
      LAYER METAL2 ;
        RECT 43.36 0.0 44.76 1.4 ;
    END
  END GND_b
  PIN VTUN_b
    DIRECTION INOUT ;
    USE SIGNAL ;
    PORT
      LAYER METAL2 ;
        RECT 1.9 0.0 3.3 1.4 ;
    END
  END VTUN_b
  PIN Vg_b
    DIRECTION INOUT ;
    USE SIGNAL ;
    PORT
      LAYER METAL2 ;
        RECT 4.75 0.0 6.15 1.4 ;
    END
  END Vg_b
  PIN VINJ_b
    DIRECTION INOUT ;
    USE SIGNAL ;
    PORT
      LAYER METAL2 ;
        RECT 8.37 0.0 9.77 1.4 ;
    END
  END VINJ_b
  PIN Vsel_b
    DIRECTION INOUT ;
    USE SIGNAL ;
    PORT
      LAYER METAL2 ;
        RECT 12.03 0.0 13.43 1.4 ;
    END
  END Vsel_b
  PIN Vout
    DIRECTION INOUT ;
    USE SIGNAL ;
    PORT
      LAYER METAL2 ;
        RECT 87.38 16.98 88.78 18.38 ;
    END
  END Vout
  PIN VDD
    DIRECTION INOUT ;
    USE SIGNAL ;
    PORT
      LAYER METAL2 ;
        RECT 78.18 20.6 79.58 22.0 ;
    END
  END VDD
  PIN GND
    DIRECTION INOUT ;
    USE SIGNAL ;
    PORT
      LAYER METAL2 ;
        RECT 43.36 20.6 44.76 22.0 ;
    END
  END GND
  PIN Vsel
    DIRECTION INOUT ;
    USE SIGNAL ;
    PORT
      LAYER METAL2 ;
        RECT 12.03 20.6 13.43 22.0 ;
    END
  END Vsel
  PIN VINJ
    DIRECTION INOUT ;
    USE SIGNAL ;
    PORT
      LAYER METAL2 ;
        RECT 8.37 20.6 9.77 22.0 ;
    END
  END VINJ
  PIN Vg
    DIRECTION INOUT ;
    USE SIGNAL ;
    PORT
      LAYER METAL2 ;
        RECT 4.75 20.6 6.15 22.0 ;
    END
  END Vg
  PIN VTUN
    DIRECTION INOUT ;
    USE SIGNAL ;
    PORT
      LAYER METAL2 ;
        RECT 1.9 20.6 3.3 22.0 ;
    END
  END VTUN
END TSMC350nm_AnalogBuffer

MACRO tile_analog_frame
  PIN n_M_VGPROG
    DIRECTION INOUT ;
    USE SIGNAL ;
    PORT
      LAYER METAL3 ;
        RECT 27.3 4562.2 28.7 4565.0 ;
    END
  END n_M_VGPROG
  PIN n_M_VGRUN
    DIRECTION INOUT ;
    USE SIGNAL ;
    PORT
      LAYER METAL3 ;
        RECT 55.3 4562.2 56.7 4565.0 ;
    END
  END n_M_VGRUN
  PIN n_M_mmio_rg_5<0>
    DIRECTION INOUT ;
    USE SIGNAL ;
    PORT
      LAYER METAL3 ;
        RECT 83.3 4562.2 84.7 4565.0 ;
    END
  END n_M_mmio_rg_5<0>
  PIN n_M_mmio_rg_5<1>
    DIRECTION INOUT ;
    USE SIGNAL ;
    PORT
      LAYER METAL3 ;
        RECT 111.3 4562.2 112.7 4565.0 ;
    END
  END n_M_mmio_rg_5<1>
  PIN n_M_mmio_rg_5<2>
    DIRECTION INOUT ;
    USE SIGNAL ;
    PORT
      LAYER METAL3 ;
        RECT 139.3 4562.2 140.7 4565.0 ;
    END
  END n_M_mmio_rg_5<2>
  PIN n_M_mmio_rg_5<3>
    DIRECTION INOUT ;
    USE SIGNAL ;
    PORT
      LAYER METAL3 ;
        RECT 167.3 4562.2 168.7 4565.0 ;
    END
  END n_M_mmio_rg_5<3>
  PIN n_M_mmio_rg_5<4>
    DIRECTION INOUT ;
    USE SIGNAL ;
    PORT
      LAYER METAL3 ;
        RECT 195.3 4562.2 196.7 4565.0 ;
    END
  END n_M_mmio_rg_5<4>
  PIN n_M_mmio_rg_5<5>
    DIRECTION INOUT ;
    USE SIGNAL ;
    PORT
      LAYER METAL3 ;
        RECT 223.3 4562.2 224.7 4565.0 ;
    END
  END n_M_mmio_rg_5<5>
  PIN n_M_Sys_Drln<0>
    DIRECTION INOUT ;
    USE SIGNAL ;
    PORT
      LAYER METAL3 ;
        RECT 251.3 4562.2 252.7 4565.0 ;
    END
  END n_M_Sys_Drln<0>
  PIN n_M_Sys_Drln<1>
    DIRECTION INOUT ;
    USE SIGNAL ;
    PORT
      LAYER METAL3 ;
        RECT 279.3 4562.2 280.7 4565.0 ;
    END
  END n_M_Sys_Drln<1>
  PIN n_M_Sig_RampADC_in<0>
    DIRECTION INOUT ;
    USE SIGNAL ;
    PORT
      LAYER METAL3 ;
        RECT 307.3 4562.2 308.7 4565.0 ;
    END
  END n_M_Sig_RampADC_in<0>
  PIN n_M_Sig_RampADC_in<1>
    DIRECTION INOUT ;
    USE SIGNAL ;
    PORT
      LAYER METAL3 ;
        RECT 335.3 4562.2 336.7 4565.0 ;
    END
  END n_M_Sig_RampADC_in<1>
  PIN n_M_Sig_RampADC_in<2>
    DIRECTION INOUT ;
    USE SIGNAL ;
    PORT
      LAYER METAL3 ;
        RECT 363.3 4562.2 364.7 4565.0 ;
    END
  END n_M_Sig_RampADC_in<2>
  PIN n_M_Sig_RampADC_in<3>
    DIRECTION INOUT ;
    USE SIGNAL ;
    PORT
      LAYER METAL3 ;
        RECT 391.3 4562.2 392.7 4565.0 ;
    END
  END n_M_Sig_RampADC_in<3>
  PIN n_M_mmio_rg_7_vinj<0>
    DIRECTION INOUT ;
    USE SIGNAL ;
    PORT
      LAYER METAL3 ;
        RECT 419.3 4562.2 420.7 4565.0 ;
    END
  END n_M_mmio_rg_7_vinj<0>
  PIN n_M_mmio_rg_7_vinj<1>
    DIRECTION INOUT ;
    USE SIGNAL ;
    PORT
      LAYER METAL3 ;
        RECT 447.3 4562.2 448.7 4565.0 ;
    END
  END n_M_mmio_rg_7_vinj<1>
  PIN n_M_mmio_rg_7_vinj<2>
    DIRECTION INOUT ;
    USE SIGNAL ;
    PORT
      LAYER METAL3 ;
        RECT 475.3 4562.2 476.7 4565.0 ;
    END
  END n_M_mmio_rg_7_vinj<2>
  PIN n_M_mmio_rg_7_vinj<3>
    DIRECTION INOUT ;
    USE SIGNAL ;
    PORT
      LAYER METAL3 ;
        RECT 503.3 4562.2 504.7 4565.0 ;
    END
  END n_M_mmio_rg_7_vinj<3>
  PIN n_M_mmio_rg_7_vinj<4>
    DIRECTION INOUT ;
    USE SIGNAL ;
    PORT
      LAYER METAL3 ;
        RECT 531.3 4562.2 532.7 4565.0 ;
    END
  END n_M_mmio_rg_7_vinj<4>
  PIN n_M_mmio_rg_7_vinj<5>
    DIRECTION INOUT ;
    USE SIGNAL ;
    PORT
      LAYER METAL3 ;
        RECT 559.3 4562.2 560.7 4565.0 ;
    END
  END n_M_mmio_rg_7_vinj<5>
  PIN n_M_mmio_rg_7_vinj<6>
    DIRECTION INOUT ;
    USE SIGNAL ;
    PORT
      LAYER METAL3 ;
        RECT 587.3 4562.2 588.7 4565.0 ;
    END
  END n_M_mmio_rg_7_vinj<6>
  PIN n_M_mmio_rg_7_vinj<7>
    DIRECTION INOUT ;
    USE SIGNAL ;
    PORT
      LAYER METAL3 ;
        RECT 615.3 4562.2 616.7 4565.0 ;
    END
  END n_M_mmio_rg_7_vinj<7>
  PIN n_M_mmio_rg_9<0>
    DIRECTION INOUT ;
    USE SIGNAL ;
    PORT
      LAYER METAL3 ;
        RECT 643.3 4562.2 644.7 4565.0 ;
    END
  END n_M_mmio_rg_9<0>
  PIN n_M_mmio_rg_9<1>
    DIRECTION INOUT ;
    USE SIGNAL ;
    PORT
      LAYER METAL3 ;
        RECT 671.3 4562.2 672.7 4565.0 ;
    END
  END n_M_mmio_rg_9<1>
  PIN n_M_mmio_rg_9<2>
    DIRECTION INOUT ;
    USE SIGNAL ;
    PORT
      LAYER METAL3 ;
        RECT 699.3 4562.2 700.7 4565.0 ;
    END
  END n_M_mmio_rg_9<2>
  PIN n_M_mmio_rg_9<3>
    DIRECTION INOUT ;
    USE SIGNAL ;
    PORT
      LAYER METAL3 ;
        RECT 727.3 4562.2 728.7 4565.0 ;
    END
  END n_M_mmio_rg_9<3>
  PIN n_M_mmio_rg_9<4>
    DIRECTION INOUT ;
    USE SIGNAL ;
    PORT
      LAYER METAL3 ;
        RECT 755.3 4562.2 756.7 4565.0 ;
    END
  END n_M_mmio_rg_9<4>
  PIN n_M_mmio_rg_9<5>
    DIRECTION INOUT ;
    USE SIGNAL ;
    PORT
      LAYER METAL3 ;
        RECT 783.3 4562.2 784.7 4565.0 ;
    END
  END n_M_mmio_rg_9<5>
  PIN n_M_mmio_rg_9<6>
    DIRECTION INOUT ;
    USE SIGNAL ;
    PORT
      LAYER METAL3 ;
        RECT 811.3 4562.2 812.7 4565.0 ;
    END
  END n_M_mmio_rg_9<6>
  PIN n_M_mmio_rg_9<7>
    DIRECTION INOUT ;
    USE SIGNAL ;
    PORT
      LAYER METAL3 ;
        RECT 839.3 4562.2 840.7 4565.0 ;
    END
  END n_M_mmio_rg_9<7>
  PIN n_M_mmio_rg_9<8>
    DIRECTION INOUT ;
    USE SIGNAL ;
    PORT
      LAYER METAL3 ;
        RECT 867.3 4562.2 868.7 4565.0 ;
    END
  END n_M_mmio_rg_9<8>
  PIN n_M_mmio_rg_9<9>
    DIRECTION INOUT ;
    USE SIGNAL ;
    PORT
      LAYER METAL3 ;
        RECT 895.3 4562.2 896.7 4565.0 ;
    END
  END n_M_mmio_rg_9<9>
  PIN n_M_mmio_rg_9<10>
    DIRECTION INOUT ;
    USE SIGNAL ;
    PORT
      LAYER METAL3 ;
        RECT 923.3 4562.2 924.7 4565.0 ;
    END
  END n_M_mmio_rg_9<10>
  PIN n_M_mmio_rg_9<11>
    DIRECTION INOUT ;
    USE SIGNAL ;
    PORT
      LAYER METAL3 ;
        RECT 951.3 4562.2 952.7 4565.0 ;
    END
  END n_M_mmio_rg_9<11>
  PIN n_M_mmio_rg_9<12>
    DIRECTION INOUT ;
    USE SIGNAL ;
    PORT
      LAYER METAL3 ;
        RECT 979.3 4562.2 980.7 4565.0 ;
    END
  END n_M_mmio_rg_9<12>
  PIN n_M_mmio_rg_9<13>
    DIRECTION INOUT ;
    USE SIGNAL ;
    PORT
      LAYER METAL3 ;
        RECT 1007.3 4562.2 1008.7 4565.0 ;
    END
  END n_M_mmio_rg_9<13>
  PIN n_M_mmio_rg_9<14>
    DIRECTION INOUT ;
    USE SIGNAL ;
    PORT
      LAYER METAL3 ;
        RECT 1035.3 4562.2 1036.7 4565.0 ;
    END
  END n_M_mmio_rg_9<14>
  PIN n_M_mmio_rg_9<15>
    DIRECTION INOUT ;
    USE SIGNAL ;
    PORT
      LAYER METAL3 ;
        RECT 1063.3 4562.2 1064.7 4565.0 ;
    END
  END n_M_mmio_rg_9<15>
  PIN n_M_mmio_rg_10<0>
    DIRECTION INOUT ;
    USE SIGNAL ;
    PORT
      LAYER METAL3 ;
        RECT 1091.3 4562.2 1092.7 4565.0 ;
    END
  END n_M_mmio_rg_10<0>
  PIN n_M_mmio_rg_10<1>
    DIRECTION INOUT ;
    USE SIGNAL ;
    PORT
      LAYER METAL3 ;
        RECT 1119.3 4562.2 1120.7 4565.0 ;
    END
  END n_M_mmio_rg_10<1>
  PIN n_M_mmio_rg_10<2>
    DIRECTION INOUT ;
    USE SIGNAL ;
    PORT
      LAYER METAL3 ;
        RECT 1147.3 4562.2 1148.7 4565.0 ;
    END
  END n_M_mmio_rg_10<2>
  PIN n_M_mmio_rg_10<3>
    DIRECTION INOUT ;
    USE SIGNAL ;
    PORT
      LAYER METAL3 ;
        RECT 1175.3 4562.2 1176.7 4565.0 ;
    END
  END n_M_mmio_rg_10<3>
  PIN n_M_mmio_rg_10<4>
    DIRECTION INOUT ;
    USE SIGNAL ;
    PORT
      LAYER METAL3 ;
        RECT 1203.3 4562.2 1204.7 4565.0 ;
    END
  END n_M_mmio_rg_10<4>
  PIN n_M_mmio_rg_10<5>
    DIRECTION INOUT ;
    USE SIGNAL ;
    PORT
      LAYER METAL3 ;
        RECT 1231.3 4562.2 1232.7 4565.0 ;
    END
  END n_M_mmio_rg_10<5>
  PIN n_M_mmio_rg_10<6>
    DIRECTION INOUT ;
    USE SIGNAL ;
    PORT
      LAYER METAL3 ;
        RECT 1259.3 4562.2 1260.7 4565.0 ;
    END
  END n_M_mmio_rg_10<6>
  PIN n_M_mmio_rg_10<7>
    DIRECTION INOUT ;
    USE SIGNAL ;
    PORT
      LAYER METAL3 ;
        RECT 1287.3 4562.2 1288.7 4565.0 ;
    END
  END n_M_mmio_rg_10<7>
  PIN n_M_mmio_rg_10<8>
    DIRECTION INOUT ;
    USE SIGNAL ;
    PORT
      LAYER METAL3 ;
        RECT 1315.3 4562.2 1316.7 4565.0 ;
    END
  END n_M_mmio_rg_10<8>
  PIN n_M_mmio_rg_10<9>
    DIRECTION INOUT ;
    USE SIGNAL ;
    PORT
      LAYER METAL3 ;
        RECT 1343.3 4562.2 1344.7 4565.0 ;
    END
  END n_M_mmio_rg_10<9>
  PIN n_M_mmio_rg_10<10>
    DIRECTION INOUT ;
    USE SIGNAL ;
    PORT
      LAYER METAL3 ;
        RECT 1371.3 4562.2 1372.7 4565.0 ;
    END
  END n_M_mmio_rg_10<10>
  PIN n_M_mmio_rg_10<11>
    DIRECTION INOUT ;
    USE SIGNAL ;
    PORT
      LAYER METAL3 ;
        RECT 1399.3 4562.2 1400.7 4565.0 ;
    END
  END n_M_mmio_rg_10<11>
  PIN n_M_mmio_rg_10<12>
    DIRECTION INOUT ;
    USE SIGNAL ;
    PORT
      LAYER METAL3 ;
        RECT 1427.3 4562.2 1428.7 4565.0 ;
    END
  END n_M_mmio_rg_10<12>
  PIN n_M_mmio_rg_10<13>
    DIRECTION INOUT ;
    USE SIGNAL ;
    PORT
      LAYER METAL3 ;
        RECT 1455.3 4562.2 1456.7 4565.0 ;
    END
  END n_M_mmio_rg_10<13>
  PIN n_M_mmio_rg_10<14>
    DIRECTION INOUT ;
    USE SIGNAL ;
    PORT
      LAYER METAL3 ;
        RECT 1483.3 4562.2 1484.7 4565.0 ;
    END
  END n_M_mmio_rg_10<14>
  PIN n_M_mmio_rg_10<15>
    DIRECTION INOUT ;
    USE SIGNAL ;
    PORT
      LAYER METAL3 ;
        RECT 1511.3 4562.2 1512.7 4565.0 ;
    END
  END n_M_mmio_rg_10<15>
  PIN n_M_prog_hv
    DIRECTION INOUT ;
    USE SIGNAL ;
    PORT
      LAYER METAL3 ;
        RECT 1539.3 4562.2 1540.7 4565.0 ;
    END
  END n_M_prog_hv
  PIN n_M_run_hv
    DIRECTION INOUT ;
    USE SIGNAL ;
    PORT
      LAYER METAL3 ;
        RECT 1567.3 4562.2 1568.7 4565.0 ;
    END
  END n_M_run_hv
  PIN e_CP_AVDD_E
    DIRECTION INOUT ;
    USE SIGNAL ;
    PORT
      LAYER METAL3 ;
        RECT 6097.45 4535.6 6100.25 4537.0 ;
    END
  END e_CP_AVDD_E
  PIN e_CP_VINJ_E
    DIRECTION INOUT ;
    USE SIGNAL ;
    PORT
      LAYER METAL3 ;
        RECT 6097.45 4507.6 6100.25 4509.0 ;
    END
  END e_CP_VINJ_E
  PIN e_CP_GND_E_2
    DIRECTION INOUT ;
    USE SIGNAL ;
    PORT
      LAYER METAL3 ;
        RECT 6097.45 4479.6 6100.25 4481.0 ;
    END
  END e_CP_GND_E_2
  PIN e_CP_IO_E<0>
    DIRECTION INOUT ;
    USE SIGNAL ;
    PORT
      LAYER METAL3 ;
        RECT 6097.45 4451.6 6100.25 4453.0 ;
    END
  END e_CP_IO_E<0>
  PIN e_CP_IO_E<1>
    DIRECTION INOUT ;
    USE SIGNAL ;
    PORT
      LAYER METAL3 ;
        RECT 6097.45 4423.6 6100.25 4425.0 ;
    END
  END e_CP_IO_E<1>
  PIN e_CP_IO_E<2>
    DIRECTION INOUT ;
    USE SIGNAL ;
    PORT
      LAYER METAL3 ;
        RECT 6097.45 4395.6 6100.25 4397.0 ;
    END
  END e_CP_IO_E<2>
  PIN e_CP_IO_E<3>
    DIRECTION INOUT ;
    USE SIGNAL ;
    PORT
      LAYER METAL3 ;
        RECT 6097.45 4367.6 6100.25 4369.0 ;
    END
  END e_CP_IO_E<3>
  PIN e_CP_IO_E<4>
    DIRECTION INOUT ;
    USE SIGNAL ;
    PORT
      LAYER METAL3 ;
        RECT 6097.45 4339.6 6100.25 4341.0 ;
    END
  END e_CP_IO_E<4>
  PIN e_CP_IO_E<5>
    DIRECTION INOUT ;
    USE SIGNAL ;
    PORT
      LAYER METAL3 ;
        RECT 6097.45 4311.6 6100.25 4313.0 ;
    END
  END e_CP_IO_E<5>
  PIN e_CP_IO_E<6>
    DIRECTION INOUT ;
    USE SIGNAL ;
    PORT
      LAYER METAL3 ;
        RECT 6097.45 4283.6 6100.25 4285.0 ;
    END
  END e_CP_IO_E<6>
  PIN e_CP_IO_E<7>
    DIRECTION INOUT ;
    USE SIGNAL ;
    PORT
      LAYER METAL3 ;
        RECT 6097.45 4255.6 6100.25 4257.0 ;
    END
  END e_CP_IO_E<7>
  PIN e_CP_IO_E<8>
    DIRECTION INOUT ;
    USE SIGNAL ;
    PORT
      LAYER METAL3 ;
        RECT 6097.45 4227.6 6100.25 4229.0 ;
    END
  END e_CP_IO_E<8>
  PIN e_CP_IO_E<9>
    DIRECTION INOUT ;
    USE SIGNAL ;
    PORT
      LAYER METAL3 ;
        RECT 6097.45 4199.6 6100.25 4201.0 ;
    END
  END e_CP_IO_E<9>
  PIN e_CP_IO_E<10>
    DIRECTION INOUT ;
    USE SIGNAL ;
    PORT
      LAYER METAL3 ;
        RECT 6097.45 4171.6 6100.25 4173.0 ;
    END
  END e_CP_IO_E<10>
  PIN e_CP_IO_E<11>
    DIRECTION INOUT ;
    USE SIGNAL ;
    PORT
      LAYER METAL3 ;
        RECT 6097.45 4143.6 6100.25 4145.0 ;
    END
  END e_CP_IO_E<11>
  PIN e_CP_IO_E<12>
    DIRECTION INOUT ;
    USE SIGNAL ;
    PORT
      LAYER METAL3 ;
        RECT 6097.45 4115.6 6100.25 4117.0 ;
    END
  END e_CP_IO_E<12>
  PIN e_CP_IO_E<13>
    DIRECTION INOUT ;
    USE SIGNAL ;
    PORT
      LAYER METAL3 ;
        RECT 6097.45 4087.6 6100.25 4089.0 ;
    END
  END e_CP_IO_E<13>
  PIN e_CP_IO_E<14>
    DIRECTION INOUT ;
    USE SIGNAL ;
    PORT
      LAYER METAL3 ;
        RECT 6097.45 4059.6 6100.25 4061.0 ;
    END
  END e_CP_IO_E<14>
  PIN e_CP_IO_E<15>
    DIRECTION INOUT ;
    USE SIGNAL ;
    PORT
      LAYER METAL3 ;
        RECT 6097.45 4031.6 6100.25 4033.0 ;
    END
  END e_CP_IO_E<15>
  PIN e_CP_IO_E<16>
    DIRECTION INOUT ;
    USE SIGNAL ;
    PORT
      LAYER METAL3 ;
        RECT 6097.45 4003.6 6100.25 4005.0 ;
    END
  END e_CP_IO_E<16>
  PIN e_CP_IO_E<17>
    DIRECTION INOUT ;
    USE SIGNAL ;
    PORT
      LAYER METAL3 ;
        RECT 6097.45 3975.6 6100.25 3977.0 ;
    END
  END e_CP_IO_E<17>
  PIN e_CP_IO_E<18>
    DIRECTION INOUT ;
    USE SIGNAL ;
    PORT
      LAYER METAL3 ;
        RECT 6097.45 3947.6 6100.25 3949.0 ;
    END
  END e_CP_IO_E<18>
  PIN e_CP_IO_E<19>
    DIRECTION INOUT ;
    USE SIGNAL ;
    PORT
      LAYER METAL3 ;
        RECT 6097.45 3919.6 6100.25 3921.0 ;
    END
  END e_CP_IO_E<19>
  PIN e_CP_IO_E<20>
    DIRECTION INOUT ;
    USE SIGNAL ;
    PORT
      LAYER METAL3 ;
        RECT 6097.45 3891.6 6100.25 3893.0 ;
    END
  END e_CP_IO_E<20>
  PIN e_CP_IO_E<21>
    DIRECTION INOUT ;
    USE SIGNAL ;
    PORT
      LAYER METAL3 ;
        RECT 6097.45 3863.6 6100.25 3865.0 ;
    END
  END e_CP_IO_E<21>
  PIN e_CP_IO_E<22>
    DIRECTION INOUT ;
    USE SIGNAL ;
    PORT
      LAYER METAL3 ;
        RECT 6097.45 3835.6 6100.25 3837.0 ;
    END
  END e_CP_IO_E<22>
  PIN e_CP_IO_E<23>
    DIRECTION INOUT ;
    USE SIGNAL ;
    PORT
      LAYER METAL3 ;
        RECT 6097.45 3807.6 6100.25 3809.0 ;
    END
  END e_CP_IO_E<23>
  PIN e_CP_IO_E<24>
    DIRECTION INOUT ;
    USE SIGNAL ;
    PORT
      LAYER METAL3 ;
        RECT 6097.45 3779.6 6100.25 3781.0 ;
    END
  END e_CP_IO_E<24>
  PIN e_CP_IO_E<25>
    DIRECTION INOUT ;
    USE SIGNAL ;
    PORT
      LAYER METAL3 ;
        RECT 6097.45 3751.6 6100.25 3753.0 ;
    END
  END e_CP_IO_E<25>
  PIN e_CP_IO_E<26>
    DIRECTION INOUT ;
    USE SIGNAL ;
    PORT
      LAYER METAL3 ;
        RECT 6097.45 3723.6 6100.25 3725.0 ;
    END
  END e_CP_IO_E<26>
  PIN e_CP_IO_E<27>
    DIRECTION INOUT ;
    USE SIGNAL ;
    PORT
      LAYER METAL3 ;
        RECT 6097.45 3695.6 6100.25 3697.0 ;
    END
  END e_CP_IO_E<27>
  PIN e_CP_IO_E<28>
    DIRECTION INOUT ;
    USE SIGNAL ;
    PORT
      LAYER METAL3 ;
        RECT 6097.45 3667.6 6100.25 3669.0 ;
    END
  END e_CP_IO_E<28>
  PIN e_CP_IO_E<29>
    DIRECTION INOUT ;
    USE SIGNAL ;
    PORT
      LAYER METAL3 ;
        RECT 6097.45 3639.6 6100.25 3641.0 ;
    END
  END e_CP_IO_E<29>
  PIN e_CP_DVDD_E
    DIRECTION INOUT ;
    USE SIGNAL ;
    PORT
      LAYER METAL3 ;
        RECT 6097.45 3611.6 6100.25 3613.0 ;
    END
  END e_CP_DVDD_E
  PIN s_CP_IO_S<0>
    DIRECTION INOUT ;
    USE SIGNAL ;
    PORT
      LAYER METAL3 ;
        RECT 27.3 0.0 28.7 2.8 ;
    END
  END s_CP_IO_S<0>
  PIN s_CP_IO_S<1>
    DIRECTION INOUT ;
    USE SIGNAL ;
    PORT
      LAYER METAL3 ;
        RECT 55.3 0.0 56.7 2.8 ;
    END
  END s_CP_IO_S<1>
  PIN s_CP_IO_S<2>
    DIRECTION INOUT ;
    USE SIGNAL ;
    PORT
      LAYER METAL3 ;
        RECT 83.3 0.0 84.7 2.8 ;
    END
  END s_CP_IO_S<2>
  PIN s_CP_IO_S<3>
    DIRECTION INOUT ;
    USE SIGNAL ;
    PORT
      LAYER METAL3 ;
        RECT 111.3 0.0 112.7 2.8 ;
    END
  END s_CP_IO_S<3>
  PIN s_CP_IO_S<4>
    DIRECTION INOUT ;
    USE SIGNAL ;
    PORT
      LAYER METAL3 ;
        RECT 139.3 0.0 140.7 2.8 ;
    END
  END s_CP_IO_S<4>
  PIN s_CP_IO_S<5>
    DIRECTION INOUT ;
    USE SIGNAL ;
    PORT
      LAYER METAL3 ;
        RECT 167.3 0.0 168.7 2.8 ;
    END
  END s_CP_IO_S<5>
  PIN s_CP_IO_S<6>
    DIRECTION INOUT ;
    USE SIGNAL ;
    PORT
      LAYER METAL3 ;
        RECT 195.3 0.0 196.7 2.8 ;
    END
  END s_CP_IO_S<6>
  PIN s_CP_IO_S<7>
    DIRECTION INOUT ;
    USE SIGNAL ;
    PORT
      LAYER METAL3 ;
        RECT 223.3 0.0 224.7 2.8 ;
    END
  END s_CP_IO_S<7>
  PIN s_CP_IO_S<8>
    DIRECTION INOUT ;
    USE SIGNAL ;
    PORT
      LAYER METAL3 ;
        RECT 251.3 0.0 252.7 2.8 ;
    END
  END s_CP_IO_S<8>
  PIN s_CP_IO_S<9>
    DIRECTION INOUT ;
    USE SIGNAL ;
    PORT
      LAYER METAL3 ;
        RECT 279.3 0.0 280.7 2.8 ;
    END
  END s_CP_IO_S<9>
  PIN s_CP_IO_S<10>
    DIRECTION INOUT ;
    USE SIGNAL ;
    PORT
      LAYER METAL3 ;
        RECT 307.3 0.0 308.7 2.8 ;
    END
  END s_CP_IO_S<10>
  PIN s_CP_IO_S<11>
    DIRECTION INOUT ;
    USE SIGNAL ;
    PORT
      LAYER METAL3 ;
        RECT 335.3 0.0 336.7 2.8 ;
    END
  END s_CP_IO_S<11>
  PIN w_CP_DVDD_W
    DIRECTION INOUT ;
    USE SIGNAL ;
    PORT
      LAYER METAL3 ;
        RECT 0.0 4535.6 2.8 4537.0 ;
    END
  END w_CP_DVDD_W
  PIN w_CP_VINJ_W
    DIRECTION INOUT ;
    USE SIGNAL ;
    PORT
      LAYER METAL3 ;
        RECT 0.0 4507.6 2.8 4509.0 ;
    END
  END w_CP_VINJ_W
  PIN w_CP_gnd_W_2
    DIRECTION INOUT ;
    USE SIGNAL ;
    PORT
      LAYER METAL3 ;
        RECT 0.0 4479.6 2.8 4481.0 ;
    END
  END w_CP_gnd_W_2
  PIN w_CP_IO_W_RES_0
    DIRECTION INOUT ;
    USE SIGNAL ;
    PORT
      LAYER METAL3 ;
        RECT 0.0 4451.6 2.8 4453.0 ;
    END
  END w_CP_IO_W_RES_0
  PIN w_CP_AVDD_W
    DIRECTION INOUT ;
    USE SIGNAL ;
    PORT
      LAYER METAL3 ;
        RECT 0.0 4423.6 2.8 4425.0 ;
    END
  END w_CP_AVDD_W
  PIN w_CP_IO_W<0>
    DIRECTION INOUT ;
    USE SIGNAL ;
    PORT
      LAYER METAL3 ;
        RECT 0.0 4395.6 2.8 4397.0 ;
    END
  END w_CP_IO_W<0>
  PIN w_CP_IO_W<1>
    DIRECTION INOUT ;
    USE SIGNAL ;
    PORT
      LAYER METAL3 ;
        RECT 0.0 4367.6 2.8 4369.0 ;
    END
  END w_CP_IO_W<1>
  PIN w_CP_IO_W<2>
    DIRECTION INOUT ;
    USE SIGNAL ;
    PORT
      LAYER METAL3 ;
        RECT 0.0 4339.6 2.8 4341.0 ;
    END
  END w_CP_IO_W<2>
  PIN w_CP_IO_W<3>
    DIRECTION INOUT ;
    USE SIGNAL ;
    PORT
      LAYER METAL3 ;
        RECT 0.0 4311.6 2.8 4313.0 ;
    END
  END w_CP_IO_W<3>
  PIN w_CP_IO_W<4>
    DIRECTION INOUT ;
    USE SIGNAL ;
    PORT
      LAYER METAL3 ;
        RECT 0.0 4283.6 2.8 4285.0 ;
    END
  END w_CP_IO_W<4>
  PIN w_CP_IO_W<5>
    DIRECTION INOUT ;
    USE SIGNAL ;
    PORT
      LAYER METAL3 ;
        RECT 0.0 4255.6 2.8 4257.0 ;
    END
  END w_CP_IO_W<5>
  PIN w_CP_IO_W<6>
    DIRECTION INOUT ;
    USE SIGNAL ;
    PORT
      LAYER METAL3 ;
        RECT 0.0 4227.6 2.8 4229.0 ;
    END
  END w_CP_IO_W<6>
  PIN w_CP_IO_W<7>
    DIRECTION INOUT ;
    USE SIGNAL ;
    PORT
      LAYER METAL3 ;
        RECT 0.0 4199.6 2.8 4201.0 ;
    END
  END w_CP_IO_W<7>
  PIN w_CP_IO_W<8>
    DIRECTION INOUT ;
    USE SIGNAL ;
    PORT
      LAYER METAL3 ;
        RECT 0.0 4171.6 2.8 4173.0 ;
    END
  END w_CP_IO_W<8>
  PIN w_CP_IO_W<9>
    DIRECTION INOUT ;
    USE SIGNAL ;
    PORT
      LAYER METAL3 ;
        RECT 0.0 4143.6 2.8 4145.0 ;
    END
  END w_CP_IO_W<9>
  PIN w_CP_IO_W<10>
    DIRECTION INOUT ;
    USE SIGNAL ;
    PORT
      LAYER METAL3 ;
        RECT 0.0 4115.6 2.8 4117.0 ;
    END
  END w_CP_IO_W<10>
  PIN w_CP_IO_W<11>
    DIRECTION INOUT ;
    USE SIGNAL ;
    PORT
      LAYER METAL3 ;
        RECT 0.0 4087.6 2.8 4089.0 ;
    END
  END w_CP_IO_W<11>
  PIN w_CP_IO_W<12>
    DIRECTION INOUT ;
    USE SIGNAL ;
    PORT
      LAYER METAL3 ;
        RECT 0.0 4059.6 2.8 4061.0 ;
    END
  END w_CP_IO_W<12>
  PIN w_CP_IO_W<13>
    DIRECTION INOUT ;
    USE SIGNAL ;
    PORT
      LAYER METAL3 ;
        RECT 0.0 4031.6 2.8 4033.0 ;
    END
  END w_CP_IO_W<13>
  PIN w_CP_IO_W<14>
    DIRECTION INOUT ;
    USE SIGNAL ;
    PORT
      LAYER METAL3 ;
        RECT 0.0 4003.6 2.8 4005.0 ;
    END
  END w_CP_IO_W<14>
  PIN w_CP_IO_W<15>
    DIRECTION INOUT ;
    USE SIGNAL ;
    PORT
      LAYER METAL3 ;
        RECT 0.0 3975.6 2.8 3977.0 ;
    END
  END w_CP_IO_W<15>
  PIN w_CP_IO_W<16>
    DIRECTION INOUT ;
    USE SIGNAL ;
    PORT
      LAYER METAL3 ;
        RECT 0.0 3947.6 2.8 3949.0 ;
    END
  END w_CP_IO_W<16>
END tile_analog_frame

MACRO TSMC350nm_VerticalScanner_STD
  PIN In<3>
    DIRECTION INOUT ;
    USE SIGNAL ;
    PORT
      LAYER METAL1 ;
        RECT 0.0 3.5 1.4 4.9 ;
    END
  END In<3>
  PIN In<2>
    DIRECTION INOUT ;
    USE SIGNAL ;
    PORT
      LAYER METAL1 ;
        RECT 0.0 6.3 1.5 7.7 ;
    END
  END In<2>
  PIN In<1>
    DIRECTION INOUT ;
    USE SIGNAL ;
    PORT
      LAYER METAL1 ;
        RECT 0.0 14.0 1.4 15.4 ;
    END
  END In<1>
  PIN In<0>
    DIRECTION INOUT ;
    USE SIGNAL ;
    PORT
      LAYER METAL1 ;
        RECT 0.0 17.5 1.4 18.9 ;
    END
  END In<0>
  PIN RSTBar_b
    DIRECTION INOUT ;
    USE SIGNAL ;
    PORT
      LAYER METAL2 ;
        RECT 156.1 0.0 157.5 1.23 ;
    END
  END RSTBar_b
  PIN CLK_b
    DIRECTION INOUT ;
    USE SIGNAL ;
    PORT
      LAYER METAL2 ;
        RECT 149.8 0.0 151.2 1.23 ;
    END
  END CLK_b
  PIN Out
    DIRECTION INOUT ;
    USE SIGNAL ;
    PORT
      LAYER METAL2 ;
        RECT 5.15 20.68 6.65 22.0 ;
    END
  END Out
  PIN Out_b
    DIRECTION INOUT ;
    USE SIGNAL ;
    PORT
      LAYER METAL2 ;
        RECT 5.15 0.0 6.65 1.27 ;
    END
  END Out_b
  PIN VDD_b
    DIRECTION INOUT ;
    USE SIGNAL ;
    PORT
      LAYER METAL2 ;
        RECT 45.86 0.0 47.36 1.28 ;
    END
  END VDD_b
  PIN GND_b
    DIRECTION INOUT ;
    USE SIGNAL ;
    PORT
      LAYER METAL2 ;
        RECT 53.79 0.0 55.29 1.23 ;
    END
  END GND_b
  PIN VDD
    DIRECTION INOUT ;
    USE SIGNAL ;
    PORT
      LAYER METAL2 ;
        RECT 45.86 20.77 47.36 22.0 ;
    END
  END VDD
  PIN GND
    DIRECTION INOUT ;
    USE SIGNAL ;
    PORT
      LAYER METAL2 ;
        RECT 53.79 20.84 55.29 22.0 ;
    END
  END GND
  PIN Din
    DIRECTION INOUT ;
    USE SIGNAL ;
    PORT
      LAYER METAL2 ;
        RECT 42.0 20.77 43.4 22.0 ;
    END
  END Din
  PIN Qout
    DIRECTION INOUT ;
    USE SIGNAL ;
    PORT
      LAYER METAL2 ;
        RECT 42.0 0.0 43.4 1.23 ;
    END
  END Qout
  PIN RSTBar
    DIRECTION INOUT ;
    USE SIGNAL ;
    PORT
      LAYER METAL2 ;
        RECT 156.1 20.77 157.5 22.0 ;
    END
  END RSTBar
  PIN CLK
    DIRECTION INOUT ;
    USE SIGNAL ;
    PORT
      LAYER METAL2 ;
        RECT 149.8 20.77 151.2 22.0 ;
    END
  END CLK
END TSMC350nm_VerticalScanner_STD

END LIBRARY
